VERSION 5.8 ;
BUSBITCHARS "[]" ;
DIVIDERCHAR "/" ;
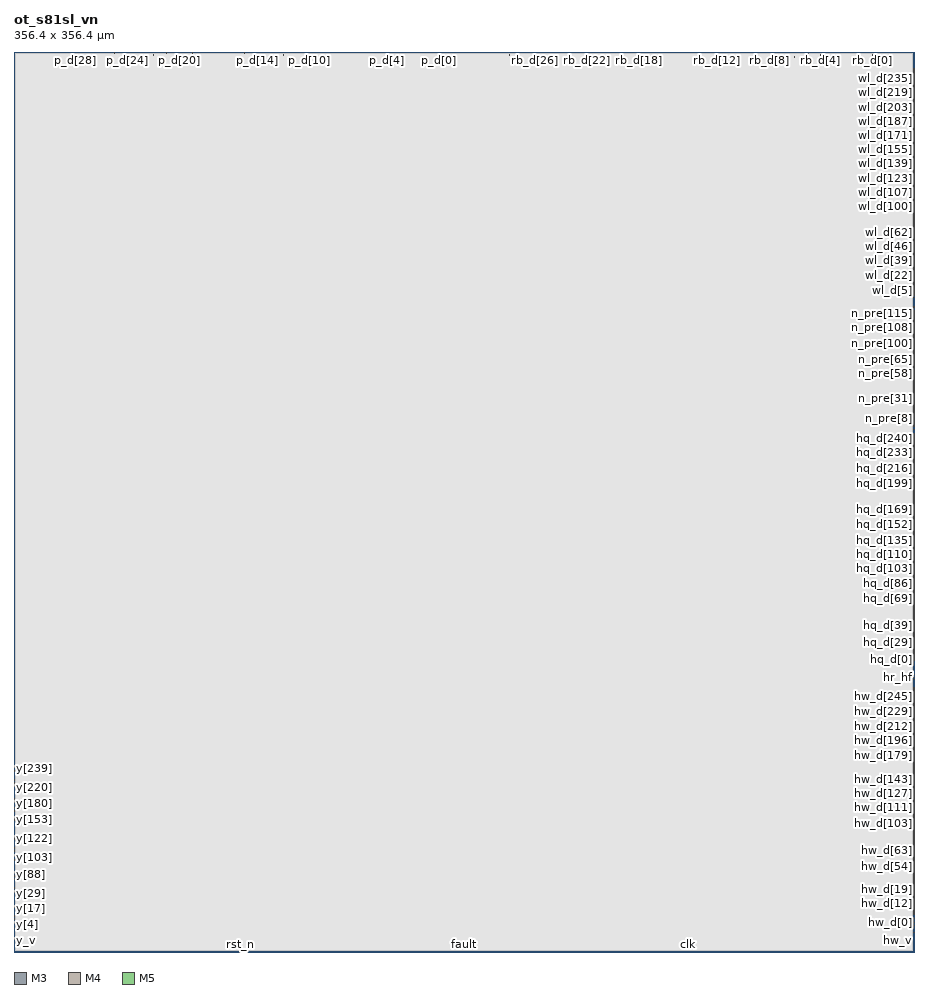
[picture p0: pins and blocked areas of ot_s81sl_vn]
MACRO ot_s81sl_vn
  CLASS BLOCK ;
  ORIGIN 0 0 ;
  FOREIGN ot_s81sl_vn 0 0 ;
  SIZE 356.400 BY 356.400 ;
  SYMMETRY X Y ;
  PIN clk
    DIRECTION INPUT ;
    USE SIGNAL ;
    PORT
      LAYER M3 ;
        RECT 266.7600 0.0495 266.7780 0.0875 ;
    END
  END clk
  PIN fault
    DIRECTION OUTPUT ;
    USE SIGNAL ;
    PORT
      LAYER M3 ;
        RECT 178.1640 1.6585 178.1820 1.6965 ;
    END
  END fault
  PIN hq_d[0]
    DIRECTION OUTPUT ;
    USE SIGNAL ;
    PORT
      LAYER M4 ;
        RECT 356.3160 115.6320 356.4000 115.6560 ;
    END
  END hq_d[0]
  PIN hq_d[100]
    DIRECTION OUTPUT ;
    USE SIGNAL ;
    PORT
      LAYER M4 ;
        RECT 356.3160 150.8160 356.4000 150.8400 ;
    END
  END hq_d[100]
  PIN hq_d[101]
    DIRECTION OUTPUT ;
    USE SIGNAL ;
    PORT
      LAYER M4 ;
        RECT 356.3160 151.1520 356.4000 151.1760 ;
    END
  END hq_d[101]
  PIN hq_d[102]
    DIRECTION OUTPUT ;
    USE SIGNAL ;
    PORT
      LAYER M4 ;
        RECT 356.3160 151.4880 356.4000 151.5120 ;
    END
  END hq_d[102]
  PIN hq_d[103]
    DIRECTION OUTPUT ;
    USE SIGNAL ;
    PORT
      LAYER M4 ;
        RECT 356.3160 151.8720 356.4000 151.8960 ;
    END
  END hq_d[103]
  PIN hq_d[104]
    DIRECTION OUTPUT ;
    USE SIGNAL ;
    PORT
      LAYER M4 ;
        RECT 356.3160 152.2080 356.4000 152.2320 ;
    END
  END hq_d[104]
  PIN hq_d[105]
    DIRECTION OUTPUT ;
    USE SIGNAL ;
    PORT
      LAYER M4 ;
        RECT 356.3160 152.5440 356.4000 152.5680 ;
    END
  END hq_d[105]
  PIN hq_d[106]
    DIRECTION OUTPUT ;
    USE SIGNAL ;
    PORT
      LAYER M4 ;
        RECT 356.3160 152.9280 356.4000 152.9520 ;
    END
  END hq_d[106]
  PIN hq_d[107]
    DIRECTION OUTPUT ;
    USE SIGNAL ;
    PORT
      LAYER M4 ;
        RECT 356.3160 153.2640 356.4000 153.2880 ;
    END
  END hq_d[107]
  PIN hq_d[108]
    DIRECTION OUTPUT ;
    USE SIGNAL ;
    PORT
      LAYER M4 ;
        RECT 356.3160 153.6000 356.4000 153.6240 ;
    END
  END hq_d[108]
  PIN hq_d[109]
    DIRECTION OUTPUT ;
    USE SIGNAL ;
    PORT
      LAYER M4 ;
        RECT 356.3160 153.9840 356.4000 154.0080 ;
    END
  END hq_d[109]
  PIN hq_d[10]
    DIRECTION OUTPUT ;
    USE SIGNAL ;
    PORT
      LAYER M4 ;
        RECT 356.3160 119.1360 356.4000 119.1600 ;
    END
  END hq_d[10]
  PIN hq_d[110]
    DIRECTION OUTPUT ;
    USE SIGNAL ;
    PORT
      LAYER M4 ;
        RECT 356.3160 154.3200 356.4000 154.3440 ;
    END
  END hq_d[110]
  PIN hq_d[111]
    DIRECTION OUTPUT ;
    USE SIGNAL ;
    PORT
      LAYER M4 ;
        RECT 356.3160 154.6560 356.4000 154.6800 ;
    END
  END hq_d[111]
  PIN hq_d[112]
    DIRECTION OUTPUT ;
    USE SIGNAL ;
    PORT
      LAYER M4 ;
        RECT 356.3160 155.0400 356.4000 155.0640 ;
    END
  END hq_d[112]
  PIN hq_d[113]
    DIRECTION OUTPUT ;
    USE SIGNAL ;
    PORT
      LAYER M4 ;
        RECT 356.3160 155.3760 356.4000 155.4000 ;
    END
  END hq_d[113]
  PIN hq_d[114]
    DIRECTION OUTPUT ;
    USE SIGNAL ;
    PORT
      LAYER M4 ;
        RECT 356.3160 155.7120 356.4000 155.7360 ;
    END
  END hq_d[114]
  PIN hq_d[115]
    DIRECTION OUTPUT ;
    USE SIGNAL ;
    PORT
      LAYER M4 ;
        RECT 356.3160 156.0960 356.4000 156.1200 ;
    END
  END hq_d[115]
  PIN hq_d[116]
    DIRECTION OUTPUT ;
    USE SIGNAL ;
    PORT
      LAYER M4 ;
        RECT 356.3160 156.4320 356.4000 156.4560 ;
    END
  END hq_d[116]
  PIN hq_d[117]
    DIRECTION OUTPUT ;
    USE SIGNAL ;
    PORT
      LAYER M4 ;
        RECT 356.3160 156.7680 356.4000 156.7920 ;
    END
  END hq_d[117]
  PIN hq_d[118]
    DIRECTION OUTPUT ;
    USE SIGNAL ;
    PORT
      LAYER M4 ;
        RECT 356.3160 157.1520 356.4000 157.1760 ;
    END
  END hq_d[118]
  PIN hq_d[119]
    DIRECTION OUTPUT ;
    USE SIGNAL ;
    PORT
      LAYER M4 ;
        RECT 356.3160 157.4880 356.4000 157.5120 ;
    END
  END hq_d[119]
  PIN hq_d[11]
    DIRECTION OUTPUT ;
    USE SIGNAL ;
    PORT
      LAYER M4 ;
        RECT 356.3160 119.4720 356.4000 119.4960 ;
    END
  END hq_d[11]
  PIN hq_d[120]
    DIRECTION OUTPUT ;
    USE SIGNAL ;
    PORT
      LAYER M4 ;
        RECT 356.3160 157.8240 356.4000 157.8480 ;
    END
  END hq_d[120]
  PIN hq_d[121]
    DIRECTION OUTPUT ;
    USE SIGNAL ;
    PORT
      LAYER M4 ;
        RECT 356.3160 158.2080 356.4000 158.2320 ;
    END
  END hq_d[121]
  PIN hq_d[122]
    DIRECTION OUTPUT ;
    USE SIGNAL ;
    PORT
      LAYER M4 ;
        RECT 356.3160 158.5440 356.4000 158.5680 ;
    END
  END hq_d[122]
  PIN hq_d[123]
    DIRECTION OUTPUT ;
    USE SIGNAL ;
    PORT
      LAYER M4 ;
        RECT 356.3160 158.8800 356.4000 158.9040 ;
    END
  END hq_d[123]
  PIN hq_d[124]
    DIRECTION OUTPUT ;
    USE SIGNAL ;
    PORT
      LAYER M4 ;
        RECT 356.3160 159.2640 356.4000 159.2880 ;
    END
  END hq_d[124]
  PIN hq_d[125]
    DIRECTION OUTPUT ;
    USE SIGNAL ;
    PORT
      LAYER M4 ;
        RECT 356.3160 159.6000 356.4000 159.6240 ;
    END
  END hq_d[125]
  PIN hq_d[126]
    DIRECTION OUTPUT ;
    USE SIGNAL ;
    PORT
      LAYER M4 ;
        RECT 356.3160 159.9360 356.4000 159.9600 ;
    END
  END hq_d[126]
  PIN hq_d[127]
    DIRECTION OUTPUT ;
    USE SIGNAL ;
    PORT
      LAYER M4 ;
        RECT 356.3160 160.3200 356.4000 160.3440 ;
    END
  END hq_d[127]
  PIN hq_d[128]
    DIRECTION OUTPUT ;
    USE SIGNAL ;
    PORT
      LAYER M4 ;
        RECT 356.3160 160.6560 356.4000 160.6800 ;
    END
  END hq_d[128]
  PIN hq_d[129]
    DIRECTION OUTPUT ;
    USE SIGNAL ;
    PORT
      LAYER M4 ;
        RECT 356.3160 160.9920 356.4000 161.0160 ;
    END
  END hq_d[129]
  PIN hq_d[12]
    DIRECTION OUTPUT ;
    USE SIGNAL ;
    PORT
      LAYER M4 ;
        RECT 356.3160 119.8560 356.4000 119.8800 ;
    END
  END hq_d[12]
  PIN hq_d[130]
    DIRECTION OUTPUT ;
    USE SIGNAL ;
    PORT
      LAYER M4 ;
        RECT 356.3160 161.3760 356.4000 161.4000 ;
    END
  END hq_d[130]
  PIN hq_d[131]
    DIRECTION OUTPUT ;
    USE SIGNAL ;
    PORT
      LAYER M4 ;
        RECT 356.3160 161.7120 356.4000 161.7360 ;
    END
  END hq_d[131]
  PIN hq_d[132]
    DIRECTION OUTPUT ;
    USE SIGNAL ;
    PORT
      LAYER M4 ;
        RECT 356.3160 162.0480 356.4000 162.0720 ;
    END
  END hq_d[132]
  PIN hq_d[133]
    DIRECTION OUTPUT ;
    USE SIGNAL ;
    PORT
      LAYER M4 ;
        RECT 356.3160 162.4320 356.4000 162.4560 ;
    END
  END hq_d[133]
  PIN hq_d[134]
    DIRECTION OUTPUT ;
    USE SIGNAL ;
    PORT
      LAYER M4 ;
        RECT 356.3160 162.7680 356.4000 162.7920 ;
    END
  END hq_d[134]
  PIN hq_d[135]
    DIRECTION OUTPUT ;
    USE SIGNAL ;
    PORT
      LAYER M4 ;
        RECT 356.3160 163.1040 356.4000 163.1280 ;
    END
  END hq_d[135]
  PIN hq_d[136]
    DIRECTION OUTPUT ;
    USE SIGNAL ;
    PORT
      LAYER M4 ;
        RECT 356.3160 163.4880 356.4000 163.5120 ;
    END
  END hq_d[136]
  PIN hq_d[137]
    DIRECTION OUTPUT ;
    USE SIGNAL ;
    PORT
      LAYER M4 ;
        RECT 356.3160 163.8240 356.4000 163.8480 ;
    END
  END hq_d[137]
  PIN hq_d[138]
    DIRECTION OUTPUT ;
    USE SIGNAL ;
    PORT
      LAYER M4 ;
        RECT 356.3160 164.1600 356.4000 164.1840 ;
    END
  END hq_d[138]
  PIN hq_d[139]
    DIRECTION OUTPUT ;
    USE SIGNAL ;
    PORT
      LAYER M4 ;
        RECT 356.3160 164.5440 356.4000 164.5680 ;
    END
  END hq_d[139]
  PIN hq_d[13]
    DIRECTION OUTPUT ;
    USE SIGNAL ;
    PORT
      LAYER M4 ;
        RECT 356.3160 120.1920 356.4000 120.2160 ;
    END
  END hq_d[13]
  PIN hq_d[140]
    DIRECTION OUTPUT ;
    USE SIGNAL ;
    PORT
      LAYER M4 ;
        RECT 356.3160 164.8800 356.4000 164.9040 ;
    END
  END hq_d[140]
  PIN hq_d[141]
    DIRECTION OUTPUT ;
    USE SIGNAL ;
    PORT
      LAYER M4 ;
        RECT 356.3160 165.2160 356.4000 165.2400 ;
    END
  END hq_d[141]
  PIN hq_d[142]
    DIRECTION OUTPUT ;
    USE SIGNAL ;
    PORT
      LAYER M4 ;
        RECT 356.3160 165.6000 356.4000 165.6240 ;
    END
  END hq_d[142]
  PIN hq_d[143]
    DIRECTION OUTPUT ;
    USE SIGNAL ;
    PORT
      LAYER M4 ;
        RECT 356.3160 165.9360 356.4000 165.9600 ;
    END
  END hq_d[143]
  PIN hq_d[144]
    DIRECTION OUTPUT ;
    USE SIGNAL ;
    PORT
      LAYER M4 ;
        RECT 356.3160 166.2720 356.4000 166.2960 ;
    END
  END hq_d[144]
  PIN hq_d[145]
    DIRECTION OUTPUT ;
    USE SIGNAL ;
    PORT
      LAYER M4 ;
        RECT 356.3160 166.6560 356.4000 166.6800 ;
    END
  END hq_d[145]
  PIN hq_d[146]
    DIRECTION OUTPUT ;
    USE SIGNAL ;
    PORT
      LAYER M4 ;
        RECT 356.3160 166.9920 356.4000 167.0160 ;
    END
  END hq_d[146]
  PIN hq_d[147]
    DIRECTION OUTPUT ;
    USE SIGNAL ;
    PORT
      LAYER M4 ;
        RECT 356.3160 167.3280 356.4000 167.3520 ;
    END
  END hq_d[147]
  PIN hq_d[148]
    DIRECTION OUTPUT ;
    USE SIGNAL ;
    PORT
      LAYER M4 ;
        RECT 356.3160 167.7120 356.4000 167.7360 ;
    END
  END hq_d[148]
  PIN hq_d[149]
    DIRECTION OUTPUT ;
    USE SIGNAL ;
    PORT
      LAYER M4 ;
        RECT 356.3160 168.0480 356.4000 168.0720 ;
    END
  END hq_d[149]
  PIN hq_d[14]
    DIRECTION OUTPUT ;
    USE SIGNAL ;
    PORT
      LAYER M4 ;
        RECT 356.3160 120.5280 356.4000 120.5520 ;
    END
  END hq_d[14]
  PIN hq_d[150]
    DIRECTION OUTPUT ;
    USE SIGNAL ;
    PORT
      LAYER M4 ;
        RECT 356.3160 168.3840 356.4000 168.4080 ;
    END
  END hq_d[150]
  PIN hq_d[151]
    DIRECTION OUTPUT ;
    USE SIGNAL ;
    PORT
      LAYER M4 ;
        RECT 356.3160 168.7680 356.4000 168.7920 ;
    END
  END hq_d[151]
  PIN hq_d[152]
    DIRECTION OUTPUT ;
    USE SIGNAL ;
    PORT
      LAYER M4 ;
        RECT 356.3160 169.1040 356.4000 169.1280 ;
    END
  END hq_d[152]
  PIN hq_d[153]
    DIRECTION OUTPUT ;
    USE SIGNAL ;
    PORT
      LAYER M4 ;
        RECT 356.3160 169.4400 356.4000 169.4640 ;
    END
  END hq_d[153]
  PIN hq_d[154]
    DIRECTION OUTPUT ;
    USE SIGNAL ;
    PORT
      LAYER M4 ;
        RECT 356.3160 169.8240 356.4000 169.8480 ;
    END
  END hq_d[154]
  PIN hq_d[155]
    DIRECTION OUTPUT ;
    USE SIGNAL ;
    PORT
      LAYER M4 ;
        RECT 356.3160 170.1600 356.4000 170.1840 ;
    END
  END hq_d[155]
  PIN hq_d[156]
    DIRECTION OUTPUT ;
    USE SIGNAL ;
    PORT
      LAYER M4 ;
        RECT 356.3160 170.4960 356.4000 170.5200 ;
    END
  END hq_d[156]
  PIN hq_d[157]
    DIRECTION OUTPUT ;
    USE SIGNAL ;
    PORT
      LAYER M4 ;
        RECT 356.3160 170.8800 356.4000 170.9040 ;
    END
  END hq_d[157]
  PIN hq_d[158]
    DIRECTION OUTPUT ;
    USE SIGNAL ;
    PORT
      LAYER M4 ;
        RECT 356.3160 171.2160 356.4000 171.2400 ;
    END
  END hq_d[158]
  PIN hq_d[159]
    DIRECTION OUTPUT ;
    USE SIGNAL ;
    PORT
      LAYER M4 ;
        RECT 356.3160 171.5520 356.4000 171.5760 ;
    END
  END hq_d[159]
  PIN hq_d[15]
    DIRECTION OUTPUT ;
    USE SIGNAL ;
    PORT
      LAYER M4 ;
        RECT 356.3160 120.9120 356.4000 120.9360 ;
    END
  END hq_d[15]
  PIN hq_d[160]
    DIRECTION OUTPUT ;
    USE SIGNAL ;
    PORT
      LAYER M4 ;
        RECT 356.3160 171.9360 356.4000 171.9600 ;
    END
  END hq_d[160]
  PIN hq_d[161]
    DIRECTION OUTPUT ;
    USE SIGNAL ;
    PORT
      LAYER M4 ;
        RECT 356.3160 172.2720 356.4000 172.2960 ;
    END
  END hq_d[161]
  PIN hq_d[162]
    DIRECTION OUTPUT ;
    USE SIGNAL ;
    PORT
      LAYER M4 ;
        RECT 356.3160 172.6080 356.4000 172.6320 ;
    END
  END hq_d[162]
  PIN hq_d[163]
    DIRECTION OUTPUT ;
    USE SIGNAL ;
    PORT
      LAYER M4 ;
        RECT 356.3160 172.9920 356.4000 173.0160 ;
    END
  END hq_d[163]
  PIN hq_d[164]
    DIRECTION OUTPUT ;
    USE SIGNAL ;
    PORT
      LAYER M4 ;
        RECT 356.3160 173.3280 356.4000 173.3520 ;
    END
  END hq_d[164]
  PIN hq_d[165]
    DIRECTION OUTPUT ;
    USE SIGNAL ;
    PORT
      LAYER M4 ;
        RECT 356.3160 173.6640 356.4000 173.6880 ;
    END
  END hq_d[165]
  PIN hq_d[166]
    DIRECTION OUTPUT ;
    USE SIGNAL ;
    PORT
      LAYER M4 ;
        RECT 356.3160 174.0480 356.4000 174.0720 ;
    END
  END hq_d[166]
  PIN hq_d[167]
    DIRECTION OUTPUT ;
    USE SIGNAL ;
    PORT
      LAYER M4 ;
        RECT 356.3160 174.3840 356.4000 174.4080 ;
    END
  END hq_d[167]
  PIN hq_d[168]
    DIRECTION OUTPUT ;
    USE SIGNAL ;
    PORT
      LAYER M4 ;
        RECT 356.3160 174.7200 356.4000 174.7440 ;
    END
  END hq_d[168]
  PIN hq_d[169]
    DIRECTION OUTPUT ;
    USE SIGNAL ;
    PORT
      LAYER M4 ;
        RECT 356.3160 175.1040 356.4000 175.1280 ;
    END
  END hq_d[169]
  PIN hq_d[16]
    DIRECTION OUTPUT ;
    USE SIGNAL ;
    PORT
      LAYER M4 ;
        RECT 356.3160 121.2480 356.4000 121.2720 ;
    END
  END hq_d[16]
  PIN hq_d[170]
    DIRECTION OUTPUT ;
    USE SIGNAL ;
    PORT
      LAYER M4 ;
        RECT 356.3160 175.4400 356.4000 175.4640 ;
    END
  END hq_d[170]
  PIN hq_d[171]
    DIRECTION OUTPUT ;
    USE SIGNAL ;
    PORT
      LAYER M4 ;
        RECT 356.3160 175.7760 356.4000 175.8000 ;
    END
  END hq_d[171]
  PIN hq_d[172]
    DIRECTION OUTPUT ;
    USE SIGNAL ;
    PORT
      LAYER M4 ;
        RECT 356.3160 176.1600 356.4000 176.1840 ;
    END
  END hq_d[172]
  PIN hq_d[173]
    DIRECTION OUTPUT ;
    USE SIGNAL ;
    PORT
      LAYER M4 ;
        RECT 356.3160 176.4960 356.4000 176.5200 ;
    END
  END hq_d[173]
  PIN hq_d[174]
    DIRECTION OUTPUT ;
    USE SIGNAL ;
    PORT
      LAYER M4 ;
        RECT 356.3160 176.8320 356.4000 176.8560 ;
    END
  END hq_d[174]
  PIN hq_d[175]
    DIRECTION OUTPUT ;
    USE SIGNAL ;
    PORT
      LAYER M4 ;
        RECT 356.3160 177.2160 356.4000 177.2400 ;
    END
  END hq_d[175]
  PIN hq_d[176]
    DIRECTION OUTPUT ;
    USE SIGNAL ;
    PORT
      LAYER M4 ;
        RECT 356.3160 177.5520 356.4000 177.5760 ;
    END
  END hq_d[176]
  PIN hq_d[177]
    DIRECTION OUTPUT ;
    USE SIGNAL ;
    PORT
      LAYER M4 ;
        RECT 356.3160 177.8880 356.4000 177.9120 ;
    END
  END hq_d[177]
  PIN hq_d[178]
    DIRECTION OUTPUT ;
    USE SIGNAL ;
    PORT
      LAYER M4 ;
        RECT 356.3160 178.2720 356.4000 178.2960 ;
    END
  END hq_d[178]
  PIN hq_d[179]
    DIRECTION OUTPUT ;
    USE SIGNAL ;
    PORT
      LAYER M4 ;
        RECT 356.3160 178.6080 356.4000 178.6320 ;
    END
  END hq_d[179]
  PIN hq_d[17]
    DIRECTION OUTPUT ;
    USE SIGNAL ;
    PORT
      LAYER M4 ;
        RECT 356.3160 121.5840 356.4000 121.6080 ;
    END
  END hq_d[17]
  PIN hq_d[180]
    DIRECTION OUTPUT ;
    USE SIGNAL ;
    PORT
      LAYER M4 ;
        RECT 356.3160 178.9440 356.4000 178.9680 ;
    END
  END hq_d[180]
  PIN hq_d[181]
    DIRECTION OUTPUT ;
    USE SIGNAL ;
    PORT
      LAYER M4 ;
        RECT 356.3160 179.2800 356.4000 179.3040 ;
    END
  END hq_d[181]
  PIN hq_d[182]
    DIRECTION OUTPUT ;
    USE SIGNAL ;
    PORT
      LAYER M4 ;
        RECT 356.3160 179.6640 356.4000 179.6880 ;
    END
  END hq_d[182]
  PIN hq_d[183]
    DIRECTION OUTPUT ;
    USE SIGNAL ;
    PORT
      LAYER M4 ;
        RECT 356.3160 180.0000 356.4000 180.0240 ;
    END
  END hq_d[183]
  PIN hq_d[184]
    DIRECTION OUTPUT ;
    USE SIGNAL ;
    PORT
      LAYER M4 ;
        RECT 356.3160 180.3360 356.4000 180.3600 ;
    END
  END hq_d[184]
  PIN hq_d[185]
    DIRECTION OUTPUT ;
    USE SIGNAL ;
    PORT
      LAYER M4 ;
        RECT 356.3160 180.7200 356.4000 180.7440 ;
    END
  END hq_d[185]
  PIN hq_d[186]
    DIRECTION OUTPUT ;
    USE SIGNAL ;
    PORT
      LAYER M4 ;
        RECT 356.3160 181.0560 356.4000 181.0800 ;
    END
  END hq_d[186]
  PIN hq_d[187]
    DIRECTION OUTPUT ;
    USE SIGNAL ;
    PORT
      LAYER M4 ;
        RECT 356.3160 181.3920 356.4000 181.4160 ;
    END
  END hq_d[187]
  PIN hq_d[188]
    DIRECTION OUTPUT ;
    USE SIGNAL ;
    PORT
      LAYER M4 ;
        RECT 356.3160 181.7760 356.4000 181.8000 ;
    END
  END hq_d[188]
  PIN hq_d[189]
    DIRECTION OUTPUT ;
    USE SIGNAL ;
    PORT
      LAYER M4 ;
        RECT 356.3160 182.1120 356.4000 182.1360 ;
    END
  END hq_d[189]
  PIN hq_d[18]
    DIRECTION OUTPUT ;
    USE SIGNAL ;
    PORT
      LAYER M4 ;
        RECT 356.3160 121.9680 356.4000 121.9920 ;
    END
  END hq_d[18]
  PIN hq_d[190]
    DIRECTION OUTPUT ;
    USE SIGNAL ;
    PORT
      LAYER M4 ;
        RECT 356.3160 182.4480 356.4000 182.4720 ;
    END
  END hq_d[190]
  PIN hq_d[191]
    DIRECTION OUTPUT ;
    USE SIGNAL ;
    PORT
      LAYER M4 ;
        RECT 356.3160 182.8320 356.4000 182.8560 ;
    END
  END hq_d[191]
  PIN hq_d[192]
    DIRECTION OUTPUT ;
    USE SIGNAL ;
    PORT
      LAYER M4 ;
        RECT 356.3160 183.1680 356.4000 183.1920 ;
    END
  END hq_d[192]
  PIN hq_d[193]
    DIRECTION OUTPUT ;
    USE SIGNAL ;
    PORT
      LAYER M4 ;
        RECT 356.3160 183.5040 356.4000 183.5280 ;
    END
  END hq_d[193]
  PIN hq_d[194]
    DIRECTION OUTPUT ;
    USE SIGNAL ;
    PORT
      LAYER M4 ;
        RECT 356.3160 183.8880 356.4000 183.9120 ;
    END
  END hq_d[194]
  PIN hq_d[195]
    DIRECTION OUTPUT ;
    USE SIGNAL ;
    PORT
      LAYER M4 ;
        RECT 356.3160 184.2240 356.4000 184.2480 ;
    END
  END hq_d[195]
  PIN hq_d[196]
    DIRECTION OUTPUT ;
    USE SIGNAL ;
    PORT
      LAYER M4 ;
        RECT 356.3160 184.5600 356.4000 184.5840 ;
    END
  END hq_d[196]
  PIN hq_d[197]
    DIRECTION OUTPUT ;
    USE SIGNAL ;
    PORT
      LAYER M4 ;
        RECT 356.3160 184.9440 356.4000 184.9680 ;
    END
  END hq_d[197]
  PIN hq_d[198]
    DIRECTION OUTPUT ;
    USE SIGNAL ;
    PORT
      LAYER M4 ;
        RECT 356.3160 185.2800 356.4000 185.3040 ;
    END
  END hq_d[198]
  PIN hq_d[199]
    DIRECTION OUTPUT ;
    USE SIGNAL ;
    PORT
      LAYER M4 ;
        RECT 356.3160 185.6160 356.4000 185.6400 ;
    END
  END hq_d[199]
  PIN hq_d[19]
    DIRECTION OUTPUT ;
    USE SIGNAL ;
    PORT
      LAYER M4 ;
        RECT 356.3160 122.3040 356.4000 122.3280 ;
    END
  END hq_d[19]
  PIN hq_d[1]
    DIRECTION OUTPUT ;
    USE SIGNAL ;
    PORT
      LAYER M4 ;
        RECT 356.3160 115.9680 356.4000 115.9920 ;
    END
  END hq_d[1]
  PIN hq_d[200]
    DIRECTION OUTPUT ;
    USE SIGNAL ;
    PORT
      LAYER M4 ;
        RECT 356.3160 186.0000 356.4000 186.0240 ;
    END
  END hq_d[200]
  PIN hq_d[201]
    DIRECTION OUTPUT ;
    USE SIGNAL ;
    PORT
      LAYER M4 ;
        RECT 356.3160 186.3360 356.4000 186.3600 ;
    END
  END hq_d[201]
  PIN hq_d[202]
    DIRECTION OUTPUT ;
    USE SIGNAL ;
    PORT
      LAYER M4 ;
        RECT 356.3160 186.6720 356.4000 186.6960 ;
    END
  END hq_d[202]
  PIN hq_d[203]
    DIRECTION OUTPUT ;
    USE SIGNAL ;
    PORT
      LAYER M4 ;
        RECT 356.3160 187.0560 356.4000 187.0800 ;
    END
  END hq_d[203]
  PIN hq_d[204]
    DIRECTION OUTPUT ;
    USE SIGNAL ;
    PORT
      LAYER M4 ;
        RECT 356.3160 187.3920 356.4000 187.4160 ;
    END
  END hq_d[204]
  PIN hq_d[205]
    DIRECTION OUTPUT ;
    USE SIGNAL ;
    PORT
      LAYER M4 ;
        RECT 356.3160 187.7280 356.4000 187.7520 ;
    END
  END hq_d[205]
  PIN hq_d[206]
    DIRECTION OUTPUT ;
    USE SIGNAL ;
    PORT
      LAYER M4 ;
        RECT 356.3160 188.1120 356.4000 188.1360 ;
    END
  END hq_d[206]
  PIN hq_d[207]
    DIRECTION OUTPUT ;
    USE SIGNAL ;
    PORT
      LAYER M4 ;
        RECT 356.3160 188.4480 356.4000 188.4720 ;
    END
  END hq_d[207]
  PIN hq_d[208]
    DIRECTION OUTPUT ;
    USE SIGNAL ;
    PORT
      LAYER M4 ;
        RECT 356.3160 188.7840 356.4000 188.8080 ;
    END
  END hq_d[208]
  PIN hq_d[209]
    DIRECTION OUTPUT ;
    USE SIGNAL ;
    PORT
      LAYER M4 ;
        RECT 356.3160 189.1680 356.4000 189.1920 ;
    END
  END hq_d[209]
  PIN hq_d[20]
    DIRECTION OUTPUT ;
    USE SIGNAL ;
    PORT
      LAYER M4 ;
        RECT 356.3160 122.6400 356.4000 122.6640 ;
    END
  END hq_d[20]
  PIN hq_d[210]
    DIRECTION OUTPUT ;
    USE SIGNAL ;
    PORT
      LAYER M4 ;
        RECT 356.3160 189.5040 356.4000 189.5280 ;
    END
  END hq_d[210]
  PIN hq_d[211]
    DIRECTION OUTPUT ;
    USE SIGNAL ;
    PORT
      LAYER M4 ;
        RECT 356.3160 189.8400 356.4000 189.8640 ;
    END
  END hq_d[211]
  PIN hq_d[212]
    DIRECTION OUTPUT ;
    USE SIGNAL ;
    PORT
      LAYER M4 ;
        RECT 356.3160 190.2240 356.4000 190.2480 ;
    END
  END hq_d[212]
  PIN hq_d[213]
    DIRECTION OUTPUT ;
    USE SIGNAL ;
    PORT
      LAYER M4 ;
        RECT 356.3160 190.5600 356.4000 190.5840 ;
    END
  END hq_d[213]
  PIN hq_d[214]
    DIRECTION OUTPUT ;
    USE SIGNAL ;
    PORT
      LAYER M4 ;
        RECT 356.3160 190.8960 356.4000 190.9200 ;
    END
  END hq_d[214]
  PIN hq_d[215]
    DIRECTION OUTPUT ;
    USE SIGNAL ;
    PORT
      LAYER M4 ;
        RECT 356.3160 191.2800 356.4000 191.3040 ;
    END
  END hq_d[215]
  PIN hq_d[216]
    DIRECTION OUTPUT ;
    USE SIGNAL ;
    PORT
      LAYER M4 ;
        RECT 356.3160 191.6160 356.4000 191.6400 ;
    END
  END hq_d[216]
  PIN hq_d[217]
    DIRECTION OUTPUT ;
    USE SIGNAL ;
    PORT
      LAYER M4 ;
        RECT 356.3160 191.9520 356.4000 191.9760 ;
    END
  END hq_d[217]
  PIN hq_d[218]
    DIRECTION OUTPUT ;
    USE SIGNAL ;
    PORT
      LAYER M4 ;
        RECT 356.3160 192.3360 356.4000 192.3600 ;
    END
  END hq_d[218]
  PIN hq_d[219]
    DIRECTION OUTPUT ;
    USE SIGNAL ;
    PORT
      LAYER M4 ;
        RECT 356.3160 192.6720 356.4000 192.6960 ;
    END
  END hq_d[219]
  PIN hq_d[21]
    DIRECTION OUTPUT ;
    USE SIGNAL ;
    PORT
      LAYER M4 ;
        RECT 356.3160 123.0240 356.4000 123.0480 ;
    END
  END hq_d[21]
  PIN hq_d[220]
    DIRECTION OUTPUT ;
    USE SIGNAL ;
    PORT
      LAYER M4 ;
        RECT 356.3160 193.0080 356.4000 193.0320 ;
    END
  END hq_d[220]
  PIN hq_d[221]
    DIRECTION OUTPUT ;
    USE SIGNAL ;
    PORT
      LAYER M4 ;
        RECT 356.3160 193.3920 356.4000 193.4160 ;
    END
  END hq_d[221]
  PIN hq_d[222]
    DIRECTION OUTPUT ;
    USE SIGNAL ;
    PORT
      LAYER M4 ;
        RECT 356.3160 193.7280 356.4000 193.7520 ;
    END
  END hq_d[222]
  PIN hq_d[223]
    DIRECTION OUTPUT ;
    USE SIGNAL ;
    PORT
      LAYER M4 ;
        RECT 356.3160 194.0640 356.4000 194.0880 ;
    END
  END hq_d[223]
  PIN hq_d[224]
    DIRECTION OUTPUT ;
    USE SIGNAL ;
    PORT
      LAYER M4 ;
        RECT 356.3160 194.4480 356.4000 194.4720 ;
    END
  END hq_d[224]
  PIN hq_d[225]
    DIRECTION OUTPUT ;
    USE SIGNAL ;
    PORT
      LAYER M4 ;
        RECT 356.3160 194.7840 356.4000 194.8080 ;
    END
  END hq_d[225]
  PIN hq_d[226]
    DIRECTION OUTPUT ;
    USE SIGNAL ;
    PORT
      LAYER M4 ;
        RECT 356.3160 195.1200 356.4000 195.1440 ;
    END
  END hq_d[226]
  PIN hq_d[227]
    DIRECTION OUTPUT ;
    USE SIGNAL ;
    PORT
      LAYER M4 ;
        RECT 356.3160 195.5040 356.4000 195.5280 ;
    END
  END hq_d[227]
  PIN hq_d[228]
    DIRECTION OUTPUT ;
    USE SIGNAL ;
    PORT
      LAYER M4 ;
        RECT 356.3160 195.8400 356.4000 195.8640 ;
    END
  END hq_d[228]
  PIN hq_d[229]
    DIRECTION OUTPUT ;
    USE SIGNAL ;
    PORT
      LAYER M4 ;
        RECT 356.3160 196.1760 356.4000 196.2000 ;
    END
  END hq_d[229]
  PIN hq_d[22]
    DIRECTION OUTPUT ;
    USE SIGNAL ;
    PORT
      LAYER M4 ;
        RECT 356.3160 123.3600 356.4000 123.3840 ;
    END
  END hq_d[22]
  PIN hq_d[230]
    DIRECTION OUTPUT ;
    USE SIGNAL ;
    PORT
      LAYER M4 ;
        RECT 356.3160 196.5600 356.4000 196.5840 ;
    END
  END hq_d[230]
  PIN hq_d[231]
    DIRECTION OUTPUT ;
    USE SIGNAL ;
    PORT
      LAYER M4 ;
        RECT 356.3160 196.8960 356.4000 196.9200 ;
    END
  END hq_d[231]
  PIN hq_d[232]
    DIRECTION OUTPUT ;
    USE SIGNAL ;
    PORT
      LAYER M4 ;
        RECT 356.3160 197.2320 356.4000 197.2560 ;
    END
  END hq_d[232]
  PIN hq_d[233]
    DIRECTION OUTPUT ;
    USE SIGNAL ;
    PORT
      LAYER M4 ;
        RECT 356.3160 197.6160 356.4000 197.6400 ;
    END
  END hq_d[233]
  PIN hq_d[234]
    DIRECTION OUTPUT ;
    USE SIGNAL ;
    PORT
      LAYER M4 ;
        RECT 356.3160 197.9520 356.4000 197.9760 ;
    END
  END hq_d[234]
  PIN hq_d[235]
    DIRECTION OUTPUT ;
    USE SIGNAL ;
    PORT
      LAYER M4 ;
        RECT 356.3160 198.2880 356.4000 198.3120 ;
    END
  END hq_d[235]
  PIN hq_d[236]
    DIRECTION OUTPUT ;
    USE SIGNAL ;
    PORT
      LAYER M4 ;
        RECT 356.3160 198.6720 356.4000 198.6960 ;
    END
  END hq_d[236]
  PIN hq_d[237]
    DIRECTION OUTPUT ;
    USE SIGNAL ;
    PORT
      LAYER M4 ;
        RECT 356.3160 199.0080 356.4000 199.0320 ;
    END
  END hq_d[237]
  PIN hq_d[238]
    DIRECTION OUTPUT ;
    USE SIGNAL ;
    PORT
      LAYER M4 ;
        RECT 356.3160 199.3440 356.4000 199.3680 ;
    END
  END hq_d[238]
  PIN hq_d[239]
    DIRECTION OUTPUT ;
    USE SIGNAL ;
    PORT
      LAYER M4 ;
        RECT 356.3160 199.7280 356.4000 199.7520 ;
    END
  END hq_d[239]
  PIN hq_d[23]
    DIRECTION OUTPUT ;
    USE SIGNAL ;
    PORT
      LAYER M4 ;
        RECT 356.3160 123.6960 356.4000 123.7200 ;
    END
  END hq_d[23]
  PIN hq_d[240]
    DIRECTION OUTPUT ;
    USE SIGNAL ;
    PORT
      LAYER M4 ;
        RECT 356.3160 200.0640 356.4000 200.0880 ;
    END
  END hq_d[240]
  PIN hq_d[241]
    DIRECTION OUTPUT ;
    USE SIGNAL ;
    PORT
      LAYER M4 ;
        RECT 356.3160 200.4000 356.4000 200.4240 ;
    END
  END hq_d[241]
  PIN hq_d[242]
    DIRECTION OUTPUT ;
    USE SIGNAL ;
    PORT
      LAYER M4 ;
        RECT 356.3160 200.7840 356.4000 200.8080 ;
    END
  END hq_d[242]
  PIN hq_d[243]
    DIRECTION OUTPUT ;
    USE SIGNAL ;
    PORT
      LAYER M4 ;
        RECT 356.3160 201.1200 356.4000 201.1440 ;
    END
  END hq_d[243]
  PIN hq_d[244]
    DIRECTION OUTPUT ;
    USE SIGNAL ;
    PORT
      LAYER M4 ;
        RECT 356.3160 201.4560 356.4000 201.4800 ;
    END
  END hq_d[244]
  PIN hq_d[245]
    DIRECTION OUTPUT ;
    USE SIGNAL ;
    PORT
      LAYER M4 ;
        RECT 356.3160 201.8400 356.4000 201.8640 ;
    END
  END hq_d[245]
  PIN hq_d[246]
    DIRECTION OUTPUT ;
    USE SIGNAL ;
    PORT
      LAYER M4 ;
        RECT 356.3160 202.1760 356.4000 202.2000 ;
    END
  END hq_d[246]
  PIN hq_d[247]
    DIRECTION OUTPUT ;
    USE SIGNAL ;
    PORT
      LAYER M4 ;
        RECT 356.3160 202.5120 356.4000 202.5360 ;
    END
  END hq_d[247]
  PIN hq_d[248]
    DIRECTION OUTPUT ;
    USE SIGNAL ;
    PORT
      LAYER M4 ;
        RECT 356.3160 202.8960 356.4000 202.9200 ;
    END
  END hq_d[248]
  PIN hq_d[249]
    DIRECTION OUTPUT ;
    USE SIGNAL ;
    PORT
      LAYER M4 ;
        RECT 356.3160 203.2320 356.4000 203.2560 ;
    END
  END hq_d[249]
  PIN hq_d[24]
    DIRECTION OUTPUT ;
    USE SIGNAL ;
    PORT
      LAYER M4 ;
        RECT 356.3160 124.0800 356.4000 124.1040 ;
    END
  END hq_d[24]
  PIN hq_d[250]
    DIRECTION OUTPUT ;
    USE SIGNAL ;
    PORT
      LAYER M4 ;
        RECT 356.3160 203.5680 356.4000 203.5920 ;
    END
  END hq_d[250]
  PIN hq_d[251]
    DIRECTION OUTPUT ;
    USE SIGNAL ;
    PORT
      LAYER M4 ;
        RECT 356.3160 203.9520 356.4000 203.9760 ;
    END
  END hq_d[251]
  PIN hq_d[252]
    DIRECTION OUTPUT ;
    USE SIGNAL ;
    PORT
      LAYER M4 ;
        RECT 356.3160 204.2880 356.4000 204.3120 ;
    END
  END hq_d[252]
  PIN hq_d[253]
    DIRECTION OUTPUT ;
    USE SIGNAL ;
    PORT
      LAYER M4 ;
        RECT 356.3160 204.6240 356.4000 204.6480 ;
    END
  END hq_d[253]
  PIN hq_d[254]
    DIRECTION OUTPUT ;
    USE SIGNAL ;
    PORT
      LAYER M4 ;
        RECT 356.3160 205.0080 356.4000 205.0320 ;
    END
  END hq_d[254]
  PIN hq_d[255]
    DIRECTION OUTPUT ;
    USE SIGNAL ;
    PORT
      LAYER M4 ;
        RECT 356.3160 205.3440 356.4000 205.3680 ;
    END
  END hq_d[255]
  PIN hq_d[25]
    DIRECTION OUTPUT ;
    USE SIGNAL ;
    PORT
      LAYER M4 ;
        RECT 356.3160 124.4160 356.4000 124.4400 ;
    END
  END hq_d[25]
  PIN hq_d[26]
    DIRECTION OUTPUT ;
    USE SIGNAL ;
    PORT
      LAYER M4 ;
        RECT 356.3160 124.7520 356.4000 124.7760 ;
    END
  END hq_d[26]
  PIN hq_d[27]
    DIRECTION OUTPUT ;
    USE SIGNAL ;
    PORT
      LAYER M4 ;
        RECT 356.3160 125.1360 356.4000 125.1600 ;
    END
  END hq_d[27]
  PIN hq_d[28]
    DIRECTION OUTPUT ;
    USE SIGNAL ;
    PORT
      LAYER M4 ;
        RECT 356.3160 125.4720 356.4000 125.4960 ;
    END
  END hq_d[28]
  PIN hq_d[29]
    DIRECTION OUTPUT ;
    USE SIGNAL ;
    PORT
      LAYER M4 ;
        RECT 356.3160 125.8080 356.4000 125.8320 ;
    END
  END hq_d[29]
  PIN hq_d[2]
    DIRECTION OUTPUT ;
    USE SIGNAL ;
    PORT
      LAYER M4 ;
        RECT 356.3160 116.3040 356.4000 116.3280 ;
    END
  END hq_d[2]
  PIN hq_d[30]
    DIRECTION OUTPUT ;
    USE SIGNAL ;
    PORT
      LAYER M4 ;
        RECT 356.3160 126.1920 356.4000 126.2160 ;
    END
  END hq_d[30]
  PIN hq_d[31]
    DIRECTION OUTPUT ;
    USE SIGNAL ;
    PORT
      LAYER M4 ;
        RECT 356.3160 126.5280 356.4000 126.5520 ;
    END
  END hq_d[31]
  PIN hq_d[32]
    DIRECTION OUTPUT ;
    USE SIGNAL ;
    PORT
      LAYER M4 ;
        RECT 356.3160 126.8640 356.4000 126.8880 ;
    END
  END hq_d[32]
  PIN hq_d[33]
    DIRECTION OUTPUT ;
    USE SIGNAL ;
    PORT
      LAYER M4 ;
        RECT 356.3160 127.2480 356.4000 127.2720 ;
    END
  END hq_d[33]
  PIN hq_d[34]
    DIRECTION OUTPUT ;
    USE SIGNAL ;
    PORT
      LAYER M4 ;
        RECT 356.3160 127.5840 356.4000 127.6080 ;
    END
  END hq_d[34]
  PIN hq_d[35]
    DIRECTION OUTPUT ;
    USE SIGNAL ;
    PORT
      LAYER M4 ;
        RECT 356.3160 127.9200 356.4000 127.9440 ;
    END
  END hq_d[35]
  PIN hq_d[36]
    DIRECTION OUTPUT ;
    USE SIGNAL ;
    PORT
      LAYER M4 ;
        RECT 356.3160 128.3040 356.4000 128.3280 ;
    END
  END hq_d[36]
  PIN hq_d[37]
    DIRECTION OUTPUT ;
    USE SIGNAL ;
    PORT
      LAYER M4 ;
        RECT 356.3160 128.6400 356.4000 128.6640 ;
    END
  END hq_d[37]
  PIN hq_d[38]
    DIRECTION OUTPUT ;
    USE SIGNAL ;
    PORT
      LAYER M4 ;
        RECT 356.3160 128.9760 356.4000 129.0000 ;
    END
  END hq_d[38]
  PIN hq_d[39]
    DIRECTION OUTPUT ;
    USE SIGNAL ;
    PORT
      LAYER M4 ;
        RECT 356.3160 129.3600 356.4000 129.3840 ;
    END
  END hq_d[39]
  PIN hq_d[3]
    DIRECTION OUTPUT ;
    USE SIGNAL ;
    PORT
      LAYER M4 ;
        RECT 356.3160 116.6880 356.4000 116.7120 ;
    END
  END hq_d[3]
  PIN hq_d[40]
    DIRECTION OUTPUT ;
    USE SIGNAL ;
    PORT
      LAYER M4 ;
        RECT 356.3160 129.6960 356.4000 129.7200 ;
    END
  END hq_d[40]
  PIN hq_d[41]
    DIRECTION OUTPUT ;
    USE SIGNAL ;
    PORT
      LAYER M4 ;
        RECT 356.3160 130.0320 356.4000 130.0560 ;
    END
  END hq_d[41]
  PIN hq_d[42]
    DIRECTION OUTPUT ;
    USE SIGNAL ;
    PORT
      LAYER M4 ;
        RECT 356.3160 130.4160 356.4000 130.4400 ;
    END
  END hq_d[42]
  PIN hq_d[43]
    DIRECTION OUTPUT ;
    USE SIGNAL ;
    PORT
      LAYER M4 ;
        RECT 356.3160 130.7520 356.4000 130.7760 ;
    END
  END hq_d[43]
  PIN hq_d[44]
    DIRECTION OUTPUT ;
    USE SIGNAL ;
    PORT
      LAYER M4 ;
        RECT 356.3160 131.0880 356.4000 131.1120 ;
    END
  END hq_d[44]
  PIN hq_d[45]
    DIRECTION OUTPUT ;
    USE SIGNAL ;
    PORT
      LAYER M4 ;
        RECT 356.3160 131.4720 356.4000 131.4960 ;
    END
  END hq_d[45]
  PIN hq_d[46]
    DIRECTION OUTPUT ;
    USE SIGNAL ;
    PORT
      LAYER M4 ;
        RECT 356.3160 131.8080 356.4000 131.8320 ;
    END
  END hq_d[46]
  PIN hq_d[47]
    DIRECTION OUTPUT ;
    USE SIGNAL ;
    PORT
      LAYER M4 ;
        RECT 356.3160 132.1440 356.4000 132.1680 ;
    END
  END hq_d[47]
  PIN hq_d[48]
    DIRECTION OUTPUT ;
    USE SIGNAL ;
    PORT
      LAYER M4 ;
        RECT 356.3160 132.5280 356.4000 132.5520 ;
    END
  END hq_d[48]
  PIN hq_d[49]
    DIRECTION OUTPUT ;
    USE SIGNAL ;
    PORT
      LAYER M4 ;
        RECT 356.3160 132.8640 356.4000 132.8880 ;
    END
  END hq_d[49]
  PIN hq_d[4]
    DIRECTION OUTPUT ;
    USE SIGNAL ;
    PORT
      LAYER M4 ;
        RECT 356.3160 117.0240 356.4000 117.0480 ;
    END
  END hq_d[4]
  PIN hq_d[50]
    DIRECTION OUTPUT ;
    USE SIGNAL ;
    PORT
      LAYER M4 ;
        RECT 356.3160 133.2000 356.4000 133.2240 ;
    END
  END hq_d[50]
  PIN hq_d[51]
    DIRECTION OUTPUT ;
    USE SIGNAL ;
    PORT
      LAYER M4 ;
        RECT 356.3160 133.5840 356.4000 133.6080 ;
    END
  END hq_d[51]
  PIN hq_d[52]
    DIRECTION OUTPUT ;
    USE SIGNAL ;
    PORT
      LAYER M4 ;
        RECT 356.3160 133.9200 356.4000 133.9440 ;
    END
  END hq_d[52]
  PIN hq_d[53]
    DIRECTION OUTPUT ;
    USE SIGNAL ;
    PORT
      LAYER M4 ;
        RECT 356.3160 134.2560 356.4000 134.2800 ;
    END
  END hq_d[53]
  PIN hq_d[54]
    DIRECTION OUTPUT ;
    USE SIGNAL ;
    PORT
      LAYER M4 ;
        RECT 356.3160 134.6400 356.4000 134.6640 ;
    END
  END hq_d[54]
  PIN hq_d[55]
    DIRECTION OUTPUT ;
    USE SIGNAL ;
    PORT
      LAYER M4 ;
        RECT 356.3160 134.9760 356.4000 135.0000 ;
    END
  END hq_d[55]
  PIN hq_d[56]
    DIRECTION OUTPUT ;
    USE SIGNAL ;
    PORT
      LAYER M4 ;
        RECT 356.3160 135.3120 356.4000 135.3360 ;
    END
  END hq_d[56]
  PIN hq_d[57]
    DIRECTION OUTPUT ;
    USE SIGNAL ;
    PORT
      LAYER M4 ;
        RECT 356.3160 135.6960 356.4000 135.7200 ;
    END
  END hq_d[57]
  PIN hq_d[58]
    DIRECTION OUTPUT ;
    USE SIGNAL ;
    PORT
      LAYER M4 ;
        RECT 356.3160 136.0320 356.4000 136.0560 ;
    END
  END hq_d[58]
  PIN hq_d[59]
    DIRECTION OUTPUT ;
    USE SIGNAL ;
    PORT
      LAYER M4 ;
        RECT 356.3160 136.3680 356.4000 136.3920 ;
    END
  END hq_d[59]
  PIN hq_d[5]
    DIRECTION OUTPUT ;
    USE SIGNAL ;
    PORT
      LAYER M4 ;
        RECT 356.3160 117.3600 356.4000 117.3840 ;
    END
  END hq_d[5]
  PIN hq_d[60]
    DIRECTION OUTPUT ;
    USE SIGNAL ;
    PORT
      LAYER M4 ;
        RECT 356.3160 136.7520 356.4000 136.7760 ;
    END
  END hq_d[60]
  PIN hq_d[61]
    DIRECTION OUTPUT ;
    USE SIGNAL ;
    PORT
      LAYER M4 ;
        RECT 356.3160 137.0880 356.4000 137.1120 ;
    END
  END hq_d[61]
  PIN hq_d[62]
    DIRECTION OUTPUT ;
    USE SIGNAL ;
    PORT
      LAYER M4 ;
        RECT 356.3160 137.4240 356.4000 137.4480 ;
    END
  END hq_d[62]
  PIN hq_d[63]
    DIRECTION OUTPUT ;
    USE SIGNAL ;
    PORT
      LAYER M4 ;
        RECT 356.3160 137.8080 356.4000 137.8320 ;
    END
  END hq_d[63]
  PIN hq_d[64]
    DIRECTION OUTPUT ;
    USE SIGNAL ;
    PORT
      LAYER M4 ;
        RECT 356.3160 138.1440 356.4000 138.1680 ;
    END
  END hq_d[64]
  PIN hq_d[65]
    DIRECTION OUTPUT ;
    USE SIGNAL ;
    PORT
      LAYER M4 ;
        RECT 356.3160 138.4800 356.4000 138.5040 ;
    END
  END hq_d[65]
  PIN hq_d[66]
    DIRECTION OUTPUT ;
    USE SIGNAL ;
    PORT
      LAYER M4 ;
        RECT 356.3160 138.8640 356.4000 138.8880 ;
    END
  END hq_d[66]
  PIN hq_d[67]
    DIRECTION OUTPUT ;
    USE SIGNAL ;
    PORT
      LAYER M4 ;
        RECT 356.3160 139.2000 356.4000 139.2240 ;
    END
  END hq_d[67]
  PIN hq_d[68]
    DIRECTION OUTPUT ;
    USE SIGNAL ;
    PORT
      LAYER M4 ;
        RECT 356.3160 139.5360 356.4000 139.5600 ;
    END
  END hq_d[68]
  PIN hq_d[69]
    DIRECTION OUTPUT ;
    USE SIGNAL ;
    PORT
      LAYER M4 ;
        RECT 356.3160 139.8720 356.4000 139.8960 ;
    END
  END hq_d[69]
  PIN hq_d[6]
    DIRECTION OUTPUT ;
    USE SIGNAL ;
    PORT
      LAYER M4 ;
        RECT 356.3160 117.7440 356.4000 117.7680 ;
    END
  END hq_d[6]
  PIN hq_d[70]
    DIRECTION OUTPUT ;
    USE SIGNAL ;
    PORT
      LAYER M4 ;
        RECT 356.3160 140.2560 356.4000 140.2800 ;
    END
  END hq_d[70]
  PIN hq_d[71]
    DIRECTION OUTPUT ;
    USE SIGNAL ;
    PORT
      LAYER M4 ;
        RECT 356.3160 140.5920 356.4000 140.6160 ;
    END
  END hq_d[71]
  PIN hq_d[72]
    DIRECTION OUTPUT ;
    USE SIGNAL ;
    PORT
      LAYER M4 ;
        RECT 356.3160 140.9280 356.4000 140.9520 ;
    END
  END hq_d[72]
  PIN hq_d[73]
    DIRECTION OUTPUT ;
    USE SIGNAL ;
    PORT
      LAYER M4 ;
        RECT 356.3160 141.3120 356.4000 141.3360 ;
    END
  END hq_d[73]
  PIN hq_d[74]
    DIRECTION OUTPUT ;
    USE SIGNAL ;
    PORT
      LAYER M4 ;
        RECT 356.3160 141.6480 356.4000 141.6720 ;
    END
  END hq_d[74]
  PIN hq_d[75]
    DIRECTION OUTPUT ;
    USE SIGNAL ;
    PORT
      LAYER M4 ;
        RECT 356.3160 141.9840 356.4000 142.0080 ;
    END
  END hq_d[75]
  PIN hq_d[76]
    DIRECTION OUTPUT ;
    USE SIGNAL ;
    PORT
      LAYER M4 ;
        RECT 356.3160 142.3680 356.4000 142.3920 ;
    END
  END hq_d[76]
  PIN hq_d[77]
    DIRECTION OUTPUT ;
    USE SIGNAL ;
    PORT
      LAYER M4 ;
        RECT 356.3160 142.7040 356.4000 142.7280 ;
    END
  END hq_d[77]
  PIN hq_d[78]
    DIRECTION OUTPUT ;
    USE SIGNAL ;
    PORT
      LAYER M4 ;
        RECT 356.3160 143.0400 356.4000 143.0640 ;
    END
  END hq_d[78]
  PIN hq_d[79]
    DIRECTION OUTPUT ;
    USE SIGNAL ;
    PORT
      LAYER M4 ;
        RECT 356.3160 143.4240 356.4000 143.4480 ;
    END
  END hq_d[79]
  PIN hq_d[7]
    DIRECTION OUTPUT ;
    USE SIGNAL ;
    PORT
      LAYER M4 ;
        RECT 356.3160 118.0800 356.4000 118.1040 ;
    END
  END hq_d[7]
  PIN hq_d[80]
    DIRECTION OUTPUT ;
    USE SIGNAL ;
    PORT
      LAYER M4 ;
        RECT 356.3160 143.7600 356.4000 143.7840 ;
    END
  END hq_d[80]
  PIN hq_d[81]
    DIRECTION OUTPUT ;
    USE SIGNAL ;
    PORT
      LAYER M4 ;
        RECT 356.3160 144.0960 356.4000 144.1200 ;
    END
  END hq_d[81]
  PIN hq_d[82]
    DIRECTION OUTPUT ;
    USE SIGNAL ;
    PORT
      LAYER M4 ;
        RECT 356.3160 144.4800 356.4000 144.5040 ;
    END
  END hq_d[82]
  PIN hq_d[83]
    DIRECTION OUTPUT ;
    USE SIGNAL ;
    PORT
      LAYER M4 ;
        RECT 356.3160 144.8160 356.4000 144.8400 ;
    END
  END hq_d[83]
  PIN hq_d[84]
    DIRECTION OUTPUT ;
    USE SIGNAL ;
    PORT
      LAYER M4 ;
        RECT 356.3160 145.1520 356.4000 145.1760 ;
    END
  END hq_d[84]
  PIN hq_d[85]
    DIRECTION OUTPUT ;
    USE SIGNAL ;
    PORT
      LAYER M4 ;
        RECT 356.3160 145.5360 356.4000 145.5600 ;
    END
  END hq_d[85]
  PIN hq_d[86]
    DIRECTION OUTPUT ;
    USE SIGNAL ;
    PORT
      LAYER M4 ;
        RECT 356.3160 145.8720 356.4000 145.8960 ;
    END
  END hq_d[86]
  PIN hq_d[87]
    DIRECTION OUTPUT ;
    USE SIGNAL ;
    PORT
      LAYER M4 ;
        RECT 356.3160 146.2080 356.4000 146.2320 ;
    END
  END hq_d[87]
  PIN hq_d[88]
    DIRECTION OUTPUT ;
    USE SIGNAL ;
    PORT
      LAYER M4 ;
        RECT 356.3160 146.5920 356.4000 146.6160 ;
    END
  END hq_d[88]
  PIN hq_d[89]
    DIRECTION OUTPUT ;
    USE SIGNAL ;
    PORT
      LAYER M4 ;
        RECT 356.3160 146.9280 356.4000 146.9520 ;
    END
  END hq_d[89]
  PIN hq_d[8]
    DIRECTION OUTPUT ;
    USE SIGNAL ;
    PORT
      LAYER M4 ;
        RECT 356.3160 118.4160 356.4000 118.4400 ;
    END
  END hq_d[8]
  PIN hq_d[90]
    DIRECTION OUTPUT ;
    USE SIGNAL ;
    PORT
      LAYER M4 ;
        RECT 356.3160 147.2640 356.4000 147.2880 ;
    END
  END hq_d[90]
  PIN hq_d[91]
    DIRECTION OUTPUT ;
    USE SIGNAL ;
    PORT
      LAYER M4 ;
        RECT 356.3160 147.6480 356.4000 147.6720 ;
    END
  END hq_d[91]
  PIN hq_d[92]
    DIRECTION OUTPUT ;
    USE SIGNAL ;
    PORT
      LAYER M4 ;
        RECT 356.3160 147.9840 356.4000 148.0080 ;
    END
  END hq_d[92]
  PIN hq_d[93]
    DIRECTION OUTPUT ;
    USE SIGNAL ;
    PORT
      LAYER M4 ;
        RECT 356.3160 148.3200 356.4000 148.3440 ;
    END
  END hq_d[93]
  PIN hq_d[94]
    DIRECTION OUTPUT ;
    USE SIGNAL ;
    PORT
      LAYER M4 ;
        RECT 356.3160 148.7040 356.4000 148.7280 ;
    END
  END hq_d[94]
  PIN hq_d[95]
    DIRECTION OUTPUT ;
    USE SIGNAL ;
    PORT
      LAYER M4 ;
        RECT 356.3160 149.0400 356.4000 149.0640 ;
    END
  END hq_d[95]
  PIN hq_d[96]
    DIRECTION OUTPUT ;
    USE SIGNAL ;
    PORT
      LAYER M4 ;
        RECT 356.3160 149.3760 356.4000 149.4000 ;
    END
  END hq_d[96]
  PIN hq_d[97]
    DIRECTION OUTPUT ;
    USE SIGNAL ;
    PORT
      LAYER M4 ;
        RECT 356.3160 149.7600 356.4000 149.7840 ;
    END
  END hq_d[97]
  PIN hq_d[98]
    DIRECTION OUTPUT ;
    USE SIGNAL ;
    PORT
      LAYER M4 ;
        RECT 356.3160 150.0960 356.4000 150.1200 ;
    END
  END hq_d[98]
  PIN hq_d[99]
    DIRECTION OUTPUT ;
    USE SIGNAL ;
    PORT
      LAYER M4 ;
        RECT 356.3160 150.4320 356.4000 150.4560 ;
    END
  END hq_d[99]
  PIN hq_d[9]
    DIRECTION OUTPUT ;
    USE SIGNAL ;
    PORT
      LAYER M4 ;
        RECT 356.3160 118.8000 356.4000 118.8240 ;
    END
  END hq_d[9]
  PIN hq_v
    DIRECTION OUTPUT ;
    USE SIGNAL ;
    PORT
      LAYER M4 ;
        RECT 355.1240 114.1920 355.2080 114.2160 ;
    END
  END hq_v
  PIN hr_hf
    DIRECTION INPUT ;
    USE SIGNAL ;
    PORT
      LAYER M4 ;
        RECT 355.1240 111.6960 355.2080 111.7200 ;
    END
  END hr_hf
  PIN hr_j[0]
    DIRECTION INPUT ;
    USE SIGNAL ;
    PORT
      LAYER M4 ;
        RECT 356.3160 107.7600 356.4000 107.7840 ;
    END
  END hr_j[0]
  PIN hr_j[1]
    DIRECTION INPUT ;
    USE SIGNAL ;
    PORT
      LAYER M4 ;
        RECT 356.3160 108.8640 356.4000 108.8880 ;
    END
  END hr_j[1]
  PIN hr_j[2]
    DIRECTION INPUT ;
    USE SIGNAL ;
    PORT
      LAYER M4 ;
        RECT 356.3160 109.9200 356.4000 109.9440 ;
    END
  END hr_j[2]
  PIN hr_v
    DIRECTION INPUT ;
    USE SIGNAL ;
    PORT
      LAYER M4 ;
        RECT 355.1240 105.9840 355.2080 106.0080 ;
    END
  END hr_v
  PIN hw_d[0]
    DIRECTION INPUT ;
    USE SIGNAL ;
    PORT
      LAYER M4 ;
        RECT 356.3160 14.8320 356.4000 14.8560 ;
    END
  END hw_d[0]
  PIN hw_d[100]
    DIRECTION INPUT ;
    USE SIGNAL ;
    PORT
      LAYER M4 ;
        RECT 356.3160 50.0160 356.4000 50.0400 ;
    END
  END hw_d[100]
  PIN hw_d[101]
    DIRECTION INPUT ;
    USE SIGNAL ;
    PORT
      LAYER M4 ;
        RECT 356.3160 50.4000 356.4000 50.4240 ;
    END
  END hw_d[101]
  PIN hw_d[102]
    DIRECTION INPUT ;
    USE SIGNAL ;
    PORT
      LAYER M4 ;
        RECT 356.3160 50.7360 356.4000 50.7600 ;
    END
  END hw_d[102]
  PIN hw_d[103]
    DIRECTION INPUT ;
    USE SIGNAL ;
    PORT
      LAYER M4 ;
        RECT 356.3160 51.0720 356.4000 51.0960 ;
    END
  END hw_d[103]
  PIN hw_d[104]
    DIRECTION INPUT ;
    USE SIGNAL ;
    PORT
      LAYER M4 ;
        RECT 356.3160 51.4560 356.4000 51.4800 ;
    END
  END hw_d[104]
  PIN hw_d[105]
    DIRECTION INPUT ;
    USE SIGNAL ;
    PORT
      LAYER M4 ;
        RECT 356.3160 51.7920 356.4000 51.8160 ;
    END
  END hw_d[105]
  PIN hw_d[106]
    DIRECTION INPUT ;
    USE SIGNAL ;
    PORT
      LAYER M4 ;
        RECT 356.3160 52.1280 356.4000 52.1520 ;
    END
  END hw_d[106]
  PIN hw_d[107]
    DIRECTION INPUT ;
    USE SIGNAL ;
    PORT
      LAYER M4 ;
        RECT 356.3160 52.5120 356.4000 52.5360 ;
    END
  END hw_d[107]
  PIN hw_d[108]
    DIRECTION INPUT ;
    USE SIGNAL ;
    PORT
      LAYER M4 ;
        RECT 356.3160 52.8480 356.4000 52.8720 ;
    END
  END hw_d[108]
  PIN hw_d[109]
    DIRECTION INPUT ;
    USE SIGNAL ;
    PORT
      LAYER M4 ;
        RECT 356.3160 53.1840 356.4000 53.2080 ;
    END
  END hw_d[109]
  PIN hw_d[10]
    DIRECTION INPUT ;
    USE SIGNAL ;
    PORT
      LAYER M4 ;
        RECT 356.3160 18.3840 356.4000 18.4080 ;
    END
  END hw_d[10]
  PIN hw_d[110]
    DIRECTION INPUT ;
    USE SIGNAL ;
    PORT
      LAYER M4 ;
        RECT 356.3160 53.5680 356.4000 53.5920 ;
    END
  END hw_d[110]
  PIN hw_d[111]
    DIRECTION INPUT ;
    USE SIGNAL ;
    PORT
      LAYER M4 ;
        RECT 356.3160 53.9040 356.4000 53.9280 ;
    END
  END hw_d[111]
  PIN hw_d[112]
    DIRECTION INPUT ;
    USE SIGNAL ;
    PORT
      LAYER M4 ;
        RECT 356.3160 54.2400 356.4000 54.2640 ;
    END
  END hw_d[112]
  PIN hw_d[113]
    DIRECTION INPUT ;
    USE SIGNAL ;
    PORT
      LAYER M4 ;
        RECT 356.3160 54.6240 356.4000 54.6480 ;
    END
  END hw_d[113]
  PIN hw_d[114]
    DIRECTION INPUT ;
    USE SIGNAL ;
    PORT
      LAYER M4 ;
        RECT 356.3160 54.9600 356.4000 54.9840 ;
    END
  END hw_d[114]
  PIN hw_d[115]
    DIRECTION INPUT ;
    USE SIGNAL ;
    PORT
      LAYER M4 ;
        RECT 356.3160 55.2960 356.4000 55.3200 ;
    END
  END hw_d[115]
  PIN hw_d[116]
    DIRECTION INPUT ;
    USE SIGNAL ;
    PORT
      LAYER M4 ;
        RECT 356.3160 55.6800 356.4000 55.7040 ;
    END
  END hw_d[116]
  PIN hw_d[117]
    DIRECTION INPUT ;
    USE SIGNAL ;
    PORT
      LAYER M4 ;
        RECT 356.3160 56.0160 356.4000 56.0400 ;
    END
  END hw_d[117]
  PIN hw_d[118]
    DIRECTION INPUT ;
    USE SIGNAL ;
    PORT
      LAYER M4 ;
        RECT 356.3160 56.3520 356.4000 56.3760 ;
    END
  END hw_d[118]
  PIN hw_d[119]
    DIRECTION INPUT ;
    USE SIGNAL ;
    PORT
      LAYER M4 ;
        RECT 356.3160 56.7360 356.4000 56.7600 ;
    END
  END hw_d[119]
  PIN hw_d[11]
    DIRECTION INPUT ;
    USE SIGNAL ;
    PORT
      LAYER M4 ;
        RECT 356.3160 18.7200 356.4000 18.7440 ;
    END
  END hw_d[11]
  PIN hw_d[120]
    DIRECTION INPUT ;
    USE SIGNAL ;
    PORT
      LAYER M4 ;
        RECT 356.3160 57.0720 356.4000 57.0960 ;
    END
  END hw_d[120]
  PIN hw_d[121]
    DIRECTION INPUT ;
    USE SIGNAL ;
    PORT
      LAYER M4 ;
        RECT 356.3160 57.4080 356.4000 57.4320 ;
    END
  END hw_d[121]
  PIN hw_d[122]
    DIRECTION INPUT ;
    USE SIGNAL ;
    PORT
      LAYER M4 ;
        RECT 356.3160 57.7920 356.4000 57.8160 ;
    END
  END hw_d[122]
  PIN hw_d[123]
    DIRECTION INPUT ;
    USE SIGNAL ;
    PORT
      LAYER M4 ;
        RECT 356.3160 58.1280 356.4000 58.1520 ;
    END
  END hw_d[123]
  PIN hw_d[124]
    DIRECTION INPUT ;
    USE SIGNAL ;
    PORT
      LAYER M4 ;
        RECT 356.3160 58.4640 356.4000 58.4880 ;
    END
  END hw_d[124]
  PIN hw_d[125]
    DIRECTION INPUT ;
    USE SIGNAL ;
    PORT
      LAYER M4 ;
        RECT 356.3160 58.8000 356.4000 58.8240 ;
    END
  END hw_d[125]
  PIN hw_d[126]
    DIRECTION INPUT ;
    USE SIGNAL ;
    PORT
      LAYER M4 ;
        RECT 356.3160 59.1840 356.4000 59.2080 ;
    END
  END hw_d[126]
  PIN hw_d[127]
    DIRECTION INPUT ;
    USE SIGNAL ;
    PORT
      LAYER M4 ;
        RECT 356.3160 59.5200 356.4000 59.5440 ;
    END
  END hw_d[127]
  PIN hw_d[128]
    DIRECTION INPUT ;
    USE SIGNAL ;
    PORT
      LAYER M4 ;
        RECT 356.3160 59.8560 356.4000 59.8800 ;
    END
  END hw_d[128]
  PIN hw_d[129]
    DIRECTION INPUT ;
    USE SIGNAL ;
    PORT
      LAYER M4 ;
        RECT 356.3160 60.2400 356.4000 60.2640 ;
    END
  END hw_d[129]
  PIN hw_d[12]
    DIRECTION INPUT ;
    USE SIGNAL ;
    PORT
      LAYER M4 ;
        RECT 356.3160 19.0560 356.4000 19.0800 ;
    END
  END hw_d[12]
  PIN hw_d[130]
    DIRECTION INPUT ;
    USE SIGNAL ;
    PORT
      LAYER M4 ;
        RECT 356.3160 60.5760 356.4000 60.6000 ;
    END
  END hw_d[130]
  PIN hw_d[131]
    DIRECTION INPUT ;
    USE SIGNAL ;
    PORT
      LAYER M4 ;
        RECT 356.3160 60.9120 356.4000 60.9360 ;
    END
  END hw_d[131]
  PIN hw_d[132]
    DIRECTION INPUT ;
    USE SIGNAL ;
    PORT
      LAYER M4 ;
        RECT 356.3160 61.2960 356.4000 61.3200 ;
    END
  END hw_d[132]
  PIN hw_d[133]
    DIRECTION INPUT ;
    USE SIGNAL ;
    PORT
      LAYER M4 ;
        RECT 356.3160 61.6320 356.4000 61.6560 ;
    END
  END hw_d[133]
  PIN hw_d[134]
    DIRECTION INPUT ;
    USE SIGNAL ;
    PORT
      LAYER M4 ;
        RECT 356.3160 61.9680 356.4000 61.9920 ;
    END
  END hw_d[134]
  PIN hw_d[135]
    DIRECTION INPUT ;
    USE SIGNAL ;
    PORT
      LAYER M4 ;
        RECT 356.3160 62.3520 356.4000 62.3760 ;
    END
  END hw_d[135]
  PIN hw_d[136]
    DIRECTION INPUT ;
    USE SIGNAL ;
    PORT
      LAYER M4 ;
        RECT 356.3160 62.6880 356.4000 62.7120 ;
    END
  END hw_d[136]
  PIN hw_d[137]
    DIRECTION INPUT ;
    USE SIGNAL ;
    PORT
      LAYER M4 ;
        RECT 356.3160 63.0240 356.4000 63.0480 ;
    END
  END hw_d[137]
  PIN hw_d[138]
    DIRECTION INPUT ;
    USE SIGNAL ;
    PORT
      LAYER M4 ;
        RECT 356.3160 63.4080 356.4000 63.4320 ;
    END
  END hw_d[138]
  PIN hw_d[139]
    DIRECTION INPUT ;
    USE SIGNAL ;
    PORT
      LAYER M4 ;
        RECT 356.3160 63.7440 356.4000 63.7680 ;
    END
  END hw_d[139]
  PIN hw_d[13]
    DIRECTION INPUT ;
    USE SIGNAL ;
    PORT
      LAYER M4 ;
        RECT 356.3160 19.3920 356.4000 19.4160 ;
    END
  END hw_d[13]
  PIN hw_d[140]
    DIRECTION INPUT ;
    USE SIGNAL ;
    PORT
      LAYER M4 ;
        RECT 356.3160 64.0800 356.4000 64.1040 ;
    END
  END hw_d[140]
  PIN hw_d[141]
    DIRECTION INPUT ;
    USE SIGNAL ;
    PORT
      LAYER M4 ;
        RECT 356.3160 64.4640 356.4000 64.4880 ;
    END
  END hw_d[141]
  PIN hw_d[142]
    DIRECTION INPUT ;
    USE SIGNAL ;
    PORT
      LAYER M4 ;
        RECT 356.3160 64.8000 356.4000 64.8240 ;
    END
  END hw_d[142]
  PIN hw_d[143]
    DIRECTION INPUT ;
    USE SIGNAL ;
    PORT
      LAYER M4 ;
        RECT 356.3160 65.1360 356.4000 65.1600 ;
    END
  END hw_d[143]
  PIN hw_d[144]
    DIRECTION INPUT ;
    USE SIGNAL ;
    PORT
      LAYER M4 ;
        RECT 356.3160 65.5200 356.4000 65.5440 ;
    END
  END hw_d[144]
  PIN hw_d[145]
    DIRECTION INPUT ;
    USE SIGNAL ;
    PORT
      LAYER M4 ;
        RECT 356.3160 65.8560 356.4000 65.8800 ;
    END
  END hw_d[145]
  PIN hw_d[146]
    DIRECTION INPUT ;
    USE SIGNAL ;
    PORT
      LAYER M4 ;
        RECT 356.3160 66.1920 356.4000 66.2160 ;
    END
  END hw_d[146]
  PIN hw_d[147]
    DIRECTION INPUT ;
    USE SIGNAL ;
    PORT
      LAYER M4 ;
        RECT 356.3160 66.5760 356.4000 66.6000 ;
    END
  END hw_d[147]
  PIN hw_d[148]
    DIRECTION INPUT ;
    USE SIGNAL ;
    PORT
      LAYER M4 ;
        RECT 356.3160 66.9120 356.4000 66.9360 ;
    END
  END hw_d[148]
  PIN hw_d[149]
    DIRECTION INPUT ;
    USE SIGNAL ;
    PORT
      LAYER M4 ;
        RECT 356.3160 67.2480 356.4000 67.2720 ;
    END
  END hw_d[149]
  PIN hw_d[14]
    DIRECTION INPUT ;
    USE SIGNAL ;
    PORT
      LAYER M4 ;
        RECT 356.3160 19.7760 356.4000 19.8000 ;
    END
  END hw_d[14]
  PIN hw_d[150]
    DIRECTION INPUT ;
    USE SIGNAL ;
    PORT
      LAYER M4 ;
        RECT 356.3160 67.6320 356.4000 67.6560 ;
    END
  END hw_d[150]
  PIN hw_d[151]
    DIRECTION INPUT ;
    USE SIGNAL ;
    PORT
      LAYER M4 ;
        RECT 356.3160 67.9680 356.4000 67.9920 ;
    END
  END hw_d[151]
  PIN hw_d[152]
    DIRECTION INPUT ;
    USE SIGNAL ;
    PORT
      LAYER M4 ;
        RECT 356.3160 68.3040 356.4000 68.3280 ;
    END
  END hw_d[152]
  PIN hw_d[153]
    DIRECTION INPUT ;
    USE SIGNAL ;
    PORT
      LAYER M4 ;
        RECT 356.3160 68.6880 356.4000 68.7120 ;
    END
  END hw_d[153]
  PIN hw_d[154]
    DIRECTION INPUT ;
    USE SIGNAL ;
    PORT
      LAYER M4 ;
        RECT 356.3160 69.0240 356.4000 69.0480 ;
    END
  END hw_d[154]
  PIN hw_d[155]
    DIRECTION INPUT ;
    USE SIGNAL ;
    PORT
      LAYER M4 ;
        RECT 356.3160 69.3600 356.4000 69.3840 ;
    END
  END hw_d[155]
  PIN hw_d[156]
    DIRECTION INPUT ;
    USE SIGNAL ;
    PORT
      LAYER M4 ;
        RECT 356.3160 69.7440 356.4000 69.7680 ;
    END
  END hw_d[156]
  PIN hw_d[157]
    DIRECTION INPUT ;
    USE SIGNAL ;
    PORT
      LAYER M4 ;
        RECT 356.3160 70.0800 356.4000 70.1040 ;
    END
  END hw_d[157]
  PIN hw_d[158]
    DIRECTION INPUT ;
    USE SIGNAL ;
    PORT
      LAYER M4 ;
        RECT 356.3160 70.4160 356.4000 70.4400 ;
    END
  END hw_d[158]
  PIN hw_d[159]
    DIRECTION INPUT ;
    USE SIGNAL ;
    PORT
      LAYER M4 ;
        RECT 356.3160 70.8000 356.4000 70.8240 ;
    END
  END hw_d[159]
  PIN hw_d[15]
    DIRECTION INPUT ;
    USE SIGNAL ;
    PORT
      LAYER M4 ;
        RECT 356.3160 20.1120 356.4000 20.1360 ;
    END
  END hw_d[15]
  PIN hw_d[160]
    DIRECTION INPUT ;
    USE SIGNAL ;
    PORT
      LAYER M4 ;
        RECT 356.3160 71.1360 356.4000 71.1600 ;
    END
  END hw_d[160]
  PIN hw_d[161]
    DIRECTION INPUT ;
    USE SIGNAL ;
    PORT
      LAYER M4 ;
        RECT 356.3160 71.4720 356.4000 71.4960 ;
    END
  END hw_d[161]
  PIN hw_d[162]
    DIRECTION INPUT ;
    USE SIGNAL ;
    PORT
      LAYER M4 ;
        RECT 356.3160 71.8560 356.4000 71.8800 ;
    END
  END hw_d[162]
  PIN hw_d[163]
    DIRECTION INPUT ;
    USE SIGNAL ;
    PORT
      LAYER M4 ;
        RECT 356.3160 72.1920 356.4000 72.2160 ;
    END
  END hw_d[163]
  PIN hw_d[164]
    DIRECTION INPUT ;
    USE SIGNAL ;
    PORT
      LAYER M4 ;
        RECT 356.3160 72.5280 356.4000 72.5520 ;
    END
  END hw_d[164]
  PIN hw_d[165]
    DIRECTION INPUT ;
    USE SIGNAL ;
    PORT
      LAYER M4 ;
        RECT 356.3160 72.9120 356.4000 72.9360 ;
    END
  END hw_d[165]
  PIN hw_d[166]
    DIRECTION INPUT ;
    USE SIGNAL ;
    PORT
      LAYER M4 ;
        RECT 356.3160 73.2480 356.4000 73.2720 ;
    END
  END hw_d[166]
  PIN hw_d[167]
    DIRECTION INPUT ;
    USE SIGNAL ;
    PORT
      LAYER M4 ;
        RECT 356.3160 73.5840 356.4000 73.6080 ;
    END
  END hw_d[167]
  PIN hw_d[168]
    DIRECTION INPUT ;
    USE SIGNAL ;
    PORT
      LAYER M4 ;
        RECT 356.3160 73.9680 356.4000 73.9920 ;
    END
  END hw_d[168]
  PIN hw_d[169]
    DIRECTION INPUT ;
    USE SIGNAL ;
    PORT
      LAYER M4 ;
        RECT 356.3160 74.3040 356.4000 74.3280 ;
    END
  END hw_d[169]
  PIN hw_d[16]
    DIRECTION INPUT ;
    USE SIGNAL ;
    PORT
      LAYER M4 ;
        RECT 356.3160 20.4480 356.4000 20.4720 ;
    END
  END hw_d[16]
  PIN hw_d[170]
    DIRECTION INPUT ;
    USE SIGNAL ;
    PORT
      LAYER M4 ;
        RECT 356.3160 74.6400 356.4000 74.6640 ;
    END
  END hw_d[170]
  PIN hw_d[171]
    DIRECTION INPUT ;
    USE SIGNAL ;
    PORT
      LAYER M4 ;
        RECT 356.3160 75.0240 356.4000 75.0480 ;
    END
  END hw_d[171]
  PIN hw_d[172]
    DIRECTION INPUT ;
    USE SIGNAL ;
    PORT
      LAYER M4 ;
        RECT 356.3160 75.3600 356.4000 75.3840 ;
    END
  END hw_d[172]
  PIN hw_d[173]
    DIRECTION INPUT ;
    USE SIGNAL ;
    PORT
      LAYER M4 ;
        RECT 356.3160 75.6960 356.4000 75.7200 ;
    END
  END hw_d[173]
  PIN hw_d[174]
    DIRECTION INPUT ;
    USE SIGNAL ;
    PORT
      LAYER M4 ;
        RECT 356.3160 76.0800 356.4000 76.1040 ;
    END
  END hw_d[174]
  PIN hw_d[175]
    DIRECTION INPUT ;
    USE SIGNAL ;
    PORT
      LAYER M4 ;
        RECT 356.3160 76.4160 356.4000 76.4400 ;
    END
  END hw_d[175]
  PIN hw_d[176]
    DIRECTION INPUT ;
    USE SIGNAL ;
    PORT
      LAYER M4 ;
        RECT 356.3160 76.7520 356.4000 76.7760 ;
    END
  END hw_d[176]
  PIN hw_d[177]
    DIRECTION INPUT ;
    USE SIGNAL ;
    PORT
      LAYER M4 ;
        RECT 356.3160 77.1360 356.4000 77.1600 ;
    END
  END hw_d[177]
  PIN hw_d[178]
    DIRECTION INPUT ;
    USE SIGNAL ;
    PORT
      LAYER M4 ;
        RECT 356.3160 77.4720 356.4000 77.4960 ;
    END
  END hw_d[178]
  PIN hw_d[179]
    DIRECTION INPUT ;
    USE SIGNAL ;
    PORT
      LAYER M4 ;
        RECT 356.3160 77.8080 356.4000 77.8320 ;
    END
  END hw_d[179]
  PIN hw_d[17]
    DIRECTION INPUT ;
    USE SIGNAL ;
    PORT
      LAYER M4 ;
        RECT 356.3160 20.8320 356.4000 20.8560 ;
    END
  END hw_d[17]
  PIN hw_d[180]
    DIRECTION INPUT ;
    USE SIGNAL ;
    PORT
      LAYER M4 ;
        RECT 356.3160 78.1920 356.4000 78.2160 ;
    END
  END hw_d[180]
  PIN hw_d[181]
    DIRECTION INPUT ;
    USE SIGNAL ;
    PORT
      LAYER M4 ;
        RECT 356.3160 78.5280 356.4000 78.5520 ;
    END
  END hw_d[181]
  PIN hw_d[182]
    DIRECTION INPUT ;
    USE SIGNAL ;
    PORT
      LAYER M4 ;
        RECT 356.3160 78.8640 356.4000 78.8880 ;
    END
  END hw_d[182]
  PIN hw_d[183]
    DIRECTION INPUT ;
    USE SIGNAL ;
    PORT
      LAYER M4 ;
        RECT 356.3160 79.2480 356.4000 79.2720 ;
    END
  END hw_d[183]
  PIN hw_d[184]
    DIRECTION INPUT ;
    USE SIGNAL ;
    PORT
      LAYER M4 ;
        RECT 356.3160 79.5840 356.4000 79.6080 ;
    END
  END hw_d[184]
  PIN hw_d[185]
    DIRECTION INPUT ;
    USE SIGNAL ;
    PORT
      LAYER M4 ;
        RECT 356.3160 79.9200 356.4000 79.9440 ;
    END
  END hw_d[185]
  PIN hw_d[186]
    DIRECTION INPUT ;
    USE SIGNAL ;
    PORT
      LAYER M4 ;
        RECT 356.3160 80.3040 356.4000 80.3280 ;
    END
  END hw_d[186]
  PIN hw_d[187]
    DIRECTION INPUT ;
    USE SIGNAL ;
    PORT
      LAYER M4 ;
        RECT 356.3160 80.6400 356.4000 80.6640 ;
    END
  END hw_d[187]
  PIN hw_d[188]
    DIRECTION INPUT ;
    USE SIGNAL ;
    PORT
      LAYER M4 ;
        RECT 356.3160 80.9760 356.4000 81.0000 ;
    END
  END hw_d[188]
  PIN hw_d[189]
    DIRECTION INPUT ;
    USE SIGNAL ;
    PORT
      LAYER M4 ;
        RECT 356.3160 81.3600 356.4000 81.3840 ;
    END
  END hw_d[189]
  PIN hw_d[18]
    DIRECTION INPUT ;
    USE SIGNAL ;
    PORT
      LAYER M4 ;
        RECT 356.3160 21.1680 356.4000 21.1920 ;
    END
  END hw_d[18]
  PIN hw_d[190]
    DIRECTION INPUT ;
    USE SIGNAL ;
    PORT
      LAYER M4 ;
        RECT 356.3160 81.6960 356.4000 81.7200 ;
    END
  END hw_d[190]
  PIN hw_d[191]
    DIRECTION INPUT ;
    USE SIGNAL ;
    PORT
      LAYER M4 ;
        RECT 356.3160 82.0320 356.4000 82.0560 ;
    END
  END hw_d[191]
  PIN hw_d[192]
    DIRECTION INPUT ;
    USE SIGNAL ;
    PORT
      LAYER M4 ;
        RECT 356.3160 82.4160 356.4000 82.4400 ;
    END
  END hw_d[192]
  PIN hw_d[193]
    DIRECTION INPUT ;
    USE SIGNAL ;
    PORT
      LAYER M4 ;
        RECT 356.3160 82.7520 356.4000 82.7760 ;
    END
  END hw_d[193]
  PIN hw_d[194]
    DIRECTION INPUT ;
    USE SIGNAL ;
    PORT
      LAYER M4 ;
        RECT 356.3160 83.0880 356.4000 83.1120 ;
    END
  END hw_d[194]
  PIN hw_d[195]
    DIRECTION INPUT ;
    USE SIGNAL ;
    PORT
      LAYER M4 ;
        RECT 356.3160 83.4720 356.4000 83.4960 ;
    END
  END hw_d[195]
  PIN hw_d[196]
    DIRECTION INPUT ;
    USE SIGNAL ;
    PORT
      LAYER M4 ;
        RECT 356.3160 83.8080 356.4000 83.8320 ;
    END
  END hw_d[196]
  PIN hw_d[197]
    DIRECTION INPUT ;
    USE SIGNAL ;
    PORT
      LAYER M4 ;
        RECT 356.3160 84.1440 356.4000 84.1680 ;
    END
  END hw_d[197]
  PIN hw_d[198]
    DIRECTION INPUT ;
    USE SIGNAL ;
    PORT
      LAYER M4 ;
        RECT 356.3160 84.5280 356.4000 84.5520 ;
    END
  END hw_d[198]
  PIN hw_d[199]
    DIRECTION INPUT ;
    USE SIGNAL ;
    PORT
      LAYER M4 ;
        RECT 356.3160 84.8640 356.4000 84.8880 ;
    END
  END hw_d[199]
  PIN hw_d[19]
    DIRECTION INPUT ;
    USE SIGNAL ;
    PORT
      LAYER M4 ;
        RECT 356.3160 21.5040 356.4000 21.5280 ;
    END
  END hw_d[19]
  PIN hw_d[1]
    DIRECTION INPUT ;
    USE SIGNAL ;
    PORT
      LAYER M4 ;
        RECT 356.3160 15.2160 356.4000 15.2400 ;
    END
  END hw_d[1]
  PIN hw_d[200]
    DIRECTION INPUT ;
    USE SIGNAL ;
    PORT
      LAYER M4 ;
        RECT 356.3160 85.2000 356.4000 85.2240 ;
    END
  END hw_d[200]
  PIN hw_d[201]
    DIRECTION INPUT ;
    USE SIGNAL ;
    PORT
      LAYER M4 ;
        RECT 356.3160 85.5840 356.4000 85.6080 ;
    END
  END hw_d[201]
  PIN hw_d[202]
    DIRECTION INPUT ;
    USE SIGNAL ;
    PORT
      LAYER M4 ;
        RECT 356.3160 85.9200 356.4000 85.9440 ;
    END
  END hw_d[202]
  PIN hw_d[203]
    DIRECTION INPUT ;
    USE SIGNAL ;
    PORT
      LAYER M4 ;
        RECT 356.3160 86.2560 356.4000 86.2800 ;
    END
  END hw_d[203]
  PIN hw_d[204]
    DIRECTION INPUT ;
    USE SIGNAL ;
    PORT
      LAYER M4 ;
        RECT 356.3160 86.6400 356.4000 86.6640 ;
    END
  END hw_d[204]
  PIN hw_d[205]
    DIRECTION INPUT ;
    USE SIGNAL ;
    PORT
      LAYER M4 ;
        RECT 356.3160 86.9760 356.4000 87.0000 ;
    END
  END hw_d[205]
  PIN hw_d[206]
    DIRECTION INPUT ;
    USE SIGNAL ;
    PORT
      LAYER M4 ;
        RECT 356.3160 87.3120 356.4000 87.3360 ;
    END
  END hw_d[206]
  PIN hw_d[207]
    DIRECTION INPUT ;
    USE SIGNAL ;
    PORT
      LAYER M4 ;
        RECT 356.3160 87.6960 356.4000 87.7200 ;
    END
  END hw_d[207]
  PIN hw_d[208]
    DIRECTION INPUT ;
    USE SIGNAL ;
    PORT
      LAYER M4 ;
        RECT 356.3160 88.0320 356.4000 88.0560 ;
    END
  END hw_d[208]
  PIN hw_d[209]
    DIRECTION INPUT ;
    USE SIGNAL ;
    PORT
      LAYER M4 ;
        RECT 356.3160 88.3680 356.4000 88.3920 ;
    END
  END hw_d[209]
  PIN hw_d[20]
    DIRECTION INPUT ;
    USE SIGNAL ;
    PORT
      LAYER M4 ;
        RECT 356.3160 21.8880 356.4000 21.9120 ;
    END
  END hw_d[20]
  PIN hw_d[210]
    DIRECTION INPUT ;
    USE SIGNAL ;
    PORT
      LAYER M4 ;
        RECT 356.3160 88.7520 356.4000 88.7760 ;
    END
  END hw_d[210]
  PIN hw_d[211]
    DIRECTION INPUT ;
    USE SIGNAL ;
    PORT
      LAYER M4 ;
        RECT 356.3160 89.0880 356.4000 89.1120 ;
    END
  END hw_d[211]
  PIN hw_d[212]
    DIRECTION INPUT ;
    USE SIGNAL ;
    PORT
      LAYER M4 ;
        RECT 356.3160 89.4240 356.4000 89.4480 ;
    END
  END hw_d[212]
  PIN hw_d[213]
    DIRECTION INPUT ;
    USE SIGNAL ;
    PORT
      LAYER M4 ;
        RECT 356.3160 89.8080 356.4000 89.8320 ;
    END
  END hw_d[213]
  PIN hw_d[214]
    DIRECTION INPUT ;
    USE SIGNAL ;
    PORT
      LAYER M4 ;
        RECT 356.3160 90.1440 356.4000 90.1680 ;
    END
  END hw_d[214]
  PIN hw_d[215]
    DIRECTION INPUT ;
    USE SIGNAL ;
    PORT
      LAYER M4 ;
        RECT 356.3160 90.4800 356.4000 90.5040 ;
    END
  END hw_d[215]
  PIN hw_d[216]
    DIRECTION INPUT ;
    USE SIGNAL ;
    PORT
      LAYER M4 ;
        RECT 356.3160 90.8640 356.4000 90.8880 ;
    END
  END hw_d[216]
  PIN hw_d[217]
    DIRECTION INPUT ;
    USE SIGNAL ;
    PORT
      LAYER M4 ;
        RECT 356.3160 91.2000 356.4000 91.2240 ;
    END
  END hw_d[217]
  PIN hw_d[218]
    DIRECTION INPUT ;
    USE SIGNAL ;
    PORT
      LAYER M4 ;
        RECT 356.3160 91.5360 356.4000 91.5600 ;
    END
  END hw_d[218]
  PIN hw_d[219]
    DIRECTION INPUT ;
    USE SIGNAL ;
    PORT
      LAYER M4 ;
        RECT 356.3160 91.9200 356.4000 91.9440 ;
    END
  END hw_d[219]
  PIN hw_d[21]
    DIRECTION INPUT ;
    USE SIGNAL ;
    PORT
      LAYER M4 ;
        RECT 356.3160 22.2240 356.4000 22.2480 ;
    END
  END hw_d[21]
  PIN hw_d[220]
    DIRECTION INPUT ;
    USE SIGNAL ;
    PORT
      LAYER M4 ;
        RECT 356.3160 92.2560 356.4000 92.2800 ;
    END
  END hw_d[220]
  PIN hw_d[221]
    DIRECTION INPUT ;
    USE SIGNAL ;
    PORT
      LAYER M4 ;
        RECT 356.3160 92.5920 356.4000 92.6160 ;
    END
  END hw_d[221]
  PIN hw_d[222]
    DIRECTION INPUT ;
    USE SIGNAL ;
    PORT
      LAYER M4 ;
        RECT 356.3160 92.9760 356.4000 93.0000 ;
    END
  END hw_d[222]
  PIN hw_d[223]
    DIRECTION INPUT ;
    USE SIGNAL ;
    PORT
      LAYER M4 ;
        RECT 356.3160 93.3120 356.4000 93.3360 ;
    END
  END hw_d[223]
  PIN hw_d[224]
    DIRECTION INPUT ;
    USE SIGNAL ;
    PORT
      LAYER M4 ;
        RECT 356.3160 93.6480 356.4000 93.6720 ;
    END
  END hw_d[224]
  PIN hw_d[225]
    DIRECTION INPUT ;
    USE SIGNAL ;
    PORT
      LAYER M4 ;
        RECT 356.3160 94.0320 356.4000 94.0560 ;
    END
  END hw_d[225]
  PIN hw_d[226]
    DIRECTION INPUT ;
    USE SIGNAL ;
    PORT
      LAYER M4 ;
        RECT 356.3160 94.3680 356.4000 94.3920 ;
    END
  END hw_d[226]
  PIN hw_d[227]
    DIRECTION INPUT ;
    USE SIGNAL ;
    PORT
      LAYER M4 ;
        RECT 356.3160 94.7040 356.4000 94.7280 ;
    END
  END hw_d[227]
  PIN hw_d[228]
    DIRECTION INPUT ;
    USE SIGNAL ;
    PORT
      LAYER M4 ;
        RECT 356.3160 95.0880 356.4000 95.1120 ;
    END
  END hw_d[228]
  PIN hw_d[229]
    DIRECTION INPUT ;
    USE SIGNAL ;
    PORT
      LAYER M4 ;
        RECT 356.3160 95.4240 356.4000 95.4480 ;
    END
  END hw_d[229]
  PIN hw_d[22]
    DIRECTION INPUT ;
    USE SIGNAL ;
    PORT
      LAYER M4 ;
        RECT 356.3160 22.5600 356.4000 22.5840 ;
    END
  END hw_d[22]
  PIN hw_d[230]
    DIRECTION INPUT ;
    USE SIGNAL ;
    PORT
      LAYER M4 ;
        RECT 356.3160 95.7600 356.4000 95.7840 ;
    END
  END hw_d[230]
  PIN hw_d[231]
    DIRECTION INPUT ;
    USE SIGNAL ;
    PORT
      LAYER M4 ;
        RECT 356.3160 96.1440 356.4000 96.1680 ;
    END
  END hw_d[231]
  PIN hw_d[232]
    DIRECTION INPUT ;
    USE SIGNAL ;
    PORT
      LAYER M4 ;
        RECT 356.3160 96.4800 356.4000 96.5040 ;
    END
  END hw_d[232]
  PIN hw_d[233]
    DIRECTION INPUT ;
    USE SIGNAL ;
    PORT
      LAYER M4 ;
        RECT 356.3160 96.8160 356.4000 96.8400 ;
    END
  END hw_d[233]
  PIN hw_d[234]
    DIRECTION INPUT ;
    USE SIGNAL ;
    PORT
      LAYER M4 ;
        RECT 356.3160 97.2000 356.4000 97.2240 ;
    END
  END hw_d[234]
  PIN hw_d[235]
    DIRECTION INPUT ;
    USE SIGNAL ;
    PORT
      LAYER M4 ;
        RECT 356.3160 97.5360 356.4000 97.5600 ;
    END
  END hw_d[235]
  PIN hw_d[236]
    DIRECTION INPUT ;
    USE SIGNAL ;
    PORT
      LAYER M4 ;
        RECT 356.3160 97.8720 356.4000 97.8960 ;
    END
  END hw_d[236]
  PIN hw_d[237]
    DIRECTION INPUT ;
    USE SIGNAL ;
    PORT
      LAYER M4 ;
        RECT 356.3160 98.2560 356.4000 98.2800 ;
    END
  END hw_d[237]
  PIN hw_d[238]
    DIRECTION INPUT ;
    USE SIGNAL ;
    PORT
      LAYER M4 ;
        RECT 356.3160 98.5920 356.4000 98.6160 ;
    END
  END hw_d[238]
  PIN hw_d[239]
    DIRECTION INPUT ;
    USE SIGNAL ;
    PORT
      LAYER M4 ;
        RECT 356.3160 98.9280 356.4000 98.9520 ;
    END
  END hw_d[239]
  PIN hw_d[23]
    DIRECTION INPUT ;
    USE SIGNAL ;
    PORT
      LAYER M4 ;
        RECT 356.3160 22.9440 356.4000 22.9680 ;
    END
  END hw_d[23]
  PIN hw_d[240]
    DIRECTION INPUT ;
    USE SIGNAL ;
    PORT
      LAYER M4 ;
        RECT 356.3160 99.2640 356.4000 99.2880 ;
    END
  END hw_d[240]
  PIN hw_d[241]
    DIRECTION INPUT ;
    USE SIGNAL ;
    PORT
      LAYER M4 ;
        RECT 356.3160 99.6480 356.4000 99.6720 ;
    END
  END hw_d[241]
  PIN hw_d[242]
    DIRECTION INPUT ;
    USE SIGNAL ;
    PORT
      LAYER M4 ;
        RECT 356.3160 99.9840 356.4000 100.0080 ;
    END
  END hw_d[242]
  PIN hw_d[243]
    DIRECTION INPUT ;
    USE SIGNAL ;
    PORT
      LAYER M4 ;
        RECT 356.3160 100.3200 356.4000 100.3440 ;
    END
  END hw_d[243]
  PIN hw_d[244]
    DIRECTION INPUT ;
    USE SIGNAL ;
    PORT
      LAYER M4 ;
        RECT 356.3160 100.7040 356.4000 100.7280 ;
    END
  END hw_d[244]
  PIN hw_d[245]
    DIRECTION INPUT ;
    USE SIGNAL ;
    PORT
      LAYER M4 ;
        RECT 356.3160 101.0400 356.4000 101.0640 ;
    END
  END hw_d[245]
  PIN hw_d[246]
    DIRECTION INPUT ;
    USE SIGNAL ;
    PORT
      LAYER M4 ;
        RECT 356.3160 101.3760 356.4000 101.4000 ;
    END
  END hw_d[246]
  PIN hw_d[247]
    DIRECTION INPUT ;
    USE SIGNAL ;
    PORT
      LAYER M4 ;
        RECT 356.3160 101.7600 356.4000 101.7840 ;
    END
  END hw_d[247]
  PIN hw_d[248]
    DIRECTION INPUT ;
    USE SIGNAL ;
    PORT
      LAYER M4 ;
        RECT 356.3160 102.0960 356.4000 102.1200 ;
    END
  END hw_d[248]
  PIN hw_d[249]
    DIRECTION INPUT ;
    USE SIGNAL ;
    PORT
      LAYER M4 ;
        RECT 356.3160 102.4320 356.4000 102.4560 ;
    END
  END hw_d[249]
  PIN hw_d[24]
    DIRECTION INPUT ;
    USE SIGNAL ;
    PORT
      LAYER M4 ;
        RECT 356.3160 23.2800 356.4000 23.3040 ;
    END
  END hw_d[24]
  PIN hw_d[250]
    DIRECTION INPUT ;
    USE SIGNAL ;
    PORT
      LAYER M4 ;
        RECT 356.3160 102.8160 356.4000 102.8400 ;
    END
  END hw_d[250]
  PIN hw_d[251]
    DIRECTION INPUT ;
    USE SIGNAL ;
    PORT
      LAYER M4 ;
        RECT 356.3160 103.1520 356.4000 103.1760 ;
    END
  END hw_d[251]
  PIN hw_d[252]
    DIRECTION INPUT ;
    USE SIGNAL ;
    PORT
      LAYER M4 ;
        RECT 356.3160 103.4880 356.4000 103.5120 ;
    END
  END hw_d[252]
  PIN hw_d[253]
    DIRECTION INPUT ;
    USE SIGNAL ;
    PORT
      LAYER M4 ;
        RECT 356.3160 103.8720 356.4000 103.8960 ;
    END
  END hw_d[253]
  PIN hw_d[254]
    DIRECTION INPUT ;
    USE SIGNAL ;
    PORT
      LAYER M4 ;
        RECT 356.3160 104.2080 356.4000 104.2320 ;
    END
  END hw_d[254]
  PIN hw_d[255]
    DIRECTION INPUT ;
    USE SIGNAL ;
    PORT
      LAYER M4 ;
        RECT 356.3160 104.5440 356.4000 104.5680 ;
    END
  END hw_d[255]
  PIN hw_d[25]
    DIRECTION INPUT ;
    USE SIGNAL ;
    PORT
      LAYER M4 ;
        RECT 356.3160 23.6160 356.4000 23.6400 ;
    END
  END hw_d[25]
  PIN hw_d[26]
    DIRECTION INPUT ;
    USE SIGNAL ;
    PORT
      LAYER M4 ;
        RECT 356.3160 24.0000 356.4000 24.0240 ;
    END
  END hw_d[26]
  PIN hw_d[27]
    DIRECTION INPUT ;
    USE SIGNAL ;
    PORT
      LAYER M4 ;
        RECT 356.3160 24.3360 356.4000 24.3600 ;
    END
  END hw_d[27]
  PIN hw_d[28]
    DIRECTION INPUT ;
    USE SIGNAL ;
    PORT
      LAYER M4 ;
        RECT 356.3160 24.6720 356.4000 24.6960 ;
    END
  END hw_d[28]
  PIN hw_d[29]
    DIRECTION INPUT ;
    USE SIGNAL ;
    PORT
      LAYER M4 ;
        RECT 356.3160 25.0560 356.4000 25.0800 ;
    END
  END hw_d[29]
  PIN hw_d[2]
    DIRECTION INPUT ;
    USE SIGNAL ;
    PORT
      LAYER M4 ;
        RECT 356.3160 15.5520 356.4000 15.5760 ;
    END
  END hw_d[2]
  PIN hw_d[30]
    DIRECTION INPUT ;
    USE SIGNAL ;
    PORT
      LAYER M4 ;
        RECT 356.3160 25.3920 356.4000 25.4160 ;
    END
  END hw_d[30]
  PIN hw_d[31]
    DIRECTION INPUT ;
    USE SIGNAL ;
    PORT
      LAYER M4 ;
        RECT 356.3160 25.7280 356.4000 25.7520 ;
    END
  END hw_d[31]
  PIN hw_d[32]
    DIRECTION INPUT ;
    USE SIGNAL ;
    PORT
      LAYER M4 ;
        RECT 356.3160 26.1120 356.4000 26.1360 ;
    END
  END hw_d[32]
  PIN hw_d[33]
    DIRECTION INPUT ;
    USE SIGNAL ;
    PORT
      LAYER M4 ;
        RECT 356.3160 26.4480 356.4000 26.4720 ;
    END
  END hw_d[33]
  PIN hw_d[34]
    DIRECTION INPUT ;
    USE SIGNAL ;
    PORT
      LAYER M4 ;
        RECT 356.3160 26.7840 356.4000 26.8080 ;
    END
  END hw_d[34]
  PIN hw_d[35]
    DIRECTION INPUT ;
    USE SIGNAL ;
    PORT
      LAYER M4 ;
        RECT 356.3160 27.1680 356.4000 27.1920 ;
    END
  END hw_d[35]
  PIN hw_d[36]
    DIRECTION INPUT ;
    USE SIGNAL ;
    PORT
      LAYER M4 ;
        RECT 356.3160 27.5040 356.4000 27.5280 ;
    END
  END hw_d[36]
  PIN hw_d[37]
    DIRECTION INPUT ;
    USE SIGNAL ;
    PORT
      LAYER M4 ;
        RECT 356.3160 27.8400 356.4000 27.8640 ;
    END
  END hw_d[37]
  PIN hw_d[38]
    DIRECTION INPUT ;
    USE SIGNAL ;
    PORT
      LAYER M4 ;
        RECT 356.3160 28.2240 356.4000 28.2480 ;
    END
  END hw_d[38]
  PIN hw_d[39]
    DIRECTION INPUT ;
    USE SIGNAL ;
    PORT
      LAYER M4 ;
        RECT 356.3160 28.5600 356.4000 28.5840 ;
    END
  END hw_d[39]
  PIN hw_d[3]
    DIRECTION INPUT ;
    USE SIGNAL ;
    PORT
      LAYER M4 ;
        RECT 356.3160 15.8880 356.4000 15.9120 ;
    END
  END hw_d[3]
  PIN hw_d[40]
    DIRECTION INPUT ;
    USE SIGNAL ;
    PORT
      LAYER M4 ;
        RECT 356.3160 28.8960 356.4000 28.9200 ;
    END
  END hw_d[40]
  PIN hw_d[41]
    DIRECTION INPUT ;
    USE SIGNAL ;
    PORT
      LAYER M4 ;
        RECT 356.3160 29.2800 356.4000 29.3040 ;
    END
  END hw_d[41]
  PIN hw_d[42]
    DIRECTION INPUT ;
    USE SIGNAL ;
    PORT
      LAYER M4 ;
        RECT 356.3160 29.6160 356.4000 29.6400 ;
    END
  END hw_d[42]
  PIN hw_d[43]
    DIRECTION INPUT ;
    USE SIGNAL ;
    PORT
      LAYER M4 ;
        RECT 356.3160 29.9520 356.4000 29.9760 ;
    END
  END hw_d[43]
  PIN hw_d[44]
    DIRECTION INPUT ;
    USE SIGNAL ;
    PORT
      LAYER M4 ;
        RECT 356.3160 30.3360 356.4000 30.3600 ;
    END
  END hw_d[44]
  PIN hw_d[45]
    DIRECTION INPUT ;
    USE SIGNAL ;
    PORT
      LAYER M4 ;
        RECT 356.3160 30.6720 356.4000 30.6960 ;
    END
  END hw_d[45]
  PIN hw_d[46]
    DIRECTION INPUT ;
    USE SIGNAL ;
    PORT
      LAYER M4 ;
        RECT 356.3160 31.0080 356.4000 31.0320 ;
    END
  END hw_d[46]
  PIN hw_d[47]
    DIRECTION INPUT ;
    USE SIGNAL ;
    PORT
      LAYER M4 ;
        RECT 356.3160 31.3920 356.4000 31.4160 ;
    END
  END hw_d[47]
  PIN hw_d[48]
    DIRECTION INPUT ;
    USE SIGNAL ;
    PORT
      LAYER M4 ;
        RECT 356.3160 31.7280 356.4000 31.7520 ;
    END
  END hw_d[48]
  PIN hw_d[49]
    DIRECTION INPUT ;
    USE SIGNAL ;
    PORT
      LAYER M4 ;
        RECT 356.3160 32.0640 356.4000 32.0880 ;
    END
  END hw_d[49]
  PIN hw_d[4]
    DIRECTION INPUT ;
    USE SIGNAL ;
    PORT
      LAYER M4 ;
        RECT 356.3160 16.2720 356.4000 16.2960 ;
    END
  END hw_d[4]
  PIN hw_d[50]
    DIRECTION INPUT ;
    USE SIGNAL ;
    PORT
      LAYER M4 ;
        RECT 356.3160 32.4480 356.4000 32.4720 ;
    END
  END hw_d[50]
  PIN hw_d[51]
    DIRECTION INPUT ;
    USE SIGNAL ;
    PORT
      LAYER M4 ;
        RECT 356.3160 32.7840 356.4000 32.8080 ;
    END
  END hw_d[51]
  PIN hw_d[52]
    DIRECTION INPUT ;
    USE SIGNAL ;
    PORT
      LAYER M4 ;
        RECT 356.3160 33.1200 356.4000 33.1440 ;
    END
  END hw_d[52]
  PIN hw_d[53]
    DIRECTION INPUT ;
    USE SIGNAL ;
    PORT
      LAYER M4 ;
        RECT 356.3160 33.5040 356.4000 33.5280 ;
    END
  END hw_d[53]
  PIN hw_d[54]
    DIRECTION INPUT ;
    USE SIGNAL ;
    PORT
      LAYER M4 ;
        RECT 356.3160 33.8400 356.4000 33.8640 ;
    END
  END hw_d[54]
  PIN hw_d[55]
    DIRECTION INPUT ;
    USE SIGNAL ;
    PORT
      LAYER M4 ;
        RECT 356.3160 34.1760 356.4000 34.2000 ;
    END
  END hw_d[55]
  PIN hw_d[56]
    DIRECTION INPUT ;
    USE SIGNAL ;
    PORT
      LAYER M4 ;
        RECT 356.3160 34.5600 356.4000 34.5840 ;
    END
  END hw_d[56]
  PIN hw_d[57]
    DIRECTION INPUT ;
    USE SIGNAL ;
    PORT
      LAYER M4 ;
        RECT 356.3160 34.8960 356.4000 34.9200 ;
    END
  END hw_d[57]
  PIN hw_d[58]
    DIRECTION INPUT ;
    USE SIGNAL ;
    PORT
      LAYER M4 ;
        RECT 356.3160 35.2320 356.4000 35.2560 ;
    END
  END hw_d[58]
  PIN hw_d[59]
    DIRECTION INPUT ;
    USE SIGNAL ;
    PORT
      LAYER M4 ;
        RECT 356.3160 35.6160 356.4000 35.6400 ;
    END
  END hw_d[59]
  PIN hw_d[5]
    DIRECTION INPUT ;
    USE SIGNAL ;
    PORT
      LAYER M4 ;
        RECT 356.3160 16.6080 356.4000 16.6320 ;
    END
  END hw_d[5]
  PIN hw_d[60]
    DIRECTION INPUT ;
    USE SIGNAL ;
    PORT
      LAYER M4 ;
        RECT 356.3160 35.9520 356.4000 35.9760 ;
    END
  END hw_d[60]
  PIN hw_d[61]
    DIRECTION INPUT ;
    USE SIGNAL ;
    PORT
      LAYER M4 ;
        RECT 356.3160 36.2880 356.4000 36.3120 ;
    END
  END hw_d[61]
  PIN hw_d[62]
    DIRECTION INPUT ;
    USE SIGNAL ;
    PORT
      LAYER M4 ;
        RECT 356.3160 36.6720 356.4000 36.6960 ;
    END
  END hw_d[62]
  PIN hw_d[63]
    DIRECTION INPUT ;
    USE SIGNAL ;
    PORT
      LAYER M4 ;
        RECT 356.3160 37.0080 356.4000 37.0320 ;
    END
  END hw_d[63]
  PIN hw_d[64]
    DIRECTION INPUT ;
    USE SIGNAL ;
    PORT
      LAYER M4 ;
        RECT 356.3160 37.3440 356.4000 37.3680 ;
    END
  END hw_d[64]
  PIN hw_d[65]
    DIRECTION INPUT ;
    USE SIGNAL ;
    PORT
      LAYER M4 ;
        RECT 356.3160 37.7280 356.4000 37.7520 ;
    END
  END hw_d[65]
  PIN hw_d[66]
    DIRECTION INPUT ;
    USE SIGNAL ;
    PORT
      LAYER M4 ;
        RECT 356.3160 38.0640 356.4000 38.0880 ;
    END
  END hw_d[66]
  PIN hw_d[67]
    DIRECTION INPUT ;
    USE SIGNAL ;
    PORT
      LAYER M4 ;
        RECT 356.3160 38.4000 356.4000 38.4240 ;
    END
  END hw_d[67]
  PIN hw_d[68]
    DIRECTION INPUT ;
    USE SIGNAL ;
    PORT
      LAYER M4 ;
        RECT 356.3160 38.7840 356.4000 38.8080 ;
    END
  END hw_d[68]
  PIN hw_d[69]
    DIRECTION INPUT ;
    USE SIGNAL ;
    PORT
      LAYER M4 ;
        RECT 356.3160 39.1200 356.4000 39.1440 ;
    END
  END hw_d[69]
  PIN hw_d[6]
    DIRECTION INPUT ;
    USE SIGNAL ;
    PORT
      LAYER M4 ;
        RECT 356.3160 16.9440 356.4000 16.9680 ;
    END
  END hw_d[6]
  PIN hw_d[70]
    DIRECTION INPUT ;
    USE SIGNAL ;
    PORT
      LAYER M4 ;
        RECT 356.3160 39.4560 356.4000 39.4800 ;
    END
  END hw_d[70]
  PIN hw_d[71]
    DIRECTION INPUT ;
    USE SIGNAL ;
    PORT
      LAYER M4 ;
        RECT 356.3160 39.8400 356.4000 39.8640 ;
    END
  END hw_d[71]
  PIN hw_d[72]
    DIRECTION INPUT ;
    USE SIGNAL ;
    PORT
      LAYER M4 ;
        RECT 356.3160 40.1760 356.4000 40.2000 ;
    END
  END hw_d[72]
  PIN hw_d[73]
    DIRECTION INPUT ;
    USE SIGNAL ;
    PORT
      LAYER M4 ;
        RECT 356.3160 40.5120 356.4000 40.5360 ;
    END
  END hw_d[73]
  PIN hw_d[74]
    DIRECTION INPUT ;
    USE SIGNAL ;
    PORT
      LAYER M4 ;
        RECT 356.3160 40.8960 356.4000 40.9200 ;
    END
  END hw_d[74]
  PIN hw_d[75]
    DIRECTION INPUT ;
    USE SIGNAL ;
    PORT
      LAYER M4 ;
        RECT 356.3160 41.2320 356.4000 41.2560 ;
    END
  END hw_d[75]
  PIN hw_d[76]
    DIRECTION INPUT ;
    USE SIGNAL ;
    PORT
      LAYER M4 ;
        RECT 356.3160 41.5680 356.4000 41.5920 ;
    END
  END hw_d[76]
  PIN hw_d[77]
    DIRECTION INPUT ;
    USE SIGNAL ;
    PORT
      LAYER M4 ;
        RECT 356.3160 41.9520 356.4000 41.9760 ;
    END
  END hw_d[77]
  PIN hw_d[78]
    DIRECTION INPUT ;
    USE SIGNAL ;
    PORT
      LAYER M4 ;
        RECT 356.3160 42.2880 356.4000 42.3120 ;
    END
  END hw_d[78]
  PIN hw_d[79]
    DIRECTION INPUT ;
    USE SIGNAL ;
    PORT
      LAYER M4 ;
        RECT 356.3160 42.6240 356.4000 42.6480 ;
    END
  END hw_d[79]
  PIN hw_d[7]
    DIRECTION INPUT ;
    USE SIGNAL ;
    PORT
      LAYER M4 ;
        RECT 356.3160 17.3280 356.4000 17.3520 ;
    END
  END hw_d[7]
  PIN hw_d[80]
    DIRECTION INPUT ;
    USE SIGNAL ;
    PORT
      LAYER M4 ;
        RECT 356.3160 43.0080 356.4000 43.0320 ;
    END
  END hw_d[80]
  PIN hw_d[81]
    DIRECTION INPUT ;
    USE SIGNAL ;
    PORT
      LAYER M4 ;
        RECT 356.3160 43.3440 356.4000 43.3680 ;
    END
  END hw_d[81]
  PIN hw_d[82]
    DIRECTION INPUT ;
    USE SIGNAL ;
    PORT
      LAYER M4 ;
        RECT 356.3160 43.6800 356.4000 43.7040 ;
    END
  END hw_d[82]
  PIN hw_d[83]
    DIRECTION INPUT ;
    USE SIGNAL ;
    PORT
      LAYER M4 ;
        RECT 356.3160 44.0640 356.4000 44.0880 ;
    END
  END hw_d[83]
  PIN hw_d[84]
    DIRECTION INPUT ;
    USE SIGNAL ;
    PORT
      LAYER M4 ;
        RECT 356.3160 44.4000 356.4000 44.4240 ;
    END
  END hw_d[84]
  PIN hw_d[85]
    DIRECTION INPUT ;
    USE SIGNAL ;
    PORT
      LAYER M4 ;
        RECT 356.3160 44.7360 356.4000 44.7600 ;
    END
  END hw_d[85]
  PIN hw_d[86]
    DIRECTION INPUT ;
    USE SIGNAL ;
    PORT
      LAYER M4 ;
        RECT 356.3160 45.1200 356.4000 45.1440 ;
    END
  END hw_d[86]
  PIN hw_d[87]
    DIRECTION INPUT ;
    USE SIGNAL ;
    PORT
      LAYER M4 ;
        RECT 356.3160 45.4560 356.4000 45.4800 ;
    END
  END hw_d[87]
  PIN hw_d[88]
    DIRECTION INPUT ;
    USE SIGNAL ;
    PORT
      LAYER M4 ;
        RECT 356.3160 45.7920 356.4000 45.8160 ;
    END
  END hw_d[88]
  PIN hw_d[89]
    DIRECTION INPUT ;
    USE SIGNAL ;
    PORT
      LAYER M4 ;
        RECT 356.3160 46.1760 356.4000 46.2000 ;
    END
  END hw_d[89]
  PIN hw_d[8]
    DIRECTION INPUT ;
    USE SIGNAL ;
    PORT
      LAYER M4 ;
        RECT 356.3160 17.6640 356.4000 17.6880 ;
    END
  END hw_d[8]
  PIN hw_d[90]
    DIRECTION INPUT ;
    USE SIGNAL ;
    PORT
      LAYER M4 ;
        RECT 356.3160 46.5120 356.4000 46.5360 ;
    END
  END hw_d[90]
  PIN hw_d[91]
    DIRECTION INPUT ;
    USE SIGNAL ;
    PORT
      LAYER M4 ;
        RECT 356.3160 46.8480 356.4000 46.8720 ;
    END
  END hw_d[91]
  PIN hw_d[92]
    DIRECTION INPUT ;
    USE SIGNAL ;
    PORT
      LAYER M4 ;
        RECT 356.3160 47.2320 356.4000 47.2560 ;
    END
  END hw_d[92]
  PIN hw_d[93]
    DIRECTION INPUT ;
    USE SIGNAL ;
    PORT
      LAYER M4 ;
        RECT 356.3160 47.5680 356.4000 47.5920 ;
    END
  END hw_d[93]
  PIN hw_d[94]
    DIRECTION INPUT ;
    USE SIGNAL ;
    PORT
      LAYER M4 ;
        RECT 356.3160 47.9040 356.4000 47.9280 ;
    END
  END hw_d[94]
  PIN hw_d[95]
    DIRECTION INPUT ;
    USE SIGNAL ;
    PORT
      LAYER M4 ;
        RECT 356.3160 48.2880 356.4000 48.3120 ;
    END
  END hw_d[95]
  PIN hw_d[96]
    DIRECTION INPUT ;
    USE SIGNAL ;
    PORT
      LAYER M4 ;
        RECT 356.3160 48.6240 356.4000 48.6480 ;
    END
  END hw_d[96]
  PIN hw_d[97]
    DIRECTION INPUT ;
    USE SIGNAL ;
    PORT
      LAYER M4 ;
        RECT 356.3160 48.9600 356.4000 48.9840 ;
    END
  END hw_d[97]
  PIN hw_d[98]
    DIRECTION INPUT ;
    USE SIGNAL ;
    PORT
      LAYER M4 ;
        RECT 356.3160 49.3440 356.4000 49.3680 ;
    END
  END hw_d[98]
  PIN hw_d[99]
    DIRECTION INPUT ;
    USE SIGNAL ;
    PORT
      LAYER M4 ;
        RECT 356.3160 49.6800 356.4000 49.7040 ;
    END
  END hw_d[99]
  PIN hw_d[9]
    DIRECTION INPUT ;
    USE SIGNAL ;
    PORT
      LAYER M4 ;
        RECT 356.3160 18.0000 356.4000 18.0240 ;
    END
  END hw_d[9]
  PIN hw_hf
    DIRECTION INPUT ;
    USE SIGNAL ;
    PORT
      LAYER M4 ;
        RECT 356.3160 13.3920 356.4000 13.4160 ;
    END
  END hw_hf
  PIN hw_j[0]
    DIRECTION INPUT ;
    USE SIGNAL ;
    PORT
      LAYER M4 ;
        RECT 355.1240 9.5040 355.2080 9.5280 ;
    END
  END hw_j[0]
  PIN hw_j[1]
    DIRECTION INPUT ;
    USE SIGNAL ;
    PORT
      LAYER M4 ;
        RECT 356.3160 10.5600 356.4000 10.5840 ;
    END
  END hw_j[1]
  PIN hw_j[2]
    DIRECTION INPUT ;
    USE SIGNAL ;
    PORT
      LAYER M4 ;
        RECT 356.3160 11.6160 356.4000 11.6400 ;
    END
  END hw_j[2]
  PIN hw_v
    DIRECTION INPUT ;
    USE SIGNAL ;
    PORT
      LAYER M4 ;
        RECT 356.3160 7.7280 356.4000 7.7520 ;
    END
  END hw_v
  PIN n_go
    DIRECTION INPUT ;
    USE SIGNAL ;
    PORT
      LAYER M4 ;
        RECT 356.3160 206.7840 356.4000 206.8080 ;
    END
  END n_go
  PIN n_pre[0]
    DIRECTION INPUT ;
    USE SIGNAL ;
    PORT
      LAYER M4 ;
        RECT 356.3160 208.2240 356.4000 208.2480 ;
    END
  END n_pre[0]
  PIN n_pre[100]
    DIRECTION INPUT ;
    USE SIGNAL ;
    PORT
      LAYER M4 ;
        RECT 356.3160 244.2240 356.4000 244.2480 ;
    END
  END n_pre[100]
  PIN n_pre[101]
    DIRECTION INPUT ;
    USE SIGNAL ;
    PORT
      LAYER M4 ;
        RECT 356.3160 244.6080 356.4000 244.6320 ;
    END
  END n_pre[101]
  PIN n_pre[102]
    DIRECTION INPUT ;
    USE SIGNAL ;
    PORT
      LAYER M4 ;
        RECT 356.3160 244.9440 356.4000 244.9680 ;
    END
  END n_pre[102]
  PIN n_pre[103]
    DIRECTION INPUT ;
    USE SIGNAL ;
    PORT
      LAYER M4 ;
        RECT 356.3160 245.3280 356.4000 245.3520 ;
    END
  END n_pre[103]
  PIN n_pre[104]
    DIRECTION INPUT ;
    USE SIGNAL ;
    PORT
      LAYER M4 ;
        RECT 356.3160 245.6640 356.4000 245.6880 ;
    END
  END n_pre[104]
  PIN n_pre[105]
    DIRECTION INPUT ;
    USE SIGNAL ;
    PORT
      LAYER M4 ;
        RECT 356.3160 246.0480 356.4000 246.0720 ;
    END
  END n_pre[105]
  PIN n_pre[106]
    DIRECTION INPUT ;
    USE SIGNAL ;
    PORT
      LAYER M4 ;
        RECT 356.3160 246.3840 356.4000 246.4080 ;
    END
  END n_pre[106]
  PIN n_pre[107]
    DIRECTION INPUT ;
    USE SIGNAL ;
    PORT
      LAYER M4 ;
        RECT 356.3160 246.7680 356.4000 246.7920 ;
    END
  END n_pre[107]
  PIN n_pre[108]
    DIRECTION INPUT ;
    USE SIGNAL ;
    PORT
      LAYER M4 ;
        RECT 356.3160 247.1040 356.4000 247.1280 ;
    END
  END n_pre[108]
  PIN n_pre[109]
    DIRECTION INPUT ;
    USE SIGNAL ;
    PORT
      LAYER M4 ;
        RECT 356.3160 247.4880 356.4000 247.5120 ;
    END
  END n_pre[109]
  PIN n_pre[10]
    DIRECTION INPUT ;
    USE SIGNAL ;
    PORT
      LAYER M4 ;
        RECT 356.3160 211.8240 356.4000 211.8480 ;
    END
  END n_pre[10]
  PIN n_pre[110]
    DIRECTION INPUT ;
    USE SIGNAL ;
    PORT
      LAYER M4 ;
        RECT 356.3160 247.8240 356.4000 247.8480 ;
    END
  END n_pre[110]
  PIN n_pre[111]
    DIRECTION INPUT ;
    USE SIGNAL ;
    PORT
      LAYER M4 ;
        RECT 356.3160 248.2080 356.4000 248.2320 ;
    END
  END n_pre[111]
  PIN n_pre[112]
    DIRECTION INPUT ;
    USE SIGNAL ;
    PORT
      LAYER M4 ;
        RECT 356.3160 248.5440 356.4000 248.5680 ;
    END
  END n_pre[112]
  PIN n_pre[113]
    DIRECTION INPUT ;
    USE SIGNAL ;
    PORT
      LAYER M4 ;
        RECT 356.3160 248.9280 356.4000 248.9520 ;
    END
  END n_pre[113]
  PIN n_pre[114]
    DIRECTION INPUT ;
    USE SIGNAL ;
    PORT
      LAYER M4 ;
        RECT 356.3160 249.2640 356.4000 249.2880 ;
    END
  END n_pre[114]
  PIN n_pre[115]
    DIRECTION INPUT ;
    USE SIGNAL ;
    PORT
      LAYER M4 ;
        RECT 356.3160 249.6480 356.4000 249.6720 ;
    END
  END n_pre[115]
  PIN n_pre[116]
    DIRECTION INPUT ;
    USE SIGNAL ;
    PORT
      LAYER M4 ;
        RECT 356.3160 249.9840 356.4000 250.0080 ;
    END
  END n_pre[116]
  PIN n_pre[117]
    DIRECTION INPUT ;
    USE SIGNAL ;
    PORT
      LAYER M4 ;
        RECT 356.3160 250.3680 356.4000 250.3920 ;
    END
  END n_pre[117]
  PIN n_pre[118]
    DIRECTION INPUT ;
    USE SIGNAL ;
    PORT
      LAYER M4 ;
        RECT 356.3160 250.7040 356.4000 250.7280 ;
    END
  END n_pre[118]
  PIN n_pre[119]
    DIRECTION INPUT ;
    USE SIGNAL ;
    PORT
      LAYER M4 ;
        RECT 356.3160 251.0880 356.4000 251.1120 ;
    END
  END n_pre[119]
  PIN n_pre[11]
    DIRECTION INPUT ;
    USE SIGNAL ;
    PORT
      LAYER M4 ;
        RECT 356.3160 212.1600 356.4000 212.1840 ;
    END
  END n_pre[11]
  PIN n_pre[120]
    DIRECTION INPUT ;
    USE SIGNAL ;
    PORT
      LAYER M4 ;
        RECT 356.3160 251.4240 356.4000 251.4480 ;
    END
  END n_pre[120]
  PIN n_pre[121]
    DIRECTION INPUT ;
    USE SIGNAL ;
    PORT
      LAYER M4 ;
        RECT 356.3160 251.8080 356.4000 251.8320 ;
    END
  END n_pre[121]
  PIN n_pre[122]
    DIRECTION INPUT ;
    USE SIGNAL ;
    PORT
      LAYER M4 ;
        RECT 356.3160 252.1440 356.4000 252.1680 ;
    END
  END n_pre[122]
  PIN n_pre[123]
    DIRECTION INPUT ;
    USE SIGNAL ;
    PORT
      LAYER M4 ;
        RECT 356.3160 252.5280 356.4000 252.5520 ;
    END
  END n_pre[123]
  PIN n_pre[124]
    DIRECTION INPUT ;
    USE SIGNAL ;
    PORT
      LAYER M4 ;
        RECT 356.3160 252.8640 356.4000 252.8880 ;
    END
  END n_pre[124]
  PIN n_pre[125]
    DIRECTION INPUT ;
    USE SIGNAL ;
    PORT
      LAYER M4 ;
        RECT 356.3160 253.2480 356.4000 253.2720 ;
    END
  END n_pre[125]
  PIN n_pre[126]
    DIRECTION INPUT ;
    USE SIGNAL ;
    PORT
      LAYER M4 ;
        RECT 356.3160 253.5840 356.4000 253.6080 ;
    END
  END n_pre[126]
  PIN n_pre[127]
    DIRECTION INPUT ;
    USE SIGNAL ;
    PORT
      LAYER M4 ;
        RECT 356.3160 253.9680 356.4000 253.9920 ;
    END
  END n_pre[127]
  PIN n_pre[12]
    DIRECTION INPUT ;
    USE SIGNAL ;
    PORT
      LAYER M4 ;
        RECT 356.3160 212.5440 356.4000 212.5680 ;
    END
  END n_pre[12]
  PIN n_pre[13]
    DIRECTION INPUT ;
    USE SIGNAL ;
    PORT
      LAYER M4 ;
        RECT 356.3160 212.8800 356.4000 212.9040 ;
    END
  END n_pre[13]
  PIN n_pre[14]
    DIRECTION INPUT ;
    USE SIGNAL ;
    PORT
      LAYER M4 ;
        RECT 356.3160 213.2640 356.4000 213.2880 ;
    END
  END n_pre[14]
  PIN n_pre[15]
    DIRECTION INPUT ;
    USE SIGNAL ;
    PORT
      LAYER M4 ;
        RECT 356.3160 213.6000 356.4000 213.6240 ;
    END
  END n_pre[15]
  PIN n_pre[16]
    DIRECTION INPUT ;
    USE SIGNAL ;
    PORT
      LAYER M4 ;
        RECT 356.3160 213.9840 356.4000 214.0080 ;
    END
  END n_pre[16]
  PIN n_pre[17]
    DIRECTION INPUT ;
    USE SIGNAL ;
    PORT
      LAYER M4 ;
        RECT 356.3160 214.3200 356.4000 214.3440 ;
    END
  END n_pre[17]
  PIN n_pre[18]
    DIRECTION INPUT ;
    USE SIGNAL ;
    PORT
      LAYER M4 ;
        RECT 356.3160 214.7040 356.4000 214.7280 ;
    END
  END n_pre[18]
  PIN n_pre[19]
    DIRECTION INPUT ;
    USE SIGNAL ;
    PORT
      LAYER M4 ;
        RECT 356.3160 215.0400 356.4000 215.0640 ;
    END
  END n_pre[19]
  PIN n_pre[1]
    DIRECTION INPUT ;
    USE SIGNAL ;
    PORT
      LAYER M4 ;
        RECT 356.3160 208.5600 356.4000 208.5840 ;
    END
  END n_pre[1]
  PIN n_pre[20]
    DIRECTION INPUT ;
    USE SIGNAL ;
    PORT
      LAYER M4 ;
        RECT 356.3160 215.4240 356.4000 215.4480 ;
    END
  END n_pre[20]
  PIN n_pre[21]
    DIRECTION INPUT ;
    USE SIGNAL ;
    PORT
      LAYER M4 ;
        RECT 356.3160 215.7600 356.4000 215.7840 ;
    END
  END n_pre[21]
  PIN n_pre[22]
    DIRECTION INPUT ;
    USE SIGNAL ;
    PORT
      LAYER M4 ;
        RECT 356.3160 216.1440 356.4000 216.1680 ;
    END
  END n_pre[22]
  PIN n_pre[23]
    DIRECTION INPUT ;
    USE SIGNAL ;
    PORT
      LAYER M4 ;
        RECT 356.3160 216.4800 356.4000 216.5040 ;
    END
  END n_pre[23]
  PIN n_pre[24]
    DIRECTION INPUT ;
    USE SIGNAL ;
    PORT
      LAYER M4 ;
        RECT 356.3160 216.8640 356.4000 216.8880 ;
    END
  END n_pre[24]
  PIN n_pre[25]
    DIRECTION INPUT ;
    USE SIGNAL ;
    PORT
      LAYER M4 ;
        RECT 356.3160 217.2000 356.4000 217.2240 ;
    END
  END n_pre[25]
  PIN n_pre[26]
    DIRECTION INPUT ;
    USE SIGNAL ;
    PORT
      LAYER M4 ;
        RECT 356.3160 217.5840 356.4000 217.6080 ;
    END
  END n_pre[26]
  PIN n_pre[27]
    DIRECTION INPUT ;
    USE SIGNAL ;
    PORT
      LAYER M4 ;
        RECT 356.3160 217.9200 356.4000 217.9440 ;
    END
  END n_pre[27]
  PIN n_pre[28]
    DIRECTION INPUT ;
    USE SIGNAL ;
    PORT
      LAYER M4 ;
        RECT 356.3160 218.3040 356.4000 218.3280 ;
    END
  END n_pre[28]
  PIN n_pre[29]
    DIRECTION INPUT ;
    USE SIGNAL ;
    PORT
      LAYER M4 ;
        RECT 356.3160 218.6400 356.4000 218.6640 ;
    END
  END n_pre[29]
  PIN n_pre[2]
    DIRECTION INPUT ;
    USE SIGNAL ;
    PORT
      LAYER M4 ;
        RECT 356.3160 208.9440 356.4000 208.9680 ;
    END
  END n_pre[2]
  PIN n_pre[30]
    DIRECTION INPUT ;
    USE SIGNAL ;
    PORT
      LAYER M4 ;
        RECT 356.3160 219.0240 356.4000 219.0480 ;
    END
  END n_pre[30]
  PIN n_pre[31]
    DIRECTION INPUT ;
    USE SIGNAL ;
    PORT
      LAYER M4 ;
        RECT 356.3160 219.3600 356.4000 219.3840 ;
    END
  END n_pre[31]
  PIN n_pre[32]
    DIRECTION INPUT ;
    USE SIGNAL ;
    PORT
      LAYER M4 ;
        RECT 356.3160 219.7440 356.4000 219.7680 ;
    END
  END n_pre[32]
  PIN n_pre[33]
    DIRECTION INPUT ;
    USE SIGNAL ;
    PORT
      LAYER M4 ;
        RECT 356.3160 220.0800 356.4000 220.1040 ;
    END
  END n_pre[33]
  PIN n_pre[34]
    DIRECTION INPUT ;
    USE SIGNAL ;
    PORT
      LAYER M4 ;
        RECT 356.3160 220.4640 356.4000 220.4880 ;
    END
  END n_pre[34]
  PIN n_pre[35]
    DIRECTION INPUT ;
    USE SIGNAL ;
    PORT
      LAYER M4 ;
        RECT 356.3160 220.8000 356.4000 220.8240 ;
    END
  END n_pre[35]
  PIN n_pre[36]
    DIRECTION INPUT ;
    USE SIGNAL ;
    PORT
      LAYER M4 ;
        RECT 356.3160 221.1840 356.4000 221.2080 ;
    END
  END n_pre[36]
  PIN n_pre[37]
    DIRECTION INPUT ;
    USE SIGNAL ;
    PORT
      LAYER M4 ;
        RECT 356.3160 221.5200 356.4000 221.5440 ;
    END
  END n_pre[37]
  PIN n_pre[38]
    DIRECTION INPUT ;
    USE SIGNAL ;
    PORT
      LAYER M4 ;
        RECT 356.3160 221.9040 356.4000 221.9280 ;
    END
  END n_pre[38]
  PIN n_pre[39]
    DIRECTION INPUT ;
    USE SIGNAL ;
    PORT
      LAYER M4 ;
        RECT 356.3160 222.2400 356.4000 222.2640 ;
    END
  END n_pre[39]
  PIN n_pre[3]
    DIRECTION INPUT ;
    USE SIGNAL ;
    PORT
      LAYER M4 ;
        RECT 356.3160 209.2800 356.4000 209.3040 ;
    END
  END n_pre[3]
  PIN n_pre[40]
    DIRECTION INPUT ;
    USE SIGNAL ;
    PORT
      LAYER M4 ;
        RECT 356.3160 222.6240 356.4000 222.6480 ;
    END
  END n_pre[40]
  PIN n_pre[41]
    DIRECTION INPUT ;
    USE SIGNAL ;
    PORT
      LAYER M4 ;
        RECT 356.3160 222.9600 356.4000 222.9840 ;
    END
  END n_pre[41]
  PIN n_pre[42]
    DIRECTION INPUT ;
    USE SIGNAL ;
    PORT
      LAYER M4 ;
        RECT 356.3160 223.3440 356.4000 223.3680 ;
    END
  END n_pre[42]
  PIN n_pre[43]
    DIRECTION INPUT ;
    USE SIGNAL ;
    PORT
      LAYER M4 ;
        RECT 356.3160 223.6800 356.4000 223.7040 ;
    END
  END n_pre[43]
  PIN n_pre[44]
    DIRECTION INPUT ;
    USE SIGNAL ;
    PORT
      LAYER M4 ;
        RECT 356.3160 224.0640 356.4000 224.0880 ;
    END
  END n_pre[44]
  PIN n_pre[45]
    DIRECTION INPUT ;
    USE SIGNAL ;
    PORT
      LAYER M4 ;
        RECT 356.3160 224.4000 356.4000 224.4240 ;
    END
  END n_pre[45]
  PIN n_pre[46]
    DIRECTION INPUT ;
    USE SIGNAL ;
    PORT
      LAYER M4 ;
        RECT 356.3160 224.7840 356.4000 224.8080 ;
    END
  END n_pre[46]
  PIN n_pre[47]
    DIRECTION INPUT ;
    USE SIGNAL ;
    PORT
      LAYER M4 ;
        RECT 356.3160 225.1200 356.4000 225.1440 ;
    END
  END n_pre[47]
  PIN n_pre[48]
    DIRECTION INPUT ;
    USE SIGNAL ;
    PORT
      LAYER M4 ;
        RECT 356.3160 225.5040 356.4000 225.5280 ;
    END
  END n_pre[48]
  PIN n_pre[49]
    DIRECTION INPUT ;
    USE SIGNAL ;
    PORT
      LAYER M4 ;
        RECT 356.3160 225.8400 356.4000 225.8640 ;
    END
  END n_pre[49]
  PIN n_pre[4]
    DIRECTION INPUT ;
    USE SIGNAL ;
    PORT
      LAYER M4 ;
        RECT 356.3160 209.6640 356.4000 209.6880 ;
    END
  END n_pre[4]
  PIN n_pre[50]
    DIRECTION INPUT ;
    USE SIGNAL ;
    PORT
      LAYER M4 ;
        RECT 356.3160 226.2240 356.4000 226.2480 ;
    END
  END n_pre[50]
  PIN n_pre[51]
    DIRECTION INPUT ;
    USE SIGNAL ;
    PORT
      LAYER M4 ;
        RECT 356.3160 226.5600 356.4000 226.5840 ;
    END
  END n_pre[51]
  PIN n_pre[52]
    DIRECTION INPUT ;
    USE SIGNAL ;
    PORT
      LAYER M4 ;
        RECT 356.3160 226.9440 356.4000 226.9680 ;
    END
  END n_pre[52]
  PIN n_pre[53]
    DIRECTION INPUT ;
    USE SIGNAL ;
    PORT
      LAYER M4 ;
        RECT 356.3160 227.2800 356.4000 227.3040 ;
    END
  END n_pre[53]
  PIN n_pre[54]
    DIRECTION INPUT ;
    USE SIGNAL ;
    PORT
      LAYER M4 ;
        RECT 356.3160 227.6640 356.4000 227.6880 ;
    END
  END n_pre[54]
  PIN n_pre[55]
    DIRECTION INPUT ;
    USE SIGNAL ;
    PORT
      LAYER M4 ;
        RECT 356.3160 228.0000 356.4000 228.0240 ;
    END
  END n_pre[55]
  PIN n_pre[56]
    DIRECTION INPUT ;
    USE SIGNAL ;
    PORT
      LAYER M4 ;
        RECT 356.3160 228.3840 356.4000 228.4080 ;
    END
  END n_pre[56]
  PIN n_pre[57]
    DIRECTION INPUT ;
    USE SIGNAL ;
    PORT
      LAYER M4 ;
        RECT 356.3160 228.7200 356.4000 228.7440 ;
    END
  END n_pre[57]
  PIN n_pre[58]
    DIRECTION INPUT ;
    USE SIGNAL ;
    PORT
      LAYER M4 ;
        RECT 356.3160 229.1040 356.4000 229.1280 ;
    END
  END n_pre[58]
  PIN n_pre[59]
    DIRECTION INPUT ;
    USE SIGNAL ;
    PORT
      LAYER M4 ;
        RECT 356.3160 229.4400 356.4000 229.4640 ;
    END
  END n_pre[59]
  PIN n_pre[5]
    DIRECTION INPUT ;
    USE SIGNAL ;
    PORT
      LAYER M4 ;
        RECT 356.3160 210.0000 356.4000 210.0240 ;
    END
  END n_pre[5]
  PIN n_pre[60]
    DIRECTION INPUT ;
    USE SIGNAL ;
    PORT
      LAYER M4 ;
        RECT 356.3160 229.8240 356.4000 229.8480 ;
    END
  END n_pre[60]
  PIN n_pre[61]
    DIRECTION INPUT ;
    USE SIGNAL ;
    PORT
      LAYER M4 ;
        RECT 356.3160 230.1600 356.4000 230.1840 ;
    END
  END n_pre[61]
  PIN n_pre[62]
    DIRECTION INPUT ;
    USE SIGNAL ;
    PORT
      LAYER M4 ;
        RECT 356.3160 230.5440 356.4000 230.5680 ;
    END
  END n_pre[62]
  PIN n_pre[63]
    DIRECTION INPUT ;
    USE SIGNAL ;
    PORT
      LAYER M4 ;
        RECT 356.3160 230.8800 356.4000 230.9040 ;
    END
  END n_pre[63]
  PIN n_pre[64]
    DIRECTION INPUT ;
    USE SIGNAL ;
    PORT
      LAYER M4 ;
        RECT 356.3160 231.2640 356.4000 231.2880 ;
    END
  END n_pre[64]
  PIN n_pre[65]
    DIRECTION INPUT ;
    USE SIGNAL ;
    PORT
      LAYER M4 ;
        RECT 356.3160 231.6000 356.4000 231.6240 ;
    END
  END n_pre[65]
  PIN n_pre[66]
    DIRECTION INPUT ;
    USE SIGNAL ;
    PORT
      LAYER M4 ;
        RECT 356.3160 231.9840 356.4000 232.0080 ;
    END
  END n_pre[66]
  PIN n_pre[67]
    DIRECTION INPUT ;
    USE SIGNAL ;
    PORT
      LAYER M4 ;
        RECT 356.3160 232.3200 356.4000 232.3440 ;
    END
  END n_pre[67]
  PIN n_pre[68]
    DIRECTION INPUT ;
    USE SIGNAL ;
    PORT
      LAYER M4 ;
        RECT 356.3160 232.7040 356.4000 232.7280 ;
    END
  END n_pre[68]
  PIN n_pre[69]
    DIRECTION INPUT ;
    USE SIGNAL ;
    PORT
      LAYER M4 ;
        RECT 356.3160 233.0400 356.4000 233.0640 ;
    END
  END n_pre[69]
  PIN n_pre[6]
    DIRECTION INPUT ;
    USE SIGNAL ;
    PORT
      LAYER M4 ;
        RECT 356.3160 210.3840 356.4000 210.4080 ;
    END
  END n_pre[6]
  PIN n_pre[70]
    DIRECTION INPUT ;
    USE SIGNAL ;
    PORT
      LAYER M4 ;
        RECT 356.3160 233.4240 356.4000 233.4480 ;
    END
  END n_pre[70]
  PIN n_pre[71]
    DIRECTION INPUT ;
    USE SIGNAL ;
    PORT
      LAYER M4 ;
        RECT 356.3160 233.7600 356.4000 233.7840 ;
    END
  END n_pre[71]
  PIN n_pre[72]
    DIRECTION INPUT ;
    USE SIGNAL ;
    PORT
      LAYER M4 ;
        RECT 356.3160 234.1440 356.4000 234.1680 ;
    END
  END n_pre[72]
  PIN n_pre[73]
    DIRECTION INPUT ;
    USE SIGNAL ;
    PORT
      LAYER M4 ;
        RECT 356.3160 234.4800 356.4000 234.5040 ;
    END
  END n_pre[73]
  PIN n_pre[74]
    DIRECTION INPUT ;
    USE SIGNAL ;
    PORT
      LAYER M4 ;
        RECT 356.3160 234.8640 356.4000 234.8880 ;
    END
  END n_pre[74]
  PIN n_pre[75]
    DIRECTION INPUT ;
    USE SIGNAL ;
    PORT
      LAYER M4 ;
        RECT 356.3160 235.2000 356.4000 235.2240 ;
    END
  END n_pre[75]
  PIN n_pre[76]
    DIRECTION INPUT ;
    USE SIGNAL ;
    PORT
      LAYER M4 ;
        RECT 356.3160 235.5840 356.4000 235.6080 ;
    END
  END n_pre[76]
  PIN n_pre[77]
    DIRECTION INPUT ;
    USE SIGNAL ;
    PORT
      LAYER M4 ;
        RECT 356.3160 235.9680 356.4000 235.9920 ;
    END
  END n_pre[77]
  PIN n_pre[78]
    DIRECTION INPUT ;
    USE SIGNAL ;
    PORT
      LAYER M4 ;
        RECT 356.3160 236.3040 356.4000 236.3280 ;
    END
  END n_pre[78]
  PIN n_pre[79]
    DIRECTION INPUT ;
    USE SIGNAL ;
    PORT
      LAYER M4 ;
        RECT 356.3160 236.6880 356.4000 236.7120 ;
    END
  END n_pre[79]
  PIN n_pre[7]
    DIRECTION INPUT ;
    USE SIGNAL ;
    PORT
      LAYER M4 ;
        RECT 356.3160 210.7200 356.4000 210.7440 ;
    END
  END n_pre[7]
  PIN n_pre[80]
    DIRECTION INPUT ;
    USE SIGNAL ;
    PORT
      LAYER M4 ;
        RECT 356.3160 237.0240 356.4000 237.0480 ;
    END
  END n_pre[80]
  PIN n_pre[81]
    DIRECTION INPUT ;
    USE SIGNAL ;
    PORT
      LAYER M4 ;
        RECT 356.3160 237.4080 356.4000 237.4320 ;
    END
  END n_pre[81]
  PIN n_pre[82]
    DIRECTION INPUT ;
    USE SIGNAL ;
    PORT
      LAYER M4 ;
        RECT 356.3160 237.7440 356.4000 237.7680 ;
    END
  END n_pre[82]
  PIN n_pre[83]
    DIRECTION INPUT ;
    USE SIGNAL ;
    PORT
      LAYER M4 ;
        RECT 356.3160 238.1280 356.4000 238.1520 ;
    END
  END n_pre[83]
  PIN n_pre[84]
    DIRECTION INPUT ;
    USE SIGNAL ;
    PORT
      LAYER M4 ;
        RECT 356.3160 238.4640 356.4000 238.4880 ;
    END
  END n_pre[84]
  PIN n_pre[85]
    DIRECTION INPUT ;
    USE SIGNAL ;
    PORT
      LAYER M4 ;
        RECT 356.3160 238.8480 356.4000 238.8720 ;
    END
  END n_pre[85]
  PIN n_pre[86]
    DIRECTION INPUT ;
    USE SIGNAL ;
    PORT
      LAYER M4 ;
        RECT 356.3160 239.1840 356.4000 239.2080 ;
    END
  END n_pre[86]
  PIN n_pre[87]
    DIRECTION INPUT ;
    USE SIGNAL ;
    PORT
      LAYER M4 ;
        RECT 356.3160 239.5680 356.4000 239.5920 ;
    END
  END n_pre[87]
  PIN n_pre[88]
    DIRECTION INPUT ;
    USE SIGNAL ;
    PORT
      LAYER M4 ;
        RECT 356.3160 239.9040 356.4000 239.9280 ;
    END
  END n_pre[88]
  PIN n_pre[89]
    DIRECTION INPUT ;
    USE SIGNAL ;
    PORT
      LAYER M4 ;
        RECT 356.3160 240.2880 356.4000 240.3120 ;
    END
  END n_pre[89]
  PIN n_pre[8]
    DIRECTION INPUT ;
    USE SIGNAL ;
    PORT
      LAYER M4 ;
        RECT 356.3160 211.1040 356.4000 211.1280 ;
    END
  END n_pre[8]
  PIN n_pre[90]
    DIRECTION INPUT ;
    USE SIGNAL ;
    PORT
      LAYER M4 ;
        RECT 356.3160 240.6240 356.4000 240.6480 ;
    END
  END n_pre[90]
  PIN n_pre[91]
    DIRECTION INPUT ;
    USE SIGNAL ;
    PORT
      LAYER M4 ;
        RECT 356.3160 241.0080 356.4000 241.0320 ;
    END
  END n_pre[91]
  PIN n_pre[92]
    DIRECTION INPUT ;
    USE SIGNAL ;
    PORT
      LAYER M4 ;
        RECT 356.3160 241.3440 356.4000 241.3680 ;
    END
  END n_pre[92]
  PIN n_pre[93]
    DIRECTION INPUT ;
    USE SIGNAL ;
    PORT
      LAYER M4 ;
        RECT 356.3160 241.7280 356.4000 241.7520 ;
    END
  END n_pre[93]
  PIN n_pre[94]
    DIRECTION INPUT ;
    USE SIGNAL ;
    PORT
      LAYER M4 ;
        RECT 356.3160 242.0640 356.4000 242.0880 ;
    END
  END n_pre[94]
  PIN n_pre[95]
    DIRECTION INPUT ;
    USE SIGNAL ;
    PORT
      LAYER M4 ;
        RECT 356.3160 242.4480 356.4000 242.4720 ;
    END
  END n_pre[95]
  PIN n_pre[96]
    DIRECTION INPUT ;
    USE SIGNAL ;
    PORT
      LAYER M4 ;
        RECT 356.3160 242.7840 356.4000 242.8080 ;
    END
  END n_pre[96]
  PIN n_pre[97]
    DIRECTION INPUT ;
    USE SIGNAL ;
    PORT
      LAYER M4 ;
        RECT 356.3160 243.1680 356.4000 243.1920 ;
    END
  END n_pre[97]
  PIN n_pre[98]
    DIRECTION INPUT ;
    USE SIGNAL ;
    PORT
      LAYER M4 ;
        RECT 356.3160 243.5040 356.4000 243.5280 ;
    END
  END n_pre[98]
  PIN n_pre[99]
    DIRECTION INPUT ;
    USE SIGNAL ;
    PORT
      LAYER M4 ;
        RECT 356.3160 243.8880 356.4000 243.9120 ;
    END
  END n_pre[99]
  PIN n_pre[9]
    DIRECTION INPUT ;
    USE SIGNAL ;
    PORT
      LAYER M4 ;
        RECT 356.3160 211.4400 356.4000 211.4640 ;
    END
  END n_pre[9]
  PIN p_d[0]
    DIRECTION OUTPUT ;
    USE SIGNAL ;
    PORT
      LAYER M3 ;
        RECT 168.3720 354.7220 168.3900 354.7600 ;
    END
  END p_d[0]
  PIN p_d[10]
    DIRECTION OUTPUT ;
    USE SIGNAL ;
    PORT
      LAYER M3 ;
        RECT 116.9640 355.3000 116.9820 355.3380 ;
    END
  END p_d[10]
  PIN p_d[11]
    DIRECTION OUTPUT ;
    USE SIGNAL ;
    PORT
      LAYER M5 ;
        RECT 111.8400 355.6645 111.8640 355.7485 ;
    END
  END p_d[11]
  PIN p_d[12]
    DIRECTION OUTPUT ;
    USE SIGNAL ;
    PORT
      LAYER M3 ;
        RECT 106.7040 355.1860 106.7220 355.2240 ;
    END
  END p_d[12]
  PIN p_d[13]
    DIRECTION OUTPUT ;
    USE SIGNAL ;
    PORT
      LAYER M5 ;
        RECT 101.5200 356.2645 101.5440 356.3485 ;
    END
  END p_d[13]
  PIN p_d[14]
    DIRECTION OUTPUT ;
    USE SIGNAL ;
    PORT
      LAYER M3 ;
        RECT 96.4080 355.0060 96.4260 355.0440 ;
    END
  END p_d[14]
  PIN p_d[15]
    DIRECTION OUTPUT ;
    USE SIGNAL ;
    PORT
      LAYER M5 ;
        RECT 91.2480 355.9525 91.2720 356.0365 ;
    END
  END p_d[15]
  PIN p_d[16]
    DIRECTION OUTPUT ;
    USE SIGNAL ;
    PORT
      LAYER M3 ;
        RECT 86.1120 355.2620 86.1300 355.3000 ;
    END
  END p_d[16]
  PIN p_d[17]
    DIRECTION OUTPUT ;
    USE SIGNAL ;
    PORT
      LAYER M5 ;
        RECT 80.9760 355.6645 81.0000 355.7485 ;
    END
  END p_d[17]
  PIN p_d[18]
    DIRECTION OUTPUT ;
    USE SIGNAL ;
    PORT
      LAYER M3 ;
        RECT 75.8520 355.2220 75.8700 355.2600 ;
    END
  END p_d[18]
  PIN p_d[19]
    DIRECTION OUTPUT ;
    USE SIGNAL ;
    PORT
      LAYER M5 ;
        RECT 70.7040 355.9525 70.7280 356.0365 ;
    END
  END p_d[19]
  PIN p_d[1]
    DIRECTION OUTPUT ;
    USE SIGNAL ;
    PORT
      LAYER M5 ;
        RECT 163.2000 355.4005 163.2240 355.4845 ;
    END
  END p_d[1]
  PIN p_d[20]
    DIRECTION OUTPUT ;
    USE SIGNAL ;
    PORT
      LAYER M3 ;
        RECT 65.5560 355.1720 65.5740 355.2100 ;
    END
  END p_d[20]
  PIN p_d[21]
    DIRECTION OUTPUT ;
    USE SIGNAL ;
    PORT
      LAYER M5 ;
        RECT 60.4320 355.9525 60.4560 356.0365 ;
    END
  END p_d[21]
  PIN p_d[22]
    DIRECTION OUTPUT ;
    USE SIGNAL ;
    PORT
      LAYER M3 ;
        RECT 55.2960 355.1860 55.3140 355.2240 ;
    END
  END p_d[22]
  PIN p_d[23]
    DIRECTION OUTPUT ;
    USE SIGNAL ;
    PORT
      LAYER M5 ;
        RECT 50.1120 355.6645 50.1360 355.7485 ;
    END
  END p_d[23]
  PIN p_d[24]
    DIRECTION OUTPUT ;
    USE SIGNAL ;
    PORT
      LAYER M3 ;
        RECT 45.0000 355.1860 45.0180 355.2240 ;
    END
  END p_d[24]
  PIN p_d[25]
    DIRECTION OUTPUT ;
    USE SIGNAL ;
    PORT
      LAYER M5 ;
        RECT 39.8400 355.9765 39.8640 356.0605 ;
    END
  END p_d[25]
  PIN p_d[26]
    DIRECTION OUTPUT ;
    USE SIGNAL ;
    PORT
      LAYER M3 ;
        RECT 34.7400 355.3000 34.7580 355.3380 ;
    END
  END p_d[26]
  PIN p_d[27]
    DIRECTION OUTPUT ;
    USE SIGNAL ;
    PORT
      LAYER M5 ;
        RECT 29.5680 355.6645 29.5920 355.7485 ;
    END
  END p_d[27]
  PIN p_d[28]
    DIRECTION OUTPUT ;
    USE SIGNAL ;
    PORT
      LAYER M3 ;
        RECT 24.4440 355.3390 24.4620 355.3770 ;
    END
  END p_d[28]
  PIN p_d[29]
    DIRECTION OUTPUT ;
    USE SIGNAL ;
    PORT
      LAYER M5 ;
        RECT 19.2960 356.2645 19.3200 356.3485 ;
    END
  END p_d[29]
  PIN p_d[2]
    DIRECTION OUTPUT ;
    USE SIGNAL ;
    PORT
      LAYER M3 ;
        RECT 158.0760 355.2620 158.0940 355.3000 ;
    END
  END p_d[2]
  PIN p_d[30]
    DIRECTION OUTPUT ;
    USE SIGNAL ;
    PORT
      LAYER M3 ;
        RECT 14.1480 355.3000 14.1660 355.3380 ;
    END
  END p_d[30]
  PIN p_d[31]
    DIRECTION OUTPUT ;
    USE SIGNAL ;
    PORT
      LAYER M5 ;
        RECT 9.0240 355.6645 9.0480 355.7485 ;
    END
  END p_d[31]
  PIN p_d[3]
    DIRECTION OUTPUT ;
    USE SIGNAL ;
    PORT
      LAYER M5 ;
        RECT 152.9280 355.4005 152.9520 355.4845 ;
    END
  END p_d[3]
  PIN p_d[4]
    DIRECTION OUTPUT ;
    USE SIGNAL ;
    PORT
      LAYER M3 ;
        RECT 147.8160 355.1650 147.8340 355.2030 ;
    END
  END p_d[4]
  PIN p_d[5]
    DIRECTION OUTPUT ;
    USE SIGNAL ;
    PORT
      LAYER M5 ;
        RECT 142.6560 355.2735 142.6800 355.3575 ;
    END
  END p_d[5]
  PIN p_d[6]
    DIRECTION OUTPUT ;
    USE SIGNAL ;
    PORT
      LAYER M3 ;
        RECT 137.5200 355.3000 137.5380 355.3380 ;
    END
  END p_d[6]
  PIN p_d[7]
    DIRECTION OUTPUT ;
    USE SIGNAL ;
    PORT
      LAYER M5 ;
        RECT 132.3840 355.2735 132.4080 355.3575 ;
    END
  END p_d[7]
  PIN p_d[8]
    DIRECTION OUTPUT ;
    USE SIGNAL ;
    PORT
      LAYER M3 ;
        RECT 127.2600 355.3000 127.2780 355.3380 ;
    END
  END p_d[8]
  PIN p_d[9]
    DIRECTION OUTPUT ;
    USE SIGNAL ;
    PORT
      LAYER M5 ;
        RECT 122.1600 356.2260 122.1840 356.3100 ;
    END
  END p_d[9]
  PIN p_v
    DIRECTION OUTPUT ;
    USE SIGNAL ;
    PORT
      LAYER M3 ;
        RECT 174.5640 355.1270 174.5820 355.1650 ;
    END
  END p_v
  PIN rb_d[0]
    DIRECTION INPUT ;
    USE SIGNAL ;
    PORT
      LAYER M3 ;
        RECT 340.0920 355.1860 340.1100 355.2240 ;
    END
  END rb_d[0]
  PIN rb_d[10]
    DIRECTION INPUT ;
    USE SIGNAL ;
    PORT
      LAYER M3 ;
        RECT 288.6840 355.3000 288.7020 355.3380 ;
    END
  END rb_d[10]
  PIN rb_d[11]
    DIRECTION INPUT ;
    USE SIGNAL ;
    PORT
      LAYER M5 ;
        RECT 283.5360 355.2735 283.5600 355.3575 ;
    END
  END rb_d[11]
  PIN rb_d[12]
    DIRECTION INPUT ;
    USE SIGNAL ;
    PORT
      LAYER M3 ;
        RECT 278.4240 355.3000 278.4420 355.3380 ;
    END
  END rb_d[12]
  PIN rb_d[13]
    DIRECTION INPUT ;
    USE SIGNAL ;
    PORT
      LAYER M5 ;
        RECT 273.2640 355.2735 273.2880 355.3575 ;
    END
  END rb_d[13]
  PIN rb_d[14]
    DIRECTION INPUT ;
    USE SIGNAL ;
    PORT
      LAYER M3 ;
        RECT 268.1280 355.3000 268.1460 355.3380 ;
    END
  END rb_d[14]
  PIN rb_d[15]
    DIRECTION INPUT ;
    USE SIGNAL ;
    PORT
      LAYER M5 ;
        RECT 262.9920 355.2735 263.0160 355.3575 ;
    END
  END rb_d[15]
  PIN rb_d[16]
    DIRECTION INPUT ;
    USE SIGNAL ;
    PORT
      LAYER M3 ;
        RECT 257.8320 354.6460 257.8500 354.6840 ;
    END
  END rb_d[16]
  PIN rb_d[17]
    DIRECTION INPUT ;
    USE SIGNAL ;
    PORT
      LAYER M5 ;
        RECT 252.7200 354.8245 252.7440 354.9085 ;
    END
  END rb_d[17]
  PIN rb_d[18]
    DIRECTION INPUT ;
    USE SIGNAL ;
    PORT
      LAYER M3 ;
        RECT 247.5720 355.1860 247.5900 355.2240 ;
    END
  END rb_d[18]
  PIN rb_d[19]
    DIRECTION INPUT ;
    USE SIGNAL ;
    PORT
      LAYER M5 ;
        RECT 242.4000 354.8245 242.4240 354.9085 ;
    END
  END rb_d[19]
  PIN rb_d[1]
    DIRECTION INPUT ;
    USE SIGNAL ;
    PORT
      LAYER M5 ;
        RECT 334.9440 354.5605 334.9680 354.6445 ;
    END
  END rb_d[1]
  PIN rb_d[20]
    DIRECTION INPUT ;
    USE SIGNAL ;
    PORT
      LAYER M3 ;
        RECT 237.2760 354.7040 237.2940 354.7420 ;
    END
  END rb_d[20]
  PIN rb_d[21]
    DIRECTION INPUT ;
    USE SIGNAL ;
    PORT
      LAYER M5 ;
        RECT 232.1280 354.8245 232.1520 354.9085 ;
    END
  END rb_d[21]
  PIN rb_d[22]
    DIRECTION INPUT ;
    USE SIGNAL ;
    PORT
      LAYER M3 ;
        RECT 227.0160 355.0660 227.0340 355.1040 ;
    END
  END rb_d[22]
  PIN rb_d[23]
    DIRECTION INPUT ;
    USE SIGNAL ;
    PORT
      LAYER M5 ;
        RECT 221.8560 355.4005 221.8800 355.4845 ;
    END
  END rb_d[23]
  PIN rb_d[24]
    DIRECTION INPUT ;
    USE SIGNAL ;
    PORT
      LAYER M3 ;
        RECT 216.7200 354.9200 216.7380 354.9580 ;
    END
  END rb_d[24]
  PIN rb_d[25]
    DIRECTION INPUT ;
    USE SIGNAL ;
    PORT
      LAYER M5 ;
        RECT 211.5840 355.6885 211.6080 355.7725 ;
    END
  END rb_d[25]
  PIN rb_d[26]
    DIRECTION INPUT ;
    USE SIGNAL ;
    PORT
      LAYER M3 ;
        RECT 206.4600 355.2760 206.4780 355.3140 ;
    END
  END rb_d[26]
  PIN rb_d[27]
    DIRECTION INPUT ;
    USE SIGNAL ;
    PORT
      LAYER M5 ;
        RECT 201.3120 355.4005 201.3360 355.4845 ;
    END
  END rb_d[27]
  PIN rb_d[28]
    DIRECTION INPUT ;
    USE SIGNAL ;
    PORT
      LAYER M3 ;
        RECT 196.1640 355.1860 196.1820 355.2240 ;
    END
  END rb_d[28]
  PIN rb_d[29]
    DIRECTION INPUT ;
    USE SIGNAL ;
    PORT
      LAYER M5 ;
        RECT 190.9920 355.4005 191.0160 355.4845 ;
    END
  END rb_d[29]
  PIN rb_d[2]
    DIRECTION INPUT ;
    USE SIGNAL ;
    PORT
      LAYER M3 ;
        RECT 329.7960 354.4340 329.8140 354.4720 ;
    END
  END rb_d[2]
  PIN rb_d[30]
    DIRECTION INPUT ;
    USE SIGNAL ;
    PORT
      LAYER M3 ;
        RECT 185.8680 355.3000 185.8860 355.3380 ;
    END
  END rb_d[30]
  PIN rb_d[31]
    DIRECTION INPUT ;
    USE SIGNAL ;
    PORT
      LAYER M5 ;
        RECT 180.7200 356.3160 180.7440 356.4000 ;
    END
  END rb_d[31]
  PIN rb_d[3]
    DIRECTION INPUT ;
    USE SIGNAL ;
    PORT
      LAYER M5 ;
        RECT 324.6720 354.8245 324.6960 354.9085 ;
    END
  END rb_d[3]
  PIN rb_d[4]
    DIRECTION INPUT ;
    USE SIGNAL ;
    PORT
      LAYER M3 ;
        RECT 319.5360 355.1860 319.5540 355.2240 ;
    END
  END rb_d[4]
  PIN rb_d[5]
    DIRECTION INPUT ;
    USE SIGNAL ;
    PORT
      LAYER M5 ;
        RECT 314.4000 355.6645 314.4240 355.7485 ;
    END
  END rb_d[5]
  PIN rb_d[6]
    DIRECTION INPUT ;
    USE SIGNAL ;
    PORT
      LAYER M3 ;
        RECT 309.2400 354.4160 309.2580 354.4540 ;
    END
  END rb_d[6]
  PIN rb_d[7]
    DIRECTION INPUT ;
    USE SIGNAL ;
    PORT
      LAYER M5 ;
        RECT 304.0800 356.3160 304.1040 356.4000 ;
    END
  END rb_d[7]
  PIN rb_d[8]
    DIRECTION INPUT ;
    USE SIGNAL ;
    PORT
      LAYER M3 ;
        RECT 298.9800 355.1650 298.9980 355.2030 ;
    END
  END rb_d[8]
  PIN rb_d[9]
    DIRECTION INPUT ;
    USE SIGNAL ;
    PORT
      LAYER M5 ;
        RECT 293.8080 355.4005 293.8320 355.4845 ;
    END
  END rb_d[9]
  PIN rb_v
    DIRECTION INPUT ;
    USE SIGNAL ;
    PORT
      LAYER M3 ;
        RECT 346.2840 355.1860 346.3020 355.2240 ;
    END
  END rb_v
  PIN rst_n
    DIRECTION INPUT ;
    USE SIGNAL ;
    PORT
      LAYER M5 ;
        RECT 89.5680 0.2475 89.5920 0.3315 ;
    END
  END rst_n
  PIN wl_d[0]
    DIRECTION INPUT ;
    USE SIGNAL ;
    PORT
      LAYER M4 ;
        RECT 356.3160 260.0160 356.4000 260.0400 ;
    END
  END wl_d[0]
  PIN wl_d[100]
    DIRECTION INPUT ;
    USE SIGNAL ;
    PORT
      LAYER M4 ;
        RECT 356.3160 295.2000 356.4000 295.2240 ;
    END
  END wl_d[100]
  PIN wl_d[101]
    DIRECTION INPUT ;
    USE SIGNAL ;
    PORT
      LAYER M4 ;
        RECT 356.3160 295.5360 356.4000 295.5600 ;
    END
  END wl_d[101]
  PIN wl_d[102]
    DIRECTION INPUT ;
    USE SIGNAL ;
    PORT
      LAYER M4 ;
        RECT 356.3160 295.9200 356.4000 295.9440 ;
    END
  END wl_d[102]
  PIN wl_d[103]
    DIRECTION INPUT ;
    USE SIGNAL ;
    PORT
      LAYER M4 ;
        RECT 356.3160 296.2560 356.4000 296.2800 ;
    END
  END wl_d[103]
  PIN wl_d[104]
    DIRECTION INPUT ;
    USE SIGNAL ;
    PORT
      LAYER M4 ;
        RECT 356.3160 296.5920 356.4000 296.6160 ;
    END
  END wl_d[104]
  PIN wl_d[105]
    DIRECTION INPUT ;
    USE SIGNAL ;
    PORT
      LAYER M4 ;
        RECT 356.3160 296.9760 356.4000 297.0000 ;
    END
  END wl_d[105]
  PIN wl_d[106]
    DIRECTION INPUT ;
    USE SIGNAL ;
    PORT
      LAYER M4 ;
        RECT 356.3160 297.3120 356.4000 297.3360 ;
    END
  END wl_d[106]
  PIN wl_d[107]
    DIRECTION INPUT ;
    USE SIGNAL ;
    PORT
      LAYER M4 ;
        RECT 356.3160 297.6480 356.4000 297.6720 ;
    END
  END wl_d[107]
  PIN wl_d[108]
    DIRECTION INPUT ;
    USE SIGNAL ;
    PORT
      LAYER M4 ;
        RECT 356.3160 298.0320 356.4000 298.0560 ;
    END
  END wl_d[108]
  PIN wl_d[109]
    DIRECTION INPUT ;
    USE SIGNAL ;
    PORT
      LAYER M4 ;
        RECT 356.3160 298.3680 356.4000 298.3920 ;
    END
  END wl_d[109]
  PIN wl_d[10]
    DIRECTION INPUT ;
    USE SIGNAL ;
    PORT
      LAYER M4 ;
        RECT 356.3160 263.5200 356.4000 263.5440 ;
    END
  END wl_d[10]
  PIN wl_d[110]
    DIRECTION INPUT ;
    USE SIGNAL ;
    PORT
      LAYER M4 ;
        RECT 356.3160 298.7040 356.4000 298.7280 ;
    END
  END wl_d[110]
  PIN wl_d[111]
    DIRECTION INPUT ;
    USE SIGNAL ;
    PORT
      LAYER M4 ;
        RECT 356.3160 299.0880 356.4000 299.1120 ;
    END
  END wl_d[111]
  PIN wl_d[112]
    DIRECTION INPUT ;
    USE SIGNAL ;
    PORT
      LAYER M4 ;
        RECT 356.3160 299.4240 356.4000 299.4480 ;
    END
  END wl_d[112]
  PIN wl_d[113]
    DIRECTION INPUT ;
    USE SIGNAL ;
    PORT
      LAYER M4 ;
        RECT 356.3160 299.7600 356.4000 299.7840 ;
    END
  END wl_d[113]
  PIN wl_d[114]
    DIRECTION INPUT ;
    USE SIGNAL ;
    PORT
      LAYER M4 ;
        RECT 356.3160 300.1440 356.4000 300.1680 ;
    END
  END wl_d[114]
  PIN wl_d[115]
    DIRECTION INPUT ;
    USE SIGNAL ;
    PORT
      LAYER M4 ;
        RECT 356.3160 300.4800 356.4000 300.5040 ;
    END
  END wl_d[115]
  PIN wl_d[116]
    DIRECTION INPUT ;
    USE SIGNAL ;
    PORT
      LAYER M4 ;
        RECT 356.3160 300.8160 356.4000 300.8400 ;
    END
  END wl_d[116]
  PIN wl_d[117]
    DIRECTION INPUT ;
    USE SIGNAL ;
    PORT
      LAYER M4 ;
        RECT 356.3160 301.1520 356.4000 301.1760 ;
    END
  END wl_d[117]
  PIN wl_d[118]
    DIRECTION INPUT ;
    USE SIGNAL ;
    PORT
      LAYER M4 ;
        RECT 356.3160 301.5360 356.4000 301.5600 ;
    END
  END wl_d[118]
  PIN wl_d[119]
    DIRECTION INPUT ;
    USE SIGNAL ;
    PORT
      LAYER M4 ;
        RECT 356.3160 301.8720 356.4000 301.8960 ;
    END
  END wl_d[119]
  PIN wl_d[11]
    DIRECTION INPUT ;
    USE SIGNAL ;
    PORT
      LAYER M4 ;
        RECT 356.3160 263.8560 356.4000 263.8800 ;
    END
  END wl_d[11]
  PIN wl_d[120]
    DIRECTION INPUT ;
    USE SIGNAL ;
    PORT
      LAYER M4 ;
        RECT 356.3160 302.2080 356.4000 302.2320 ;
    END
  END wl_d[120]
  PIN wl_d[121]
    DIRECTION INPUT ;
    USE SIGNAL ;
    PORT
      LAYER M4 ;
        RECT 356.3160 302.5920 356.4000 302.6160 ;
    END
  END wl_d[121]
  PIN wl_d[122]
    DIRECTION INPUT ;
    USE SIGNAL ;
    PORT
      LAYER M4 ;
        RECT 356.3160 302.9280 356.4000 302.9520 ;
    END
  END wl_d[122]
  PIN wl_d[123]
    DIRECTION INPUT ;
    USE SIGNAL ;
    PORT
      LAYER M4 ;
        RECT 356.3160 303.2640 356.4000 303.2880 ;
    END
  END wl_d[123]
  PIN wl_d[124]
    DIRECTION INPUT ;
    USE SIGNAL ;
    PORT
      LAYER M4 ;
        RECT 356.3160 303.6480 356.4000 303.6720 ;
    END
  END wl_d[124]
  PIN wl_d[125]
    DIRECTION INPUT ;
    USE SIGNAL ;
    PORT
      LAYER M4 ;
        RECT 356.3160 303.9840 356.4000 304.0080 ;
    END
  END wl_d[125]
  PIN wl_d[126]
    DIRECTION INPUT ;
    USE SIGNAL ;
    PORT
      LAYER M4 ;
        RECT 356.3160 304.3200 356.4000 304.3440 ;
    END
  END wl_d[126]
  PIN wl_d[127]
    DIRECTION INPUT ;
    USE SIGNAL ;
    PORT
      LAYER M4 ;
        RECT 356.3160 304.7040 356.4000 304.7280 ;
    END
  END wl_d[127]
  PIN wl_d[128]
    DIRECTION INPUT ;
    USE SIGNAL ;
    PORT
      LAYER M4 ;
        RECT 356.3160 305.0400 356.4000 305.0640 ;
    END
  END wl_d[128]
  PIN wl_d[129]
    DIRECTION INPUT ;
    USE SIGNAL ;
    PORT
      LAYER M4 ;
        RECT 356.3160 305.3760 356.4000 305.4000 ;
    END
  END wl_d[129]
  PIN wl_d[12]
    DIRECTION INPUT ;
    USE SIGNAL ;
    PORT
      LAYER M4 ;
        RECT 356.3160 264.2400 356.4000 264.2640 ;
    END
  END wl_d[12]
  PIN wl_d[130]
    DIRECTION INPUT ;
    USE SIGNAL ;
    PORT
      LAYER M4 ;
        RECT 356.3160 305.7600 356.4000 305.7840 ;
    END
  END wl_d[130]
  PIN wl_d[131]
    DIRECTION INPUT ;
    USE SIGNAL ;
    PORT
      LAYER M4 ;
        RECT 356.3160 306.0960 356.4000 306.1200 ;
    END
  END wl_d[131]
  PIN wl_d[132]
    DIRECTION INPUT ;
    USE SIGNAL ;
    PORT
      LAYER M4 ;
        RECT 356.3160 306.4320 356.4000 306.4560 ;
    END
  END wl_d[132]
  PIN wl_d[133]
    DIRECTION INPUT ;
    USE SIGNAL ;
    PORT
      LAYER M4 ;
        RECT 356.3160 306.8160 356.4000 306.8400 ;
    END
  END wl_d[133]
  PIN wl_d[134]
    DIRECTION INPUT ;
    USE SIGNAL ;
    PORT
      LAYER M4 ;
        RECT 356.3160 307.1520 356.4000 307.1760 ;
    END
  END wl_d[134]
  PIN wl_d[135]
    DIRECTION INPUT ;
    USE SIGNAL ;
    PORT
      LAYER M4 ;
        RECT 356.3160 307.4880 356.4000 307.5120 ;
    END
  END wl_d[135]
  PIN wl_d[136]
    DIRECTION INPUT ;
    USE SIGNAL ;
    PORT
      LAYER M4 ;
        RECT 356.3160 307.8720 356.4000 307.8960 ;
    END
  END wl_d[136]
  PIN wl_d[137]
    DIRECTION INPUT ;
    USE SIGNAL ;
    PORT
      LAYER M4 ;
        RECT 356.3160 308.2080 356.4000 308.2320 ;
    END
  END wl_d[137]
  PIN wl_d[138]
    DIRECTION INPUT ;
    USE SIGNAL ;
    PORT
      LAYER M4 ;
        RECT 356.3160 308.5440 356.4000 308.5680 ;
    END
  END wl_d[138]
  PIN wl_d[139]
    DIRECTION INPUT ;
    USE SIGNAL ;
    PORT
      LAYER M4 ;
        RECT 356.3160 308.9280 356.4000 308.9520 ;
    END
  END wl_d[139]
  PIN wl_d[13]
    DIRECTION INPUT ;
    USE SIGNAL ;
    PORT
      LAYER M4 ;
        RECT 356.3160 264.5760 356.4000 264.6000 ;
    END
  END wl_d[13]
  PIN wl_d[140]
    DIRECTION INPUT ;
    USE SIGNAL ;
    PORT
      LAYER M4 ;
        RECT 356.3160 309.2640 356.4000 309.2880 ;
    END
  END wl_d[140]
  PIN wl_d[141]
    DIRECTION INPUT ;
    USE SIGNAL ;
    PORT
      LAYER M4 ;
        RECT 356.3160 309.6000 356.4000 309.6240 ;
    END
  END wl_d[141]
  PIN wl_d[142]
    DIRECTION INPUT ;
    USE SIGNAL ;
    PORT
      LAYER M4 ;
        RECT 356.3160 309.9840 356.4000 310.0080 ;
    END
  END wl_d[142]
  PIN wl_d[143]
    DIRECTION INPUT ;
    USE SIGNAL ;
    PORT
      LAYER M4 ;
        RECT 356.3160 310.3200 356.4000 310.3440 ;
    END
  END wl_d[143]
  PIN wl_d[144]
    DIRECTION INPUT ;
    USE SIGNAL ;
    PORT
      LAYER M4 ;
        RECT 356.3160 310.6560 356.4000 310.6800 ;
    END
  END wl_d[144]
  PIN wl_d[145]
    DIRECTION INPUT ;
    USE SIGNAL ;
    PORT
      LAYER M4 ;
        RECT 356.3160 311.0400 356.4000 311.0640 ;
    END
  END wl_d[145]
  PIN wl_d[146]
    DIRECTION INPUT ;
    USE SIGNAL ;
    PORT
      LAYER M4 ;
        RECT 356.3160 311.3760 356.4000 311.4000 ;
    END
  END wl_d[146]
  PIN wl_d[147]
    DIRECTION INPUT ;
    USE SIGNAL ;
    PORT
      LAYER M4 ;
        RECT 356.3160 311.7120 356.4000 311.7360 ;
    END
  END wl_d[147]
  PIN wl_d[148]
    DIRECTION INPUT ;
    USE SIGNAL ;
    PORT
      LAYER M4 ;
        RECT 356.3160 312.0960 356.4000 312.1200 ;
    END
  END wl_d[148]
  PIN wl_d[149]
    DIRECTION INPUT ;
    USE SIGNAL ;
    PORT
      LAYER M4 ;
        RECT 356.3160 312.4320 356.4000 312.4560 ;
    END
  END wl_d[149]
  PIN wl_d[14]
    DIRECTION INPUT ;
    USE SIGNAL ;
    PORT
      LAYER M4 ;
        RECT 356.3160 264.9120 356.4000 264.9360 ;
    END
  END wl_d[14]
  PIN wl_d[150]
    DIRECTION INPUT ;
    USE SIGNAL ;
    PORT
      LAYER M4 ;
        RECT 356.3160 312.7680 356.4000 312.7920 ;
    END
  END wl_d[150]
  PIN wl_d[151]
    DIRECTION INPUT ;
    USE SIGNAL ;
    PORT
      LAYER M4 ;
        RECT 356.3160 313.1520 356.4000 313.1760 ;
    END
  END wl_d[151]
  PIN wl_d[152]
    DIRECTION INPUT ;
    USE SIGNAL ;
    PORT
      LAYER M4 ;
        RECT 356.3160 313.4880 356.4000 313.5120 ;
    END
  END wl_d[152]
  PIN wl_d[153]
    DIRECTION INPUT ;
    USE SIGNAL ;
    PORT
      LAYER M4 ;
        RECT 356.3160 313.8240 356.4000 313.8480 ;
    END
  END wl_d[153]
  PIN wl_d[154]
    DIRECTION INPUT ;
    USE SIGNAL ;
    PORT
      LAYER M4 ;
        RECT 356.3160 314.2080 356.4000 314.2320 ;
    END
  END wl_d[154]
  PIN wl_d[155]
    DIRECTION INPUT ;
    USE SIGNAL ;
    PORT
      LAYER M4 ;
        RECT 356.3160 314.5440 356.4000 314.5680 ;
    END
  END wl_d[155]
  PIN wl_d[156]
    DIRECTION INPUT ;
    USE SIGNAL ;
    PORT
      LAYER M4 ;
        RECT 356.3160 314.8800 356.4000 314.9040 ;
    END
  END wl_d[156]
  PIN wl_d[157]
    DIRECTION INPUT ;
    USE SIGNAL ;
    PORT
      LAYER M4 ;
        RECT 356.3160 315.2640 356.4000 315.2880 ;
    END
  END wl_d[157]
  PIN wl_d[158]
    DIRECTION INPUT ;
    USE SIGNAL ;
    PORT
      LAYER M4 ;
        RECT 356.3160 315.6000 356.4000 315.6240 ;
    END
  END wl_d[158]
  PIN wl_d[159]
    DIRECTION INPUT ;
    USE SIGNAL ;
    PORT
      LAYER M4 ;
        RECT 356.3160 315.9360 356.4000 315.9600 ;
    END
  END wl_d[159]
  PIN wl_d[15]
    DIRECTION INPUT ;
    USE SIGNAL ;
    PORT
      LAYER M4 ;
        RECT 356.3160 265.2960 356.4000 265.3200 ;
    END
  END wl_d[15]
  PIN wl_d[160]
    DIRECTION INPUT ;
    USE SIGNAL ;
    PORT
      LAYER M4 ;
        RECT 356.3160 316.3200 356.4000 316.3440 ;
    END
  END wl_d[160]
  PIN wl_d[161]
    DIRECTION INPUT ;
    USE SIGNAL ;
    PORT
      LAYER M4 ;
        RECT 356.3160 316.6560 356.4000 316.6800 ;
    END
  END wl_d[161]
  PIN wl_d[162]
    DIRECTION INPUT ;
    USE SIGNAL ;
    PORT
      LAYER M4 ;
        RECT 356.3160 316.9920 356.4000 317.0160 ;
    END
  END wl_d[162]
  PIN wl_d[163]
    DIRECTION INPUT ;
    USE SIGNAL ;
    PORT
      LAYER M4 ;
        RECT 356.3160 317.3760 356.4000 317.4000 ;
    END
  END wl_d[163]
  PIN wl_d[164]
    DIRECTION INPUT ;
    USE SIGNAL ;
    PORT
      LAYER M4 ;
        RECT 356.3160 317.7120 356.4000 317.7360 ;
    END
  END wl_d[164]
  PIN wl_d[165]
    DIRECTION INPUT ;
    USE SIGNAL ;
    PORT
      LAYER M4 ;
        RECT 356.3160 318.0480 356.4000 318.0720 ;
    END
  END wl_d[165]
  PIN wl_d[166]
    DIRECTION INPUT ;
    USE SIGNAL ;
    PORT
      LAYER M4 ;
        RECT 356.3160 318.4320 356.4000 318.4560 ;
    END
  END wl_d[166]
  PIN wl_d[167]
    DIRECTION INPUT ;
    USE SIGNAL ;
    PORT
      LAYER M4 ;
        RECT 356.3160 318.7680 356.4000 318.7920 ;
    END
  END wl_d[167]
  PIN wl_d[168]
    DIRECTION INPUT ;
    USE SIGNAL ;
    PORT
      LAYER M4 ;
        RECT 356.3160 319.1040 356.4000 319.1280 ;
    END
  END wl_d[168]
  PIN wl_d[169]
    DIRECTION INPUT ;
    USE SIGNAL ;
    PORT
      LAYER M4 ;
        RECT 356.3160 319.4880 356.4000 319.5120 ;
    END
  END wl_d[169]
  PIN wl_d[16]
    DIRECTION INPUT ;
    USE SIGNAL ;
    PORT
      LAYER M4 ;
        RECT 356.3160 265.6320 356.4000 265.6560 ;
    END
  END wl_d[16]
  PIN wl_d[170]
    DIRECTION INPUT ;
    USE SIGNAL ;
    PORT
      LAYER M4 ;
        RECT 356.3160 319.8240 356.4000 319.8480 ;
    END
  END wl_d[170]
  PIN wl_d[171]
    DIRECTION INPUT ;
    USE SIGNAL ;
    PORT
      LAYER M4 ;
        RECT 356.3160 320.1600 356.4000 320.1840 ;
    END
  END wl_d[171]
  PIN wl_d[172]
    DIRECTION INPUT ;
    USE SIGNAL ;
    PORT
      LAYER M4 ;
        RECT 356.3160 320.5440 356.4000 320.5680 ;
    END
  END wl_d[172]
  PIN wl_d[173]
    DIRECTION INPUT ;
    USE SIGNAL ;
    PORT
      LAYER M4 ;
        RECT 356.3160 320.8800 356.4000 320.9040 ;
    END
  END wl_d[173]
  PIN wl_d[174]
    DIRECTION INPUT ;
    USE SIGNAL ;
    PORT
      LAYER M4 ;
        RECT 356.3160 321.2160 356.4000 321.2400 ;
    END
  END wl_d[174]
  PIN wl_d[175]
    DIRECTION INPUT ;
    USE SIGNAL ;
    PORT
      LAYER M4 ;
        RECT 356.3160 321.6000 356.4000 321.6240 ;
    END
  END wl_d[175]
  PIN wl_d[176]
    DIRECTION INPUT ;
    USE SIGNAL ;
    PORT
      LAYER M4 ;
        RECT 356.3160 321.9360 356.4000 321.9600 ;
    END
  END wl_d[176]
  PIN wl_d[177]
    DIRECTION INPUT ;
    USE SIGNAL ;
    PORT
      LAYER M4 ;
        RECT 356.3160 322.2720 356.4000 322.2960 ;
    END
  END wl_d[177]
  PIN wl_d[178]
    DIRECTION INPUT ;
    USE SIGNAL ;
    PORT
      LAYER M4 ;
        RECT 356.3160 322.6560 356.4000 322.6800 ;
    END
  END wl_d[178]
  PIN wl_d[179]
    DIRECTION INPUT ;
    USE SIGNAL ;
    PORT
      LAYER M4 ;
        RECT 356.3160 322.9920 356.4000 323.0160 ;
    END
  END wl_d[179]
  PIN wl_d[17]
    DIRECTION INPUT ;
    USE SIGNAL ;
    PORT
      LAYER M4 ;
        RECT 356.3160 265.9680 356.4000 265.9920 ;
    END
  END wl_d[17]
  PIN wl_d[180]
    DIRECTION INPUT ;
    USE SIGNAL ;
    PORT
      LAYER M4 ;
        RECT 356.3160 323.3280 356.4000 323.3520 ;
    END
  END wl_d[180]
  PIN wl_d[181]
    DIRECTION INPUT ;
    USE SIGNAL ;
    PORT
      LAYER M4 ;
        RECT 356.3160 323.7120 356.4000 323.7360 ;
    END
  END wl_d[181]
  PIN wl_d[182]
    DIRECTION INPUT ;
    USE SIGNAL ;
    PORT
      LAYER M4 ;
        RECT 356.3160 324.0480 356.4000 324.0720 ;
    END
  END wl_d[182]
  PIN wl_d[183]
    DIRECTION INPUT ;
    USE SIGNAL ;
    PORT
      LAYER M4 ;
        RECT 356.3160 324.3840 356.4000 324.4080 ;
    END
  END wl_d[183]
  PIN wl_d[184]
    DIRECTION INPUT ;
    USE SIGNAL ;
    PORT
      LAYER M4 ;
        RECT 356.3160 324.7680 356.4000 324.7920 ;
    END
  END wl_d[184]
  PIN wl_d[185]
    DIRECTION INPUT ;
    USE SIGNAL ;
    PORT
      LAYER M4 ;
        RECT 356.3160 325.1040 356.4000 325.1280 ;
    END
  END wl_d[185]
  PIN wl_d[186]
    DIRECTION INPUT ;
    USE SIGNAL ;
    PORT
      LAYER M4 ;
        RECT 356.3160 325.4400 356.4000 325.4640 ;
    END
  END wl_d[186]
  PIN wl_d[187]
    DIRECTION INPUT ;
    USE SIGNAL ;
    PORT
      LAYER M4 ;
        RECT 356.3160 325.8240 356.4000 325.8480 ;
    END
  END wl_d[187]
  PIN wl_d[188]
    DIRECTION INPUT ;
    USE SIGNAL ;
    PORT
      LAYER M4 ;
        RECT 356.3160 326.1600 356.4000 326.1840 ;
    END
  END wl_d[188]
  PIN wl_d[189]
    DIRECTION INPUT ;
    USE SIGNAL ;
    PORT
      LAYER M4 ;
        RECT 356.3160 326.4960 356.4000 326.5200 ;
    END
  END wl_d[189]
  PIN wl_d[18]
    DIRECTION INPUT ;
    USE SIGNAL ;
    PORT
      LAYER M4 ;
        RECT 356.3160 266.3520 356.4000 266.3760 ;
    END
  END wl_d[18]
  PIN wl_d[190]
    DIRECTION INPUT ;
    USE SIGNAL ;
    PORT
      LAYER M4 ;
        RECT 356.3160 326.8800 356.4000 326.9040 ;
    END
  END wl_d[190]
  PIN wl_d[191]
    DIRECTION INPUT ;
    USE SIGNAL ;
    PORT
      LAYER M4 ;
        RECT 356.3160 327.2160 356.4000 327.2400 ;
    END
  END wl_d[191]
  PIN wl_d[192]
    DIRECTION INPUT ;
    USE SIGNAL ;
    PORT
      LAYER M4 ;
        RECT 356.3160 327.5520 356.4000 327.5760 ;
    END
  END wl_d[192]
  PIN wl_d[193]
    DIRECTION INPUT ;
    USE SIGNAL ;
    PORT
      LAYER M4 ;
        RECT 356.3160 327.9360 356.4000 327.9600 ;
    END
  END wl_d[193]
  PIN wl_d[194]
    DIRECTION INPUT ;
    USE SIGNAL ;
    PORT
      LAYER M4 ;
        RECT 356.3160 328.2720 356.4000 328.2960 ;
    END
  END wl_d[194]
  PIN wl_d[195]
    DIRECTION INPUT ;
    USE SIGNAL ;
    PORT
      LAYER M4 ;
        RECT 356.3160 328.6080 356.4000 328.6320 ;
    END
  END wl_d[195]
  PIN wl_d[196]
    DIRECTION INPUT ;
    USE SIGNAL ;
    PORT
      LAYER M4 ;
        RECT 356.3160 328.9920 356.4000 329.0160 ;
    END
  END wl_d[196]
  PIN wl_d[197]
    DIRECTION INPUT ;
    USE SIGNAL ;
    PORT
      LAYER M4 ;
        RECT 356.3160 329.3280 356.4000 329.3520 ;
    END
  END wl_d[197]
  PIN wl_d[198]
    DIRECTION INPUT ;
    USE SIGNAL ;
    PORT
      LAYER M4 ;
        RECT 356.3160 329.6640 356.4000 329.6880 ;
    END
  END wl_d[198]
  PIN wl_d[199]
    DIRECTION INPUT ;
    USE SIGNAL ;
    PORT
      LAYER M4 ;
        RECT 356.3160 330.0480 356.4000 330.0720 ;
    END
  END wl_d[199]
  PIN wl_d[19]
    DIRECTION INPUT ;
    USE SIGNAL ;
    PORT
      LAYER M4 ;
        RECT 356.3160 266.6880 356.4000 266.7120 ;
    END
  END wl_d[19]
  PIN wl_d[1]
    DIRECTION INPUT ;
    USE SIGNAL ;
    PORT
      LAYER M4 ;
        RECT 356.3160 260.3520 356.4000 260.3760 ;
    END
  END wl_d[1]
  PIN wl_d[200]
    DIRECTION INPUT ;
    USE SIGNAL ;
    PORT
      LAYER M4 ;
        RECT 356.3160 330.3840 356.4000 330.4080 ;
    END
  END wl_d[200]
  PIN wl_d[201]
    DIRECTION INPUT ;
    USE SIGNAL ;
    PORT
      LAYER M4 ;
        RECT 356.3160 330.7200 356.4000 330.7440 ;
    END
  END wl_d[201]
  PIN wl_d[202]
    DIRECTION INPUT ;
    USE SIGNAL ;
    PORT
      LAYER M4 ;
        RECT 356.3160 331.1040 356.4000 331.1280 ;
    END
  END wl_d[202]
  PIN wl_d[203]
    DIRECTION INPUT ;
    USE SIGNAL ;
    PORT
      LAYER M4 ;
        RECT 356.3160 331.4400 356.4000 331.4640 ;
    END
  END wl_d[203]
  PIN wl_d[204]
    DIRECTION INPUT ;
    USE SIGNAL ;
    PORT
      LAYER M4 ;
        RECT 356.3160 331.7760 356.4000 331.8000 ;
    END
  END wl_d[204]
  PIN wl_d[205]
    DIRECTION INPUT ;
    USE SIGNAL ;
    PORT
      LAYER M4 ;
        RECT 356.3160 332.1600 356.4000 332.1840 ;
    END
  END wl_d[205]
  PIN wl_d[206]
    DIRECTION INPUT ;
    USE SIGNAL ;
    PORT
      LAYER M4 ;
        RECT 356.3160 332.4960 356.4000 332.5200 ;
    END
  END wl_d[206]
  PIN wl_d[207]
    DIRECTION INPUT ;
    USE SIGNAL ;
    PORT
      LAYER M4 ;
        RECT 356.3160 332.8320 356.4000 332.8560 ;
    END
  END wl_d[207]
  PIN wl_d[208]
    DIRECTION INPUT ;
    USE SIGNAL ;
    PORT
      LAYER M4 ;
        RECT 356.3160 333.2160 356.4000 333.2400 ;
    END
  END wl_d[208]
  PIN wl_d[209]
    DIRECTION INPUT ;
    USE SIGNAL ;
    PORT
      LAYER M4 ;
        RECT 356.3160 333.5520 356.4000 333.5760 ;
    END
  END wl_d[209]
  PIN wl_d[20]
    DIRECTION INPUT ;
    USE SIGNAL ;
    PORT
      LAYER M4 ;
        RECT 356.3160 267.0240 356.4000 267.0480 ;
    END
  END wl_d[20]
  PIN wl_d[210]
    DIRECTION INPUT ;
    USE SIGNAL ;
    PORT
      LAYER M4 ;
        RECT 356.3160 333.8880 356.4000 333.9120 ;
    END
  END wl_d[210]
  PIN wl_d[211]
    DIRECTION INPUT ;
    USE SIGNAL ;
    PORT
      LAYER M4 ;
        RECT 356.3160 334.2720 356.4000 334.2960 ;
    END
  END wl_d[211]
  PIN wl_d[212]
    DIRECTION INPUT ;
    USE SIGNAL ;
    PORT
      LAYER M4 ;
        RECT 356.3160 334.6080 356.4000 334.6320 ;
    END
  END wl_d[212]
  PIN wl_d[213]
    DIRECTION INPUT ;
    USE SIGNAL ;
    PORT
      LAYER M4 ;
        RECT 356.3160 334.9440 356.4000 334.9680 ;
    END
  END wl_d[213]
  PIN wl_d[214]
    DIRECTION INPUT ;
    USE SIGNAL ;
    PORT
      LAYER M4 ;
        RECT 356.3160 335.3280 356.4000 335.3520 ;
    END
  END wl_d[214]
  PIN wl_d[215]
    DIRECTION INPUT ;
    USE SIGNAL ;
    PORT
      LAYER M4 ;
        RECT 356.3160 335.6640 356.4000 335.6880 ;
    END
  END wl_d[215]
  PIN wl_d[216]
    DIRECTION INPUT ;
    USE SIGNAL ;
    PORT
      LAYER M4 ;
        RECT 356.3160 336.0000 356.4000 336.0240 ;
    END
  END wl_d[216]
  PIN wl_d[217]
    DIRECTION INPUT ;
    USE SIGNAL ;
    PORT
      LAYER M4 ;
        RECT 356.3160 336.3840 356.4000 336.4080 ;
    END
  END wl_d[217]
  PIN wl_d[218]
    DIRECTION INPUT ;
    USE SIGNAL ;
    PORT
      LAYER M4 ;
        RECT 356.3160 336.7200 356.4000 336.7440 ;
    END
  END wl_d[218]
  PIN wl_d[219]
    DIRECTION INPUT ;
    USE SIGNAL ;
    PORT
      LAYER M4 ;
        RECT 356.3160 337.0560 356.4000 337.0800 ;
    END
  END wl_d[219]
  PIN wl_d[21]
    DIRECTION INPUT ;
    USE SIGNAL ;
    PORT
      LAYER M4 ;
        RECT 356.3160 267.4080 356.4000 267.4320 ;
    END
  END wl_d[21]
  PIN wl_d[220]
    DIRECTION INPUT ;
    USE SIGNAL ;
    PORT
      LAYER M4 ;
        RECT 356.3160 337.4400 356.4000 337.4640 ;
    END
  END wl_d[220]
  PIN wl_d[221]
    DIRECTION INPUT ;
    USE SIGNAL ;
    PORT
      LAYER M4 ;
        RECT 356.3160 337.7760 356.4000 337.8000 ;
    END
  END wl_d[221]
  PIN wl_d[222]
    DIRECTION INPUT ;
    USE SIGNAL ;
    PORT
      LAYER M4 ;
        RECT 356.3160 338.1120 356.4000 338.1360 ;
    END
  END wl_d[222]
  PIN wl_d[223]
    DIRECTION INPUT ;
    USE SIGNAL ;
    PORT
      LAYER M4 ;
        RECT 356.3160 338.4960 356.4000 338.5200 ;
    END
  END wl_d[223]
  PIN wl_d[224]
    DIRECTION INPUT ;
    USE SIGNAL ;
    PORT
      LAYER M4 ;
        RECT 356.3160 338.8320 356.4000 338.8560 ;
    END
  END wl_d[224]
  PIN wl_d[225]
    DIRECTION INPUT ;
    USE SIGNAL ;
    PORT
      LAYER M4 ;
        RECT 356.3160 339.1680 356.4000 339.1920 ;
    END
  END wl_d[225]
  PIN wl_d[226]
    DIRECTION INPUT ;
    USE SIGNAL ;
    PORT
      LAYER M4 ;
        RECT 356.3160 339.5520 356.4000 339.5760 ;
    END
  END wl_d[226]
  PIN wl_d[227]
    DIRECTION INPUT ;
    USE SIGNAL ;
    PORT
      LAYER M4 ;
        RECT 356.3160 339.8880 356.4000 339.9120 ;
    END
  END wl_d[227]
  PIN wl_d[228]
    DIRECTION INPUT ;
    USE SIGNAL ;
    PORT
      LAYER M4 ;
        RECT 356.3160 340.2240 356.4000 340.2480 ;
    END
  END wl_d[228]
  PIN wl_d[229]
    DIRECTION INPUT ;
    USE SIGNAL ;
    PORT
      LAYER M4 ;
        RECT 356.3160 340.6080 356.4000 340.6320 ;
    END
  END wl_d[229]
  PIN wl_d[22]
    DIRECTION INPUT ;
    USE SIGNAL ;
    PORT
      LAYER M4 ;
        RECT 356.3160 267.7440 356.4000 267.7680 ;
    END
  END wl_d[22]
  PIN wl_d[230]
    DIRECTION INPUT ;
    USE SIGNAL ;
    PORT
      LAYER M4 ;
        RECT 356.3160 340.9440 356.4000 340.9680 ;
    END
  END wl_d[230]
  PIN wl_d[231]
    DIRECTION INPUT ;
    USE SIGNAL ;
    PORT
      LAYER M4 ;
        RECT 356.3160 341.2800 356.4000 341.3040 ;
    END
  END wl_d[231]
  PIN wl_d[232]
    DIRECTION INPUT ;
    USE SIGNAL ;
    PORT
      LAYER M4 ;
        RECT 356.3160 341.6160 356.4000 341.6400 ;
    END
  END wl_d[232]
  PIN wl_d[233]
    DIRECTION INPUT ;
    USE SIGNAL ;
    PORT
      LAYER M4 ;
        RECT 356.3160 342.0000 356.4000 342.0240 ;
    END
  END wl_d[233]
  PIN wl_d[234]
    DIRECTION INPUT ;
    USE SIGNAL ;
    PORT
      LAYER M4 ;
        RECT 356.3160 342.3360 356.4000 342.3600 ;
    END
  END wl_d[234]
  PIN wl_d[235]
    DIRECTION INPUT ;
    USE SIGNAL ;
    PORT
      LAYER M4 ;
        RECT 356.3160 342.6720 356.4000 342.6960 ;
    END
  END wl_d[235]
  PIN wl_d[236]
    DIRECTION INPUT ;
    USE SIGNAL ;
    PORT
      LAYER M4 ;
        RECT 356.3160 343.0560 356.4000 343.0800 ;
    END
  END wl_d[236]
  PIN wl_d[237]
    DIRECTION INPUT ;
    USE SIGNAL ;
    PORT
      LAYER M4 ;
        RECT 356.3160 343.3920 356.4000 343.4160 ;
    END
  END wl_d[237]
  PIN wl_d[238]
    DIRECTION INPUT ;
    USE SIGNAL ;
    PORT
      LAYER M4 ;
        RECT 356.3160 343.7280 356.4000 343.7520 ;
    END
  END wl_d[238]
  PIN wl_d[239]
    DIRECTION INPUT ;
    USE SIGNAL ;
    PORT
      LAYER M4 ;
        RECT 356.3160 344.1120 356.4000 344.1360 ;
    END
  END wl_d[239]
  PIN wl_d[23]
    DIRECTION INPUT ;
    USE SIGNAL ;
    PORT
      LAYER M4 ;
        RECT 356.3160 268.0800 356.4000 268.1040 ;
    END
  END wl_d[23]
  PIN wl_d[240]
    DIRECTION INPUT ;
    USE SIGNAL ;
    PORT
      LAYER M4 ;
        RECT 356.3160 344.4480 356.4000 344.4720 ;
    END
  END wl_d[240]
  PIN wl_d[241]
    DIRECTION INPUT ;
    USE SIGNAL ;
    PORT
      LAYER M4 ;
        RECT 356.3160 344.7840 356.4000 344.8080 ;
    END
  END wl_d[241]
  PIN wl_d[242]
    DIRECTION INPUT ;
    USE SIGNAL ;
    PORT
      LAYER M4 ;
        RECT 356.3160 345.1680 356.4000 345.1920 ;
    END
  END wl_d[242]
  PIN wl_d[243]
    DIRECTION INPUT ;
    USE SIGNAL ;
    PORT
      LAYER M4 ;
        RECT 356.3160 345.5040 356.4000 345.5280 ;
    END
  END wl_d[243]
  PIN wl_d[244]
    DIRECTION INPUT ;
    USE SIGNAL ;
    PORT
      LAYER M4 ;
        RECT 356.3160 345.8400 356.4000 345.8640 ;
    END
  END wl_d[244]
  PIN wl_d[245]
    DIRECTION INPUT ;
    USE SIGNAL ;
    PORT
      LAYER M4 ;
        RECT 356.3160 346.2240 356.4000 346.2480 ;
    END
  END wl_d[245]
  PIN wl_d[246]
    DIRECTION INPUT ;
    USE SIGNAL ;
    PORT
      LAYER M4 ;
        RECT 356.3160 346.5600 356.4000 346.5840 ;
    END
  END wl_d[246]
  PIN wl_d[247]
    DIRECTION INPUT ;
    USE SIGNAL ;
    PORT
      LAYER M4 ;
        RECT 356.3160 346.8960 356.4000 346.9200 ;
    END
  END wl_d[247]
  PIN wl_d[248]
    DIRECTION INPUT ;
    USE SIGNAL ;
    PORT
      LAYER M4 ;
        RECT 356.3160 347.2800 356.4000 347.3040 ;
    END
  END wl_d[248]
  PIN wl_d[249]
    DIRECTION INPUT ;
    USE SIGNAL ;
    PORT
      LAYER M4 ;
        RECT 356.3160 347.6160 356.4000 347.6400 ;
    END
  END wl_d[249]
  PIN wl_d[24]
    DIRECTION INPUT ;
    USE SIGNAL ;
    PORT
      LAYER M4 ;
        RECT 356.3160 268.4640 356.4000 268.4880 ;
    END
  END wl_d[24]
  PIN wl_d[250]
    DIRECTION INPUT ;
    USE SIGNAL ;
    PORT
      LAYER M4 ;
        RECT 356.3160 347.9520 356.4000 347.9760 ;
    END
  END wl_d[250]
  PIN wl_d[251]
    DIRECTION INPUT ;
    USE SIGNAL ;
    PORT
      LAYER M4 ;
        RECT 356.3160 348.3360 356.4000 348.3600 ;
    END
  END wl_d[251]
  PIN wl_d[252]
    DIRECTION INPUT ;
    USE SIGNAL ;
    PORT
      LAYER M4 ;
        RECT 356.3160 348.6720 356.4000 348.6960 ;
    END
  END wl_d[252]
  PIN wl_d[253]
    DIRECTION INPUT ;
    USE SIGNAL ;
    PORT
      LAYER M4 ;
        RECT 356.3160 349.0080 356.4000 349.0320 ;
    END
  END wl_d[253]
  PIN wl_d[254]
    DIRECTION INPUT ;
    USE SIGNAL ;
    PORT
      LAYER M4 ;
        RECT 356.3160 349.3920 356.4000 349.4160 ;
    END
  END wl_d[254]
  PIN wl_d[255]
    DIRECTION INPUT ;
    USE SIGNAL ;
    PORT
      LAYER M4 ;
        RECT 356.3160 349.7280 356.4000 349.7520 ;
    END
  END wl_d[255]
  PIN wl_d[25]
    DIRECTION INPUT ;
    USE SIGNAL ;
    PORT
      LAYER M4 ;
        RECT 356.3160 268.8000 356.4000 268.8240 ;
    END
  END wl_d[25]
  PIN wl_d[26]
    DIRECTION INPUT ;
    USE SIGNAL ;
    PORT
      LAYER M4 ;
        RECT 356.3160 269.1360 356.4000 269.1600 ;
    END
  END wl_d[26]
  PIN wl_d[27]
    DIRECTION INPUT ;
    USE SIGNAL ;
    PORT
      LAYER M4 ;
        RECT 356.3160 269.5200 356.4000 269.5440 ;
    END
  END wl_d[27]
  PIN wl_d[28]
    DIRECTION INPUT ;
    USE SIGNAL ;
    PORT
      LAYER M4 ;
        RECT 356.3160 269.8560 356.4000 269.8800 ;
    END
  END wl_d[28]
  PIN wl_d[29]
    DIRECTION INPUT ;
    USE SIGNAL ;
    PORT
      LAYER M4 ;
        RECT 356.3160 270.1920 356.4000 270.2160 ;
    END
  END wl_d[29]
  PIN wl_d[2]
    DIRECTION INPUT ;
    USE SIGNAL ;
    PORT
      LAYER M4 ;
        RECT 356.3160 260.7360 356.4000 260.7600 ;
    END
  END wl_d[2]
  PIN wl_d[30]
    DIRECTION INPUT ;
    USE SIGNAL ;
    PORT
      LAYER M4 ;
        RECT 356.3160 270.5760 356.4000 270.6000 ;
    END
  END wl_d[30]
  PIN wl_d[31]
    DIRECTION INPUT ;
    USE SIGNAL ;
    PORT
      LAYER M4 ;
        RECT 356.3160 270.9120 356.4000 270.9360 ;
    END
  END wl_d[31]
  PIN wl_d[32]
    DIRECTION INPUT ;
    USE SIGNAL ;
    PORT
      LAYER M4 ;
        RECT 356.3160 271.2480 356.4000 271.2720 ;
    END
  END wl_d[32]
  PIN wl_d[33]
    DIRECTION INPUT ;
    USE SIGNAL ;
    PORT
      LAYER M4 ;
        RECT 356.3160 271.6320 356.4000 271.6560 ;
    END
  END wl_d[33]
  PIN wl_d[34]
    DIRECTION INPUT ;
    USE SIGNAL ;
    PORT
      LAYER M4 ;
        RECT 356.3160 271.9680 356.4000 271.9920 ;
    END
  END wl_d[34]
  PIN wl_d[35]
    DIRECTION INPUT ;
    USE SIGNAL ;
    PORT
      LAYER M4 ;
        RECT 356.3160 272.3040 356.4000 272.3280 ;
    END
  END wl_d[35]
  PIN wl_d[36]
    DIRECTION INPUT ;
    USE SIGNAL ;
    PORT
      LAYER M4 ;
        RECT 356.3160 272.6880 356.4000 272.7120 ;
    END
  END wl_d[36]
  PIN wl_d[37]
    DIRECTION INPUT ;
    USE SIGNAL ;
    PORT
      LAYER M4 ;
        RECT 356.3160 273.0240 356.4000 273.0480 ;
    END
  END wl_d[37]
  PIN wl_d[38]
    DIRECTION INPUT ;
    USE SIGNAL ;
    PORT
      LAYER M4 ;
        RECT 356.3160 273.3600 356.4000 273.3840 ;
    END
  END wl_d[38]
  PIN wl_d[39]
    DIRECTION INPUT ;
    USE SIGNAL ;
    PORT
      LAYER M4 ;
        RECT 356.3160 273.7440 356.4000 273.7680 ;
    END
  END wl_d[39]
  PIN wl_d[3]
    DIRECTION INPUT ;
    USE SIGNAL ;
    PORT
      LAYER M4 ;
        RECT 356.3160 261.0720 356.4000 261.0960 ;
    END
  END wl_d[3]
  PIN wl_d[40]
    DIRECTION INPUT ;
    USE SIGNAL ;
    PORT
      LAYER M4 ;
        RECT 356.3160 274.0800 356.4000 274.1040 ;
    END
  END wl_d[40]
  PIN wl_d[41]
    DIRECTION INPUT ;
    USE SIGNAL ;
    PORT
      LAYER M4 ;
        RECT 356.3160 274.4160 356.4000 274.4400 ;
    END
  END wl_d[41]
  PIN wl_d[42]
    DIRECTION INPUT ;
    USE SIGNAL ;
    PORT
      LAYER M4 ;
        RECT 356.3160 274.8000 356.4000 274.8240 ;
    END
  END wl_d[42]
  PIN wl_d[43]
    DIRECTION INPUT ;
    USE SIGNAL ;
    PORT
      LAYER M4 ;
        RECT 356.3160 275.1360 356.4000 275.1600 ;
    END
  END wl_d[43]
  PIN wl_d[44]
    DIRECTION INPUT ;
    USE SIGNAL ;
    PORT
      LAYER M4 ;
        RECT 356.3160 275.4720 356.4000 275.4960 ;
    END
  END wl_d[44]
  PIN wl_d[45]
    DIRECTION INPUT ;
    USE SIGNAL ;
    PORT
      LAYER M4 ;
        RECT 356.3160 275.8560 356.4000 275.8800 ;
    END
  END wl_d[45]
  PIN wl_d[46]
    DIRECTION INPUT ;
    USE SIGNAL ;
    PORT
      LAYER M4 ;
        RECT 356.3160 276.1920 356.4000 276.2160 ;
    END
  END wl_d[46]
  PIN wl_d[47]
    DIRECTION INPUT ;
    USE SIGNAL ;
    PORT
      LAYER M4 ;
        RECT 356.3160 276.5280 356.4000 276.5520 ;
    END
  END wl_d[47]
  PIN wl_d[48]
    DIRECTION INPUT ;
    USE SIGNAL ;
    PORT
      LAYER M4 ;
        RECT 356.3160 276.9120 356.4000 276.9360 ;
    END
  END wl_d[48]
  PIN wl_d[49]
    DIRECTION INPUT ;
    USE SIGNAL ;
    PORT
      LAYER M4 ;
        RECT 356.3160 277.2480 356.4000 277.2720 ;
    END
  END wl_d[49]
  PIN wl_d[4]
    DIRECTION INPUT ;
    USE SIGNAL ;
    PORT
      LAYER M4 ;
        RECT 356.3160 261.4080 356.4000 261.4320 ;
    END
  END wl_d[4]
  PIN wl_d[50]
    DIRECTION INPUT ;
    USE SIGNAL ;
    PORT
      LAYER M4 ;
        RECT 356.3160 277.5840 356.4000 277.6080 ;
    END
  END wl_d[50]
  PIN wl_d[51]
    DIRECTION INPUT ;
    USE SIGNAL ;
    PORT
      LAYER M4 ;
        RECT 356.3160 277.9680 356.4000 277.9920 ;
    END
  END wl_d[51]
  PIN wl_d[52]
    DIRECTION INPUT ;
    USE SIGNAL ;
    PORT
      LAYER M4 ;
        RECT 356.3160 278.3040 356.4000 278.3280 ;
    END
  END wl_d[52]
  PIN wl_d[53]
    DIRECTION INPUT ;
    USE SIGNAL ;
    PORT
      LAYER M4 ;
        RECT 356.3160 278.6400 356.4000 278.6640 ;
    END
  END wl_d[53]
  PIN wl_d[54]
    DIRECTION INPUT ;
    USE SIGNAL ;
    PORT
      LAYER M4 ;
        RECT 356.3160 279.0240 356.4000 279.0480 ;
    END
  END wl_d[54]
  PIN wl_d[55]
    DIRECTION INPUT ;
    USE SIGNAL ;
    PORT
      LAYER M4 ;
        RECT 356.3160 279.3600 356.4000 279.3840 ;
    END
  END wl_d[55]
  PIN wl_d[56]
    DIRECTION INPUT ;
    USE SIGNAL ;
    PORT
      LAYER M4 ;
        RECT 356.3160 279.6960 356.4000 279.7200 ;
    END
  END wl_d[56]
  PIN wl_d[57]
    DIRECTION INPUT ;
    USE SIGNAL ;
    PORT
      LAYER M4 ;
        RECT 356.3160 280.0800 356.4000 280.1040 ;
    END
  END wl_d[57]
  PIN wl_d[58]
    DIRECTION INPUT ;
    USE SIGNAL ;
    PORT
      LAYER M4 ;
        RECT 356.3160 280.4160 356.4000 280.4400 ;
    END
  END wl_d[58]
  PIN wl_d[59]
    DIRECTION INPUT ;
    USE SIGNAL ;
    PORT
      LAYER M4 ;
        RECT 356.3160 280.7520 356.4000 280.7760 ;
    END
  END wl_d[59]
  PIN wl_d[5]
    DIRECTION INPUT ;
    USE SIGNAL ;
    PORT
      LAYER M4 ;
        RECT 356.3160 261.7440 356.4000 261.7680 ;
    END
  END wl_d[5]
  PIN wl_d[60]
    DIRECTION INPUT ;
    USE SIGNAL ;
    PORT
      LAYER M4 ;
        RECT 356.3160 281.1360 356.4000 281.1600 ;
    END
  END wl_d[60]
  PIN wl_d[61]
    DIRECTION INPUT ;
    USE SIGNAL ;
    PORT
      LAYER M4 ;
        RECT 356.3160 281.4720 356.4000 281.4960 ;
    END
  END wl_d[61]
  PIN wl_d[62]
    DIRECTION INPUT ;
    USE SIGNAL ;
    PORT
      LAYER M4 ;
        RECT 356.3160 281.8080 356.4000 281.8320 ;
    END
  END wl_d[62]
  PIN wl_d[63]
    DIRECTION INPUT ;
    USE SIGNAL ;
    PORT
      LAYER M4 ;
        RECT 356.3160 282.1920 356.4000 282.2160 ;
    END
  END wl_d[63]
  PIN wl_d[64]
    DIRECTION INPUT ;
    USE SIGNAL ;
    PORT
      LAYER M4 ;
        RECT 356.3160 282.5280 356.4000 282.5520 ;
    END
  END wl_d[64]
  PIN wl_d[65]
    DIRECTION INPUT ;
    USE SIGNAL ;
    PORT
      LAYER M4 ;
        RECT 356.3160 282.8640 356.4000 282.8880 ;
    END
  END wl_d[65]
  PIN wl_d[66]
    DIRECTION INPUT ;
    USE SIGNAL ;
    PORT
      LAYER M4 ;
        RECT 356.3160 283.2480 356.4000 283.2720 ;
    END
  END wl_d[66]
  PIN wl_d[67]
    DIRECTION INPUT ;
    USE SIGNAL ;
    PORT
      LAYER M4 ;
        RECT 356.3160 283.5840 356.4000 283.6080 ;
    END
  END wl_d[67]
  PIN wl_d[68]
    DIRECTION INPUT ;
    USE SIGNAL ;
    PORT
      LAYER M4 ;
        RECT 356.3160 283.9200 356.4000 283.9440 ;
    END
  END wl_d[68]
  PIN wl_d[69]
    DIRECTION INPUT ;
    USE SIGNAL ;
    PORT
      LAYER M4 ;
        RECT 356.3160 284.3040 356.4000 284.3280 ;
    END
  END wl_d[69]
  PIN wl_d[6]
    DIRECTION INPUT ;
    USE SIGNAL ;
    PORT
      LAYER M4 ;
        RECT 356.3160 262.1280 356.4000 262.1520 ;
    END
  END wl_d[6]
  PIN wl_d[70]
    DIRECTION INPUT ;
    USE SIGNAL ;
    PORT
      LAYER M4 ;
        RECT 356.3160 284.6400 356.4000 284.6640 ;
    END
  END wl_d[70]
  PIN wl_d[71]
    DIRECTION INPUT ;
    USE SIGNAL ;
    PORT
      LAYER M4 ;
        RECT 356.3160 284.9760 356.4000 285.0000 ;
    END
  END wl_d[71]
  PIN wl_d[72]
    DIRECTION INPUT ;
    USE SIGNAL ;
    PORT
      LAYER M4 ;
        RECT 356.3160 285.3600 356.4000 285.3840 ;
    END
  END wl_d[72]
  PIN wl_d[73]
    DIRECTION INPUT ;
    USE SIGNAL ;
    PORT
      LAYER M4 ;
        RECT 356.3160 285.6960 356.4000 285.7200 ;
    END
  END wl_d[73]
  PIN wl_d[74]
    DIRECTION INPUT ;
    USE SIGNAL ;
    PORT
      LAYER M4 ;
        RECT 356.3160 286.0320 356.4000 286.0560 ;
    END
  END wl_d[74]
  PIN wl_d[75]
    DIRECTION INPUT ;
    USE SIGNAL ;
    PORT
      LAYER M4 ;
        RECT 356.3160 286.4160 356.4000 286.4400 ;
    END
  END wl_d[75]
  PIN wl_d[76]
    DIRECTION INPUT ;
    USE SIGNAL ;
    PORT
      LAYER M4 ;
        RECT 356.3160 286.7520 356.4000 286.7760 ;
    END
  END wl_d[76]
  PIN wl_d[77]
    DIRECTION INPUT ;
    USE SIGNAL ;
    PORT
      LAYER M4 ;
        RECT 356.3160 287.0880 356.4000 287.1120 ;
    END
  END wl_d[77]
  PIN wl_d[78]
    DIRECTION INPUT ;
    USE SIGNAL ;
    PORT
      LAYER M4 ;
        RECT 356.3160 287.4720 356.4000 287.4960 ;
    END
  END wl_d[78]
  PIN wl_d[79]
    DIRECTION INPUT ;
    USE SIGNAL ;
    PORT
      LAYER M4 ;
        RECT 356.3160 287.8080 356.4000 287.8320 ;
    END
  END wl_d[79]
  PIN wl_d[7]
    DIRECTION INPUT ;
    USE SIGNAL ;
    PORT
      LAYER M4 ;
        RECT 356.3160 262.4640 356.4000 262.4880 ;
    END
  END wl_d[7]
  PIN wl_d[80]
    DIRECTION INPUT ;
    USE SIGNAL ;
    PORT
      LAYER M4 ;
        RECT 356.3160 288.1440 356.4000 288.1680 ;
    END
  END wl_d[80]
  PIN wl_d[81]
    DIRECTION INPUT ;
    USE SIGNAL ;
    PORT
      LAYER M4 ;
        RECT 356.3160 288.5280 356.4000 288.5520 ;
    END
  END wl_d[81]
  PIN wl_d[82]
    DIRECTION INPUT ;
    USE SIGNAL ;
    PORT
      LAYER M4 ;
        RECT 356.3160 288.8640 356.4000 288.8880 ;
    END
  END wl_d[82]
  PIN wl_d[83]
    DIRECTION INPUT ;
    USE SIGNAL ;
    PORT
      LAYER M4 ;
        RECT 356.3160 289.2000 356.4000 289.2240 ;
    END
  END wl_d[83]
  PIN wl_d[84]
    DIRECTION INPUT ;
    USE SIGNAL ;
    PORT
      LAYER M4 ;
        RECT 356.3160 289.5840 356.4000 289.6080 ;
    END
  END wl_d[84]
  PIN wl_d[85]
    DIRECTION INPUT ;
    USE SIGNAL ;
    PORT
      LAYER M4 ;
        RECT 356.3160 289.9200 356.4000 289.9440 ;
    END
  END wl_d[85]
  PIN wl_d[86]
    DIRECTION INPUT ;
    USE SIGNAL ;
    PORT
      LAYER M4 ;
        RECT 356.3160 290.2560 356.4000 290.2800 ;
    END
  END wl_d[86]
  PIN wl_d[87]
    DIRECTION INPUT ;
    USE SIGNAL ;
    PORT
      LAYER M4 ;
        RECT 356.3160 290.6400 356.4000 290.6640 ;
    END
  END wl_d[87]
  PIN wl_d[88]
    DIRECTION INPUT ;
    USE SIGNAL ;
    PORT
      LAYER M4 ;
        RECT 356.3160 290.9760 356.4000 291.0000 ;
    END
  END wl_d[88]
  PIN wl_d[89]
    DIRECTION INPUT ;
    USE SIGNAL ;
    PORT
      LAYER M4 ;
        RECT 356.3160 291.3120 356.4000 291.3360 ;
    END
  END wl_d[89]
  PIN wl_d[8]
    DIRECTION INPUT ;
    USE SIGNAL ;
    PORT
      LAYER M4 ;
        RECT 356.3160 262.8000 356.4000 262.8240 ;
    END
  END wl_d[8]
  PIN wl_d[90]
    DIRECTION INPUT ;
    USE SIGNAL ;
    PORT
      LAYER M4 ;
        RECT 356.3160 291.6960 356.4000 291.7200 ;
    END
  END wl_d[90]
  PIN wl_d[91]
    DIRECTION INPUT ;
    USE SIGNAL ;
    PORT
      LAYER M4 ;
        RECT 356.3160 292.0320 356.4000 292.0560 ;
    END
  END wl_d[91]
  PIN wl_d[92]
    DIRECTION INPUT ;
    USE SIGNAL ;
    PORT
      LAYER M4 ;
        RECT 356.3160 292.3680 356.4000 292.3920 ;
    END
  END wl_d[92]
  PIN wl_d[93]
    DIRECTION INPUT ;
    USE SIGNAL ;
    PORT
      LAYER M4 ;
        RECT 356.3160 292.7520 356.4000 292.7760 ;
    END
  END wl_d[93]
  PIN wl_d[94]
    DIRECTION INPUT ;
    USE SIGNAL ;
    PORT
      LAYER M4 ;
        RECT 356.3160 293.0880 356.4000 293.1120 ;
    END
  END wl_d[94]
  PIN wl_d[95]
    DIRECTION INPUT ;
    USE SIGNAL ;
    PORT
      LAYER M4 ;
        RECT 356.3160 293.4240 356.4000 293.4480 ;
    END
  END wl_d[95]
  PIN wl_d[96]
    DIRECTION INPUT ;
    USE SIGNAL ;
    PORT
      LAYER M4 ;
        RECT 356.3160 293.8080 356.4000 293.8320 ;
    END
  END wl_d[96]
  PIN wl_d[97]
    DIRECTION INPUT ;
    USE SIGNAL ;
    PORT
      LAYER M4 ;
        RECT 356.3160 294.1440 356.4000 294.1680 ;
    END
  END wl_d[97]
  PIN wl_d[98]
    DIRECTION INPUT ;
    USE SIGNAL ;
    PORT
      LAYER M4 ;
        RECT 356.3160 294.4800 356.4000 294.5040 ;
    END
  END wl_d[98]
  PIN wl_d[99]
    DIRECTION INPUT ;
    USE SIGNAL ;
    PORT
      LAYER M4 ;
        RECT 356.3160 294.8640 356.4000 294.8880 ;
    END
  END wl_d[99]
  PIN wl_d[9]
    DIRECTION INPUT ;
    USE SIGNAL ;
    PORT
      LAYER M4 ;
        RECT 356.3160 263.1840 356.4000 263.2080 ;
    END
  END wl_d[9]
  PIN wl_i[0]
    DIRECTION INPUT ;
    USE SIGNAL ;
    PORT
      LAYER M4 ;
        RECT 355.1240 257.1840 355.2080 257.2080 ;
    END
  END wl_i[0]
  PIN wl_i[1]
    DIRECTION INPUT ;
    USE SIGNAL ;
    PORT
      LAYER M4 ;
        RECT 355.1240 258.2400 355.2080 258.2640 ;
    END
  END wl_i[1]
  PIN wl_i[2]
    DIRECTION INPUT ;
    USE SIGNAL ;
    PORT
      LAYER M4 ;
        RECT 356.3160 259.2960 356.4000 259.3200 ;
    END
  END wl_i[2]
  PIN wl_v
    DIRECTION INPUT ;
    USE SIGNAL ;
    PORT
      LAYER M4 ;
        RECT 356.3160 255.4080 356.4000 255.4320 ;
    END
  END wl_v
  PIN y[0]
    DIRECTION OUTPUT ;
    USE SIGNAL ;
    PORT
      LAYER M4 ;
        RECT 0.0000 13.0560 0.0840 13.0800 ;
    END
  END y[0]
  PIN y[100]
    DIRECTION OUTPUT ;
    USE SIGNAL ;
    PORT
      LAYER M4 ;
        RECT 0.0000 36.6720 0.0840 36.6960 ;
    END
  END y[100]
  PIN y[101]
    DIRECTION OUTPUT ;
    USE SIGNAL ;
    PORT
      LAYER M4 ;
        RECT 0.0000 36.9120 0.0840 36.9360 ;
    END
  END y[101]
  PIN y[102]
    DIRECTION OUTPUT ;
    USE SIGNAL ;
    PORT
      LAYER M4 ;
        RECT 0.0000 37.1520 0.0840 37.1760 ;
    END
  END y[102]
  PIN y[103]
    DIRECTION OUTPUT ;
    USE SIGNAL ;
    PORT
      LAYER M4 ;
        RECT 0.0000 37.3920 0.0840 37.4160 ;
    END
  END y[103]
  PIN y[104]
    DIRECTION OUTPUT ;
    USE SIGNAL ;
    PORT
      LAYER M4 ;
        RECT 0.0000 37.6320 0.0840 37.6560 ;
    END
  END y[104]
  PIN y[105]
    DIRECTION OUTPUT ;
    USE SIGNAL ;
    PORT
      LAYER M4 ;
        RECT 0.0000 37.8720 0.0840 37.8960 ;
    END
  END y[105]
  PIN y[106]
    DIRECTION OUTPUT ;
    USE SIGNAL ;
    PORT
      LAYER M4 ;
        RECT 0.0000 38.1120 0.0840 38.1360 ;
    END
  END y[106]
  PIN y[107]
    DIRECTION OUTPUT ;
    USE SIGNAL ;
    PORT
      LAYER M4 ;
        RECT 0.0000 38.3520 0.0840 38.3760 ;
    END
  END y[107]
  PIN y[108]
    DIRECTION OUTPUT ;
    USE SIGNAL ;
    PORT
      LAYER M4 ;
        RECT 0.0000 38.5920 0.0840 38.6160 ;
    END
  END y[108]
  PIN y[109]
    DIRECTION OUTPUT ;
    USE SIGNAL ;
    PORT
      LAYER M4 ;
        RECT 0.0000 38.8320 0.0840 38.8560 ;
    END
  END y[109]
  PIN y[10]
    DIRECTION OUTPUT ;
    USE SIGNAL ;
    PORT
      LAYER M4 ;
        RECT 0.0000 15.4080 0.0840 15.4320 ;
    END
  END y[10]
  PIN y[110]
    DIRECTION OUTPUT ;
    USE SIGNAL ;
    PORT
      LAYER M4 ;
        RECT 0.0000 39.0720 0.0840 39.0960 ;
    END
  END y[110]
  PIN y[111]
    DIRECTION OUTPUT ;
    USE SIGNAL ;
    PORT
      LAYER M4 ;
        RECT 0.0000 39.3120 0.0840 39.3360 ;
    END
  END y[111]
  PIN y[112]
    DIRECTION OUTPUT ;
    USE SIGNAL ;
    PORT
      LAYER M4 ;
        RECT 0.0000 39.5040 0.0840 39.5280 ;
    END
  END y[112]
  PIN y[113]
    DIRECTION OUTPUT ;
    USE SIGNAL ;
    PORT
      LAYER M4 ;
        RECT 0.0000 39.7440 0.0840 39.7680 ;
    END
  END y[113]
  PIN y[114]
    DIRECTION OUTPUT ;
    USE SIGNAL ;
    PORT
      LAYER M4 ;
        RECT 0.0000 39.9840 0.0840 40.0080 ;
    END
  END y[114]
  PIN y[115]
    DIRECTION OUTPUT ;
    USE SIGNAL ;
    PORT
      LAYER M4 ;
        RECT 0.0000 40.2240 0.0840 40.2480 ;
    END
  END y[115]
  PIN y[116]
    DIRECTION OUTPUT ;
    USE SIGNAL ;
    PORT
      LAYER M4 ;
        RECT 0.0000 40.4640 0.0840 40.4880 ;
    END
  END y[116]
  PIN y[117]
    DIRECTION OUTPUT ;
    USE SIGNAL ;
    PORT
      LAYER M4 ;
        RECT 0.0000 40.7040 0.0840 40.7280 ;
    END
  END y[117]
  PIN y[118]
    DIRECTION OUTPUT ;
    USE SIGNAL ;
    PORT
      LAYER M4 ;
        RECT 0.0000 40.9440 0.0840 40.9680 ;
    END
  END y[118]
  PIN y[119]
    DIRECTION OUTPUT ;
    USE SIGNAL ;
    PORT
      LAYER M4 ;
        RECT 0.0000 41.1840 0.0840 41.2080 ;
    END
  END y[119]
  PIN y[11]
    DIRECTION OUTPUT ;
    USE SIGNAL ;
    PORT
      LAYER M4 ;
        RECT 0.0000 15.6480 0.0840 15.6720 ;
    END
  END y[11]
  PIN y[120]
    DIRECTION OUTPUT ;
    USE SIGNAL ;
    PORT
      LAYER M4 ;
        RECT 0.0000 41.4240 0.0840 41.4480 ;
    END
  END y[120]
  PIN y[121]
    DIRECTION OUTPUT ;
    USE SIGNAL ;
    PORT
      LAYER M4 ;
        RECT 0.0000 41.6640 0.0840 41.6880 ;
    END
  END y[121]
  PIN y[122]
    DIRECTION OUTPUT ;
    USE SIGNAL ;
    PORT
      LAYER M4 ;
        RECT 0.0000 41.9040 0.0840 41.9280 ;
    END
  END y[122]
  PIN y[123]
    DIRECTION OUTPUT ;
    USE SIGNAL ;
    PORT
      LAYER M4 ;
        RECT 0.0000 42.1440 0.0840 42.1680 ;
    END
  END y[123]
  PIN y[124]
    DIRECTION OUTPUT ;
    USE SIGNAL ;
    PORT
      LAYER M4 ;
        RECT 0.0000 42.3840 0.0840 42.4080 ;
    END
  END y[124]
  PIN y[125]
    DIRECTION OUTPUT ;
    USE SIGNAL ;
    PORT
      LAYER M4 ;
        RECT 0.0000 42.5760 0.0840 42.6000 ;
    END
  END y[125]
  PIN y[126]
    DIRECTION OUTPUT ;
    USE SIGNAL ;
    PORT
      LAYER M4 ;
        RECT 0.0000 42.8160 0.0840 42.8400 ;
    END
  END y[126]
  PIN y[127]
    DIRECTION OUTPUT ;
    USE SIGNAL ;
    PORT
      LAYER M4 ;
        RECT 0.0000 43.0560 0.0840 43.0800 ;
    END
  END y[127]
  PIN y[128]
    DIRECTION OUTPUT ;
    USE SIGNAL ;
    PORT
      LAYER M4 ;
        RECT 0.0000 43.2960 0.0840 43.3200 ;
    END
  END y[128]
  PIN y[129]
    DIRECTION OUTPUT ;
    USE SIGNAL ;
    PORT
      LAYER M4 ;
        RECT 0.0000 43.5360 0.0840 43.5600 ;
    END
  END y[129]
  PIN y[12]
    DIRECTION OUTPUT ;
    USE SIGNAL ;
    PORT
      LAYER M4 ;
        RECT 0.0000 15.8880 0.0840 15.9120 ;
    END
  END y[12]
  PIN y[130]
    DIRECTION OUTPUT ;
    USE SIGNAL ;
    PORT
      LAYER M4 ;
        RECT 0.0000 43.7760 0.0840 43.8000 ;
    END
  END y[130]
  PIN y[131]
    DIRECTION OUTPUT ;
    USE SIGNAL ;
    PORT
      LAYER M4 ;
        RECT 0.0000 44.0160 0.0840 44.0400 ;
    END
  END y[131]
  PIN y[132]
    DIRECTION OUTPUT ;
    USE SIGNAL ;
    PORT
      LAYER M4 ;
        RECT 0.0000 44.2560 0.0840 44.2800 ;
    END
  END y[132]
  PIN y[133]
    DIRECTION OUTPUT ;
    USE SIGNAL ;
    PORT
      LAYER M4 ;
        RECT 0.0000 44.4960 0.0840 44.5200 ;
    END
  END y[133]
  PIN y[134]
    DIRECTION OUTPUT ;
    USE SIGNAL ;
    PORT
      LAYER M4 ;
        RECT 0.0000 44.7360 0.0840 44.7600 ;
    END
  END y[134]
  PIN y[135]
    DIRECTION OUTPUT ;
    USE SIGNAL ;
    PORT
      LAYER M4 ;
        RECT 0.0000 44.9760 0.0840 45.0000 ;
    END
  END y[135]
  PIN y[136]
    DIRECTION OUTPUT ;
    USE SIGNAL ;
    PORT
      LAYER M4 ;
        RECT 0.0000 45.2160 0.0840 45.2400 ;
    END
  END y[136]
  PIN y[137]
    DIRECTION OUTPUT ;
    USE SIGNAL ;
    PORT
      LAYER M4 ;
        RECT 0.0000 45.4560 0.0840 45.4800 ;
    END
  END y[137]
  PIN y[138]
    DIRECTION OUTPUT ;
    USE SIGNAL ;
    PORT
      LAYER M4 ;
        RECT 0.0000 45.6480 0.0840 45.6720 ;
    END
  END y[138]
  PIN y[139]
    DIRECTION OUTPUT ;
    USE SIGNAL ;
    PORT
      LAYER M4 ;
        RECT 0.0000 45.8880 0.0840 45.9120 ;
    END
  END y[139]
  PIN y[13]
    DIRECTION OUTPUT ;
    USE SIGNAL ;
    PORT
      LAYER M4 ;
        RECT 0.0000 16.1280 0.0840 16.1520 ;
    END
  END y[13]
  PIN y[140]
    DIRECTION OUTPUT ;
    USE SIGNAL ;
    PORT
      LAYER M4 ;
        RECT 0.0000 46.1280 0.0840 46.1520 ;
    END
  END y[140]
  PIN y[141]
    DIRECTION OUTPUT ;
    USE SIGNAL ;
    PORT
      LAYER M4 ;
        RECT 0.0000 46.3680 0.0840 46.3920 ;
    END
  END y[141]
  PIN y[142]
    DIRECTION OUTPUT ;
    USE SIGNAL ;
    PORT
      LAYER M4 ;
        RECT 0.0000 46.6080 0.0840 46.6320 ;
    END
  END y[142]
  PIN y[143]
    DIRECTION OUTPUT ;
    USE SIGNAL ;
    PORT
      LAYER M4 ;
        RECT 0.0000 46.8480 0.0840 46.8720 ;
    END
  END y[143]
  PIN y[144]
    DIRECTION OUTPUT ;
    USE SIGNAL ;
    PORT
      LAYER M4 ;
        RECT 0.0000 47.0880 0.0840 47.1120 ;
    END
  END y[144]
  PIN y[145]
    DIRECTION OUTPUT ;
    USE SIGNAL ;
    PORT
      LAYER M4 ;
        RECT 0.0000 47.3280 0.0840 47.3520 ;
    END
  END y[145]
  PIN y[146]
    DIRECTION OUTPUT ;
    USE SIGNAL ;
    PORT
      LAYER M4 ;
        RECT 0.0000 47.5680 0.0840 47.5920 ;
    END
  END y[146]
  PIN y[147]
    DIRECTION OUTPUT ;
    USE SIGNAL ;
    PORT
      LAYER M4 ;
        RECT 0.0000 47.8080 0.0840 47.8320 ;
    END
  END y[147]
  PIN y[148]
    DIRECTION OUTPUT ;
    USE SIGNAL ;
    PORT
      LAYER M4 ;
        RECT 0.0000 48.0480 0.0840 48.0720 ;
    END
  END y[148]
  PIN y[149]
    DIRECTION OUTPUT ;
    USE SIGNAL ;
    PORT
      LAYER M4 ;
        RECT 0.0000 48.2880 0.0840 48.3120 ;
    END
  END y[149]
  PIN y[14]
    DIRECTION OUTPUT ;
    USE SIGNAL ;
    PORT
      LAYER M4 ;
        RECT 0.0000 16.3680 0.0840 16.3920 ;
    END
  END y[14]
  PIN y[150]
    DIRECTION OUTPUT ;
    USE SIGNAL ;
    PORT
      LAYER M4 ;
        RECT 0.0000 48.5280 0.0840 48.5520 ;
    END
  END y[150]
  PIN y[151]
    DIRECTION OUTPUT ;
    USE SIGNAL ;
    PORT
      LAYER M4 ;
        RECT 0.0000 48.7200 0.0840 48.7440 ;
    END
  END y[151]
  PIN y[152]
    DIRECTION OUTPUT ;
    USE SIGNAL ;
    PORT
      LAYER M4 ;
        RECT 0.0000 48.9600 0.0840 48.9840 ;
    END
  END y[152]
  PIN y[153]
    DIRECTION OUTPUT ;
    USE SIGNAL ;
    PORT
      LAYER M4 ;
        RECT 0.0000 49.2000 0.0840 49.2240 ;
    END
  END y[153]
  PIN y[154]
    DIRECTION OUTPUT ;
    USE SIGNAL ;
    PORT
      LAYER M4 ;
        RECT 0.0000 49.4400 0.0840 49.4640 ;
    END
  END y[154]
  PIN y[155]
    DIRECTION OUTPUT ;
    USE SIGNAL ;
    PORT
      LAYER M4 ;
        RECT 0.0000 49.6800 0.0840 49.7040 ;
    END
  END y[155]
  PIN y[156]
    DIRECTION OUTPUT ;
    USE SIGNAL ;
    PORT
      LAYER M4 ;
        RECT 0.0000 49.9200 0.0840 49.9440 ;
    END
  END y[156]
  PIN y[157]
    DIRECTION OUTPUT ;
    USE SIGNAL ;
    PORT
      LAYER M4 ;
        RECT 0.0000 50.1600 0.0840 50.1840 ;
    END
  END y[157]
  PIN y[158]
    DIRECTION OUTPUT ;
    USE SIGNAL ;
    PORT
      LAYER M4 ;
        RECT 0.0000 50.4000 0.0840 50.4240 ;
    END
  END y[158]
  PIN y[159]
    DIRECTION OUTPUT ;
    USE SIGNAL ;
    PORT
      LAYER M4 ;
        RECT 0.0000 50.6400 0.0840 50.6640 ;
    END
  END y[159]
  PIN y[15]
    DIRECTION OUTPUT ;
    USE SIGNAL ;
    PORT
      LAYER M4 ;
        RECT 0.0000 16.6080 0.0840 16.6320 ;
    END
  END y[15]
  PIN y[160]
    DIRECTION OUTPUT ;
    USE SIGNAL ;
    PORT
      LAYER M4 ;
        RECT 0.0000 50.8800 0.0840 50.9040 ;
    END
  END y[160]
  PIN y[161]
    DIRECTION OUTPUT ;
    USE SIGNAL ;
    PORT
      LAYER M4 ;
        RECT 0.0000 51.1200 0.0840 51.1440 ;
    END
  END y[161]
  PIN y[162]
    DIRECTION OUTPUT ;
    USE SIGNAL ;
    PORT
      LAYER M4 ;
        RECT 0.0000 51.3600 0.0840 51.3840 ;
    END
  END y[162]
  PIN y[163]
    DIRECTION OUTPUT ;
    USE SIGNAL ;
    PORT
      LAYER M4 ;
        RECT 0.0000 51.5520 0.0840 51.5760 ;
    END
  END y[163]
  PIN y[164]
    DIRECTION OUTPUT ;
    USE SIGNAL ;
    PORT
      LAYER M4 ;
        RECT 0.0000 51.7920 0.0840 51.8160 ;
    END
  END y[164]
  PIN y[165]
    DIRECTION OUTPUT ;
    USE SIGNAL ;
    PORT
      LAYER M4 ;
        RECT 0.0000 52.0320 0.0840 52.0560 ;
    END
  END y[165]
  PIN y[166]
    DIRECTION OUTPUT ;
    USE SIGNAL ;
    PORT
      LAYER M4 ;
        RECT 0.0000 52.2720 0.0840 52.2960 ;
    END
  END y[166]
  PIN y[167]
    DIRECTION OUTPUT ;
    USE SIGNAL ;
    PORT
      LAYER M4 ;
        RECT 0.0000 52.5120 0.0840 52.5360 ;
    END
  END y[167]
  PIN y[168]
    DIRECTION OUTPUT ;
    USE SIGNAL ;
    PORT
      LAYER M4 ;
        RECT 0.0000 52.7520 0.0840 52.7760 ;
    END
  END y[168]
  PIN y[169]
    DIRECTION OUTPUT ;
    USE SIGNAL ;
    PORT
      LAYER M4 ;
        RECT 0.0000 52.9920 0.0840 53.0160 ;
    END
  END y[169]
  PIN y[16]
    DIRECTION OUTPUT ;
    USE SIGNAL ;
    PORT
      LAYER M4 ;
        RECT 0.0000 16.8480 0.0840 16.8720 ;
    END
  END y[16]
  PIN y[170]
    DIRECTION OUTPUT ;
    USE SIGNAL ;
    PORT
      LAYER M4 ;
        RECT 0.0000 53.2320 0.0840 53.2560 ;
    END
  END y[170]
  PIN y[171]
    DIRECTION OUTPUT ;
    USE SIGNAL ;
    PORT
      LAYER M4 ;
        RECT 0.0000 53.4720 0.0840 53.4960 ;
    END
  END y[171]
  PIN y[172]
    DIRECTION OUTPUT ;
    USE SIGNAL ;
    PORT
      LAYER M4 ;
        RECT 0.0000 53.7120 0.0840 53.7360 ;
    END
  END y[172]
  PIN y[173]
    DIRECTION OUTPUT ;
    USE SIGNAL ;
    PORT
      LAYER M4 ;
        RECT 0.0000 53.9520 0.0840 53.9760 ;
    END
  END y[173]
  PIN y[174]
    DIRECTION OUTPUT ;
    USE SIGNAL ;
    PORT
      LAYER M4 ;
        RECT 0.0000 54.1920 0.0840 54.2160 ;
    END
  END y[174]
  PIN y[175]
    DIRECTION OUTPUT ;
    USE SIGNAL ;
    PORT
      LAYER M4 ;
        RECT 0.0000 54.4320 0.0840 54.4560 ;
    END
  END y[175]
  PIN y[176]
    DIRECTION OUTPUT ;
    USE SIGNAL ;
    PORT
      LAYER M4 ;
        RECT 0.0000 54.6240 0.0840 54.6480 ;
    END
  END y[176]
  PIN y[177]
    DIRECTION OUTPUT ;
    USE SIGNAL ;
    PORT
      LAYER M4 ;
        RECT 0.0000 54.8640 0.0840 54.8880 ;
    END
  END y[177]
  PIN y[178]
    DIRECTION OUTPUT ;
    USE SIGNAL ;
    PORT
      LAYER M4 ;
        RECT 0.0000 55.1040 0.0840 55.1280 ;
    END
  END y[178]
  PIN y[179]
    DIRECTION OUTPUT ;
    USE SIGNAL ;
    PORT
      LAYER M4 ;
        RECT 0.0000 55.3440 0.0840 55.3680 ;
    END
  END y[179]
  PIN y[17]
    DIRECTION OUTPUT ;
    USE SIGNAL ;
    PORT
      LAYER M4 ;
        RECT 0.0000 17.0880 0.0840 17.1120 ;
    END
  END y[17]
  PIN y[180]
    DIRECTION OUTPUT ;
    USE SIGNAL ;
    PORT
      LAYER M4 ;
        RECT 0.0000 55.5840 0.0840 55.6080 ;
    END
  END y[180]
  PIN y[181]
    DIRECTION OUTPUT ;
    USE SIGNAL ;
    PORT
      LAYER M4 ;
        RECT 0.0000 55.8240 0.0840 55.8480 ;
    END
  END y[181]
  PIN y[182]
    DIRECTION OUTPUT ;
    USE SIGNAL ;
    PORT
      LAYER M4 ;
        RECT 0.0000 56.0640 0.0840 56.0880 ;
    END
  END y[182]
  PIN y[183]
    DIRECTION OUTPUT ;
    USE SIGNAL ;
    PORT
      LAYER M4 ;
        RECT 0.0000 56.3040 0.0840 56.3280 ;
    END
  END y[183]
  PIN y[184]
    DIRECTION OUTPUT ;
    USE SIGNAL ;
    PORT
      LAYER M4 ;
        RECT 0.0000 56.5440 0.0840 56.5680 ;
    END
  END y[184]
  PIN y[185]
    DIRECTION OUTPUT ;
    USE SIGNAL ;
    PORT
      LAYER M4 ;
        RECT 0.0000 56.7840 0.0840 56.8080 ;
    END
  END y[185]
  PIN y[186]
    DIRECTION OUTPUT ;
    USE SIGNAL ;
    PORT
      LAYER M4 ;
        RECT 0.0000 57.0240 0.0840 57.0480 ;
    END
  END y[186]
  PIN y[187]
    DIRECTION OUTPUT ;
    USE SIGNAL ;
    PORT
      LAYER M4 ;
        RECT 0.0000 57.2640 0.0840 57.2880 ;
    END
  END y[187]
  PIN y[188]
    DIRECTION OUTPUT ;
    USE SIGNAL ;
    PORT
      LAYER M4 ;
        RECT 0.0000 57.5040 0.0840 57.5280 ;
    END
  END y[188]
  PIN y[189]
    DIRECTION OUTPUT ;
    USE SIGNAL ;
    PORT
      LAYER M4 ;
        RECT 0.0000 57.6960 0.0840 57.7200 ;
    END
  END y[189]
  PIN y[18]
    DIRECTION OUTPUT ;
    USE SIGNAL ;
    PORT
      LAYER M4 ;
        RECT 0.0000 17.3280 0.0840 17.3520 ;
    END
  END y[18]
  PIN y[190]
    DIRECTION OUTPUT ;
    USE SIGNAL ;
    PORT
      LAYER M4 ;
        RECT 0.0000 57.9360 0.0840 57.9600 ;
    END
  END y[190]
  PIN y[191]
    DIRECTION OUTPUT ;
    USE SIGNAL ;
    PORT
      LAYER M4 ;
        RECT 0.0000 58.1760 0.0840 58.2000 ;
    END
  END y[191]
  PIN y[192]
    DIRECTION OUTPUT ;
    USE SIGNAL ;
    PORT
      LAYER M4 ;
        RECT 0.0000 58.4160 0.0840 58.4400 ;
    END
  END y[192]
  PIN y[193]
    DIRECTION OUTPUT ;
    USE SIGNAL ;
    PORT
      LAYER M4 ;
        RECT 0.0000 58.6560 0.0840 58.6800 ;
    END
  END y[193]
  PIN y[194]
    DIRECTION OUTPUT ;
    USE SIGNAL ;
    PORT
      LAYER M4 ;
        RECT 0.0000 58.8960 0.0840 58.9200 ;
    END
  END y[194]
  PIN y[195]
    DIRECTION OUTPUT ;
    USE SIGNAL ;
    PORT
      LAYER M4 ;
        RECT 0.0000 59.1360 0.0840 59.1600 ;
    END
  END y[195]
  PIN y[196]
    DIRECTION OUTPUT ;
    USE SIGNAL ;
    PORT
      LAYER M4 ;
        RECT 0.0000 59.3760 0.0840 59.4000 ;
    END
  END y[196]
  PIN y[197]
    DIRECTION OUTPUT ;
    USE SIGNAL ;
    PORT
      LAYER M4 ;
        RECT 0.0000 59.6160 0.0840 59.6400 ;
    END
  END y[197]
  PIN y[198]
    DIRECTION OUTPUT ;
    USE SIGNAL ;
    PORT
      LAYER M4 ;
        RECT 0.0000 59.8560 0.0840 59.8800 ;
    END
  END y[198]
  PIN y[199]
    DIRECTION OUTPUT ;
    USE SIGNAL ;
    PORT
      LAYER M4 ;
        RECT 0.0000 60.0960 0.0840 60.1200 ;
    END
  END y[199]
  PIN y[19]
    DIRECTION OUTPUT ;
    USE SIGNAL ;
    PORT
      LAYER M4 ;
        RECT 0.0000 17.5680 0.0840 17.5920 ;
    END
  END y[19]
  PIN y[1]
    DIRECTION OUTPUT ;
    USE SIGNAL ;
    PORT
      LAYER M4 ;
        RECT 0.0000 13.2960 0.0840 13.3200 ;
    END
  END y[1]
  PIN y[200]
    DIRECTION OUTPUT ;
    USE SIGNAL ;
    PORT
      LAYER M4 ;
        RECT 0.0000 60.3360 0.0840 60.3600 ;
    END
  END y[200]
  PIN y[201]
    DIRECTION OUTPUT ;
    USE SIGNAL ;
    PORT
      LAYER M4 ;
        RECT 0.0000 60.5760 0.0840 60.6000 ;
    END
  END y[201]
  PIN y[202]
    DIRECTION OUTPUT ;
    USE SIGNAL ;
    PORT
      LAYER M4 ;
        RECT 0.0000 60.7680 0.0840 60.7920 ;
    END
  END y[202]
  PIN y[203]
    DIRECTION OUTPUT ;
    USE SIGNAL ;
    PORT
      LAYER M4 ;
        RECT 0.0000 61.0080 0.0840 61.0320 ;
    END
  END y[203]
  PIN y[204]
    DIRECTION OUTPUT ;
    USE SIGNAL ;
    PORT
      LAYER M4 ;
        RECT 0.0000 61.2480 0.0840 61.2720 ;
    END
  END y[204]
  PIN y[205]
    DIRECTION OUTPUT ;
    USE SIGNAL ;
    PORT
      LAYER M4 ;
        RECT 0.0000 61.4880 0.0840 61.5120 ;
    END
  END y[205]
  PIN y[206]
    DIRECTION OUTPUT ;
    USE SIGNAL ;
    PORT
      LAYER M4 ;
        RECT 0.0000 61.7280 0.0840 61.7520 ;
    END
  END y[206]
  PIN y[207]
    DIRECTION OUTPUT ;
    USE SIGNAL ;
    PORT
      LAYER M4 ;
        RECT 0.0000 61.9680 0.0840 61.9920 ;
    END
  END y[207]
  PIN y[208]
    DIRECTION OUTPUT ;
    USE SIGNAL ;
    PORT
      LAYER M4 ;
        RECT 0.0000 62.2080 0.0840 62.2320 ;
    END
  END y[208]
  PIN y[209]
    DIRECTION OUTPUT ;
    USE SIGNAL ;
    PORT
      LAYER M4 ;
        RECT 0.0000 62.4480 0.0840 62.4720 ;
    END
  END y[209]
  PIN y[20]
    DIRECTION OUTPUT ;
    USE SIGNAL ;
    PORT
      LAYER M4 ;
        RECT 0.0000 17.8080 0.0840 17.8320 ;
    END
  END y[20]
  PIN y[210]
    DIRECTION OUTPUT ;
    USE SIGNAL ;
    PORT
      LAYER M4 ;
        RECT 0.0000 62.6880 0.0840 62.7120 ;
    END
  END y[210]
  PIN y[211]
    DIRECTION OUTPUT ;
    USE SIGNAL ;
    PORT
      LAYER M4 ;
        RECT 0.0000 62.9280 0.0840 62.9520 ;
    END
  END y[211]
  PIN y[212]
    DIRECTION OUTPUT ;
    USE SIGNAL ;
    PORT
      LAYER M4 ;
        RECT 0.0000 63.1680 0.0840 63.1920 ;
    END
  END y[212]
  PIN y[213]
    DIRECTION OUTPUT ;
    USE SIGNAL ;
    PORT
      LAYER M4 ;
        RECT 0.0000 63.4080 0.0840 63.4320 ;
    END
  END y[213]
  PIN y[214]
    DIRECTION OUTPUT ;
    USE SIGNAL ;
    PORT
      LAYER M4 ;
        RECT 0.0000 63.6480 0.0840 63.6720 ;
    END
  END y[214]
  PIN y[215]
    DIRECTION OUTPUT ;
    USE SIGNAL ;
    PORT
      LAYER M4 ;
        RECT 0.0000 63.8400 0.0840 63.8640 ;
    END
  END y[215]
  PIN y[216]
    DIRECTION OUTPUT ;
    USE SIGNAL ;
    PORT
      LAYER M4 ;
        RECT 0.0000 64.0800 0.0840 64.1040 ;
    END
  END y[216]
  PIN y[217]
    DIRECTION OUTPUT ;
    USE SIGNAL ;
    PORT
      LAYER M4 ;
        RECT 0.0000 64.3200 0.0840 64.3440 ;
    END
  END y[217]
  PIN y[218]
    DIRECTION OUTPUT ;
    USE SIGNAL ;
    PORT
      LAYER M4 ;
        RECT 0.0000 64.5600 0.0840 64.5840 ;
    END
  END y[218]
  PIN y[219]
    DIRECTION OUTPUT ;
    USE SIGNAL ;
    PORT
      LAYER M4 ;
        RECT 0.0000 64.8000 0.0840 64.8240 ;
    END
  END y[219]
  PIN y[21]
    DIRECTION OUTPUT ;
    USE SIGNAL ;
    PORT
      LAYER M4 ;
        RECT 0.0000 18.0480 0.0840 18.0720 ;
    END
  END y[21]
  PIN y[220]
    DIRECTION OUTPUT ;
    USE SIGNAL ;
    PORT
      LAYER M4 ;
        RECT 0.0000 65.0400 0.0840 65.0640 ;
    END
  END y[220]
  PIN y[221]
    DIRECTION OUTPUT ;
    USE SIGNAL ;
    PORT
      LAYER M4 ;
        RECT 0.0000 65.2800 0.0840 65.3040 ;
    END
  END y[221]
  PIN y[222]
    DIRECTION OUTPUT ;
    USE SIGNAL ;
    PORT
      LAYER M4 ;
        RECT 0.0000 65.5200 0.0840 65.5440 ;
    END
  END y[222]
  PIN y[223]
    DIRECTION OUTPUT ;
    USE SIGNAL ;
    PORT
      LAYER M4 ;
        RECT 0.0000 65.7600 0.0840 65.7840 ;
    END
  END y[223]
  PIN y[224]
    DIRECTION OUTPUT ;
    USE SIGNAL ;
    PORT
      LAYER M4 ;
        RECT 0.0000 66.0000 0.0840 66.0240 ;
    END
  END y[224]
  PIN y[225]
    DIRECTION OUTPUT ;
    USE SIGNAL ;
    PORT
      LAYER M4 ;
        RECT 0.0000 66.2400 0.0840 66.2640 ;
    END
  END y[225]
  PIN y[226]
    DIRECTION OUTPUT ;
    USE SIGNAL ;
    PORT
      LAYER M4 ;
        RECT 0.0000 66.4800 0.0840 66.5040 ;
    END
  END y[226]
  PIN y[227]
    DIRECTION OUTPUT ;
    USE SIGNAL ;
    PORT
      LAYER M4 ;
        RECT 0.0000 66.6720 0.0840 66.6960 ;
    END
  END y[227]
  PIN y[228]
    DIRECTION OUTPUT ;
    USE SIGNAL ;
    PORT
      LAYER M4 ;
        RECT 0.0000 66.9120 0.0840 66.9360 ;
    END
  END y[228]
  PIN y[229]
    DIRECTION OUTPUT ;
    USE SIGNAL ;
    PORT
      LAYER M4 ;
        RECT 0.0000 67.1520 0.0840 67.1760 ;
    END
  END y[229]
  PIN y[22]
    DIRECTION OUTPUT ;
    USE SIGNAL ;
    PORT
      LAYER M4 ;
        RECT 0.0000 18.2880 0.0840 18.3120 ;
    END
  END y[22]
  PIN y[230]
    DIRECTION OUTPUT ;
    USE SIGNAL ;
    PORT
      LAYER M4 ;
        RECT 0.0000 67.3920 0.0840 67.4160 ;
    END
  END y[230]
  PIN y[231]
    DIRECTION OUTPUT ;
    USE SIGNAL ;
    PORT
      LAYER M4 ;
        RECT 0.0000 67.6320 0.0840 67.6560 ;
    END
  END y[231]
  PIN y[232]
    DIRECTION OUTPUT ;
    USE SIGNAL ;
    PORT
      LAYER M4 ;
        RECT 0.0000 67.8720 0.0840 67.8960 ;
    END
  END y[232]
  PIN y[233]
    DIRECTION OUTPUT ;
    USE SIGNAL ;
    PORT
      LAYER M4 ;
        RECT 0.0000 68.1120 0.0840 68.1360 ;
    END
  END y[233]
  PIN y[234]
    DIRECTION OUTPUT ;
    USE SIGNAL ;
    PORT
      LAYER M4 ;
        RECT 0.0000 68.3520 0.0840 68.3760 ;
    END
  END y[234]
  PIN y[235]
    DIRECTION OUTPUT ;
    USE SIGNAL ;
    PORT
      LAYER M4 ;
        RECT 0.0000 68.5920 0.0840 68.6160 ;
    END
  END y[235]
  PIN y[236]
    DIRECTION OUTPUT ;
    USE SIGNAL ;
    PORT
      LAYER M4 ;
        RECT 0.0000 68.8320 0.0840 68.8560 ;
    END
  END y[236]
  PIN y[237]
    DIRECTION OUTPUT ;
    USE SIGNAL ;
    PORT
      LAYER M4 ;
        RECT 0.0000 69.0720 0.0840 69.0960 ;
    END
  END y[237]
  PIN y[238]
    DIRECTION OUTPUT ;
    USE SIGNAL ;
    PORT
      LAYER M4 ;
        RECT 0.0000 69.3120 0.0840 69.3360 ;
    END
  END y[238]
  PIN y[239]
    DIRECTION OUTPUT ;
    USE SIGNAL ;
    PORT
      LAYER M4 ;
        RECT 0.0000 69.5520 0.0840 69.5760 ;
    END
  END y[239]
  PIN y[23]
    DIRECTION OUTPUT ;
    USE SIGNAL ;
    PORT
      LAYER M4 ;
        RECT 0.0000 18.4800 0.0840 18.5040 ;
    END
  END y[23]
  PIN y[240]
    DIRECTION OUTPUT ;
    USE SIGNAL ;
    PORT
      LAYER M4 ;
        RECT 0.0000 69.7440 0.0840 69.7680 ;
    END
  END y[240]
  PIN y[241]
    DIRECTION OUTPUT ;
    USE SIGNAL ;
    PORT
      LAYER M4 ;
        RECT 0.0000 69.9840 0.0840 70.0080 ;
    END
  END y[241]
  PIN y[242]
    DIRECTION OUTPUT ;
    USE SIGNAL ;
    PORT
      LAYER M4 ;
        RECT 0.0000 70.2240 0.0840 70.2480 ;
    END
  END y[242]
  PIN y[243]
    DIRECTION OUTPUT ;
    USE SIGNAL ;
    PORT
      LAYER M4 ;
        RECT 0.0000 70.4640 0.0840 70.4880 ;
    END
  END y[243]
  PIN y[244]
    DIRECTION OUTPUT ;
    USE SIGNAL ;
    PORT
      LAYER M4 ;
        RECT 0.0000 70.7040 0.0840 70.7280 ;
    END
  END y[244]
  PIN y[245]
    DIRECTION OUTPUT ;
    USE SIGNAL ;
    PORT
      LAYER M4 ;
        RECT 0.0000 70.9440 0.0840 70.9680 ;
    END
  END y[245]
  PIN y[246]
    DIRECTION OUTPUT ;
    USE SIGNAL ;
    PORT
      LAYER M4 ;
        RECT 0.0000 71.1840 0.0840 71.2080 ;
    END
  END y[246]
  PIN y[247]
    DIRECTION OUTPUT ;
    USE SIGNAL ;
    PORT
      LAYER M4 ;
        RECT 0.0000 71.4240 0.0840 71.4480 ;
    END
  END y[247]
  PIN y[248]
    DIRECTION OUTPUT ;
    USE SIGNAL ;
    PORT
      LAYER M4 ;
        RECT 0.0000 71.6640 0.0840 71.6880 ;
    END
  END y[248]
  PIN y[249]
    DIRECTION OUTPUT ;
    USE SIGNAL ;
    PORT
      LAYER M4 ;
        RECT 0.0000 71.9040 0.0840 71.9280 ;
    END
  END y[249]
  PIN y[24]
    DIRECTION OUTPUT ;
    USE SIGNAL ;
    PORT
      LAYER M4 ;
        RECT 0.0000 18.7200 0.0840 18.7440 ;
    END
  END y[24]
  PIN y[250]
    DIRECTION OUTPUT ;
    USE SIGNAL ;
    PORT
      LAYER M4 ;
        RECT 0.0000 72.1440 0.0840 72.1680 ;
    END
  END y[250]
  PIN y[251]
    DIRECTION OUTPUT ;
    USE SIGNAL ;
    PORT
      LAYER M4 ;
        RECT 0.0000 72.3840 0.0840 72.4080 ;
    END
  END y[251]
  PIN y[252]
    DIRECTION OUTPUT ;
    USE SIGNAL ;
    PORT
      LAYER M4 ;
        RECT 0.0000 72.6240 0.0840 72.6480 ;
    END
  END y[252]
  PIN y[253]
    DIRECTION OUTPUT ;
    USE SIGNAL ;
    PORT
      LAYER M4 ;
        RECT 0.0000 72.8160 0.0840 72.8400 ;
    END
  END y[253]
  PIN y[254]
    DIRECTION OUTPUT ;
    USE SIGNAL ;
    PORT
      LAYER M4 ;
        RECT 0.0000 73.0560 0.0840 73.0800 ;
    END
  END y[254]
  PIN y[255]
    DIRECTION OUTPUT ;
    USE SIGNAL ;
    PORT
      LAYER M4 ;
        RECT 0.0000 73.2960 0.0840 73.3200 ;
    END
  END y[255]
  PIN y[25]
    DIRECTION OUTPUT ;
    USE SIGNAL ;
    PORT
      LAYER M4 ;
        RECT 0.0000 18.9600 0.0840 18.9840 ;
    END
  END y[25]
  PIN y[26]
    DIRECTION OUTPUT ;
    USE SIGNAL ;
    PORT
      LAYER M4 ;
        RECT 0.0000 19.2000 0.0840 19.2240 ;
    END
  END y[26]
  PIN y[27]
    DIRECTION OUTPUT ;
    USE SIGNAL ;
    PORT
      LAYER M4 ;
        RECT 0.0000 19.4400 0.0840 19.4640 ;
    END
  END y[27]
  PIN y[28]
    DIRECTION OUTPUT ;
    USE SIGNAL ;
    PORT
      LAYER M4 ;
        RECT 0.0000 19.6800 0.0840 19.7040 ;
    END
  END y[28]
  PIN y[29]
    DIRECTION OUTPUT ;
    USE SIGNAL ;
    PORT
      LAYER M4 ;
        RECT 0.0000 19.9200 0.0840 19.9440 ;
    END
  END y[29]
  PIN y[2]
    DIRECTION OUTPUT ;
    USE SIGNAL ;
    PORT
      LAYER M4 ;
        RECT 0.0000 13.5360 0.0840 13.5600 ;
    END
  END y[2]
  PIN y[30]
    DIRECTION OUTPUT ;
    USE SIGNAL ;
    PORT
      LAYER M4 ;
        RECT 0.0000 20.1600 0.0840 20.1840 ;
    END
  END y[30]
  PIN y[31]
    DIRECTION OUTPUT ;
    USE SIGNAL ;
    PORT
      LAYER M4 ;
        RECT 0.0000 20.4000 0.0840 20.4240 ;
    END
  END y[31]
  PIN y[32]
    DIRECTION OUTPUT ;
    USE SIGNAL ;
    PORT
      LAYER M4 ;
        RECT 0.0000 20.6400 0.0840 20.6640 ;
    END
  END y[32]
  PIN y[33]
    DIRECTION OUTPUT ;
    USE SIGNAL ;
    PORT
      LAYER M4 ;
        RECT 0.0000 20.8800 0.0840 20.9040 ;
    END
  END y[33]
  PIN y[34]
    DIRECTION OUTPUT ;
    USE SIGNAL ;
    PORT
      LAYER M4 ;
        RECT 0.0000 21.1200 0.0840 21.1440 ;
    END
  END y[34]
  PIN y[35]
    DIRECTION OUTPUT ;
    USE SIGNAL ;
    PORT
      LAYER M4 ;
        RECT 0.0000 21.3120 0.0840 21.3360 ;
    END
  END y[35]
  PIN y[36]
    DIRECTION OUTPUT ;
    USE SIGNAL ;
    PORT
      LAYER M4 ;
        RECT 0.0000 21.5520 0.0840 21.5760 ;
    END
  END y[36]
  PIN y[37]
    DIRECTION OUTPUT ;
    USE SIGNAL ;
    PORT
      LAYER M4 ;
        RECT 0.0000 21.7920 0.0840 21.8160 ;
    END
  END y[37]
  PIN y[38]
    DIRECTION OUTPUT ;
    USE SIGNAL ;
    PORT
      LAYER M4 ;
        RECT 0.0000 22.0320 0.0840 22.0560 ;
    END
  END y[38]
  PIN y[39]
    DIRECTION OUTPUT ;
    USE SIGNAL ;
    PORT
      LAYER M4 ;
        RECT 0.0000 22.2720 0.0840 22.2960 ;
    END
  END y[39]
  PIN y[3]
    DIRECTION OUTPUT ;
    USE SIGNAL ;
    PORT
      LAYER M4 ;
        RECT 0.0000 13.7760 0.0840 13.8000 ;
    END
  END y[3]
  PIN y[40]
    DIRECTION OUTPUT ;
    USE SIGNAL ;
    PORT
      LAYER M4 ;
        RECT 0.0000 22.5120 0.0840 22.5360 ;
    END
  END y[40]
  PIN y[41]
    DIRECTION OUTPUT ;
    USE SIGNAL ;
    PORT
      LAYER M4 ;
        RECT 0.0000 22.7520 0.0840 22.7760 ;
    END
  END y[41]
  PIN y[42]
    DIRECTION OUTPUT ;
    USE SIGNAL ;
    PORT
      LAYER M4 ;
        RECT 0.0000 22.9920 0.0840 23.0160 ;
    END
  END y[42]
  PIN y[43]
    DIRECTION OUTPUT ;
    USE SIGNAL ;
    PORT
      LAYER M4 ;
        RECT 0.0000 23.2320 0.0840 23.2560 ;
    END
  END y[43]
  PIN y[44]
    DIRECTION OUTPUT ;
    USE SIGNAL ;
    PORT
      LAYER M4 ;
        RECT 0.0000 23.4720 0.0840 23.4960 ;
    END
  END y[44]
  PIN y[45]
    DIRECTION OUTPUT ;
    USE SIGNAL ;
    PORT
      LAYER M4 ;
        RECT 0.0000 23.7120 0.0840 23.7360 ;
    END
  END y[45]
  PIN y[46]
    DIRECTION OUTPUT ;
    USE SIGNAL ;
    PORT
      LAYER M4 ;
        RECT 0.0000 23.9520 0.0840 23.9760 ;
    END
  END y[46]
  PIN y[47]
    DIRECTION OUTPUT ;
    USE SIGNAL ;
    PORT
      LAYER M4 ;
        RECT 0.0000 24.1920 0.0840 24.2160 ;
    END
  END y[47]
  PIN y[48]
    DIRECTION OUTPUT ;
    USE SIGNAL ;
    PORT
      LAYER M4 ;
        RECT 0.0000 24.3840 0.0840 24.4080 ;
    END
  END y[48]
  PIN y[49]
    DIRECTION OUTPUT ;
    USE SIGNAL ;
    PORT
      LAYER M4 ;
        RECT 0.0000 24.6240 0.0840 24.6480 ;
    END
  END y[49]
  PIN y[4]
    DIRECTION OUTPUT ;
    USE SIGNAL ;
    PORT
      LAYER M4 ;
        RECT 0.0000 14.0160 0.0840 14.0400 ;
    END
  END y[4]
  PIN y[50]
    DIRECTION OUTPUT ;
    USE SIGNAL ;
    PORT
      LAYER M4 ;
        RECT 0.0000 24.8640 0.0840 24.8880 ;
    END
  END y[50]
  PIN y[51]
    DIRECTION OUTPUT ;
    USE SIGNAL ;
    PORT
      LAYER M4 ;
        RECT 0.0000 25.1040 0.0840 25.1280 ;
    END
  END y[51]
  PIN y[52]
    DIRECTION OUTPUT ;
    USE SIGNAL ;
    PORT
      LAYER M4 ;
        RECT 0.0000 25.3440 0.0840 25.3680 ;
    END
  END y[52]
  PIN y[53]
    DIRECTION OUTPUT ;
    USE SIGNAL ;
    PORT
      LAYER M4 ;
        RECT 0.0000 25.5840 0.0840 25.6080 ;
    END
  END y[53]
  PIN y[54]
    DIRECTION OUTPUT ;
    USE SIGNAL ;
    PORT
      LAYER M4 ;
        RECT 0.0000 25.8240 0.0840 25.8480 ;
    END
  END y[54]
  PIN y[55]
    DIRECTION OUTPUT ;
    USE SIGNAL ;
    PORT
      LAYER M4 ;
        RECT 0.0000 26.0640 0.0840 26.0880 ;
    END
  END y[55]
  PIN y[56]
    DIRECTION OUTPUT ;
    USE SIGNAL ;
    PORT
      LAYER M4 ;
        RECT 0.0000 26.3040 0.0840 26.3280 ;
    END
  END y[56]
  PIN y[57]
    DIRECTION OUTPUT ;
    USE SIGNAL ;
    PORT
      LAYER M4 ;
        RECT 0.0000 26.5440 0.0840 26.5680 ;
    END
  END y[57]
  PIN y[58]
    DIRECTION OUTPUT ;
    USE SIGNAL ;
    PORT
      LAYER M4 ;
        RECT 0.0000 26.7840 0.0840 26.8080 ;
    END
  END y[58]
  PIN y[59]
    DIRECTION OUTPUT ;
    USE SIGNAL ;
    PORT
      LAYER M4 ;
        RECT 0.0000 27.0240 0.0840 27.0480 ;
    END
  END y[59]
  PIN y[5]
    DIRECTION OUTPUT ;
    USE SIGNAL ;
    PORT
      LAYER M4 ;
        RECT 0.0000 14.2560 0.0840 14.2800 ;
    END
  END y[5]
  PIN y[60]
    DIRECTION OUTPUT ;
    USE SIGNAL ;
    PORT
      LAYER M4 ;
        RECT 0.0000 27.2640 0.0840 27.2880 ;
    END
  END y[60]
  PIN y[61]
    DIRECTION OUTPUT ;
    USE SIGNAL ;
    PORT
      LAYER M4 ;
        RECT 0.0000 27.4560 0.0840 27.4800 ;
    END
  END y[61]
  PIN y[62]
    DIRECTION OUTPUT ;
    USE SIGNAL ;
    PORT
      LAYER M4 ;
        RECT 0.0000 27.6960 0.0840 27.7200 ;
    END
  END y[62]
  PIN y[63]
    DIRECTION OUTPUT ;
    USE SIGNAL ;
    PORT
      LAYER M4 ;
        RECT 0.0000 27.9360 0.0840 27.9600 ;
    END
  END y[63]
  PIN y[64]
    DIRECTION OUTPUT ;
    USE SIGNAL ;
    PORT
      LAYER M4 ;
        RECT 0.0000 28.1760 0.0840 28.2000 ;
    END
  END y[64]
  PIN y[65]
    DIRECTION OUTPUT ;
    USE SIGNAL ;
    PORT
      LAYER M4 ;
        RECT 0.0000 28.4160 0.0840 28.4400 ;
    END
  END y[65]
  PIN y[66]
    DIRECTION OUTPUT ;
    USE SIGNAL ;
    PORT
      LAYER M4 ;
        RECT 0.0000 28.6560 0.0840 28.6800 ;
    END
  END y[66]
  PIN y[67]
    DIRECTION OUTPUT ;
    USE SIGNAL ;
    PORT
      LAYER M4 ;
        RECT 0.0000 28.8960 0.0840 28.9200 ;
    END
  END y[67]
  PIN y[68]
    DIRECTION OUTPUT ;
    USE SIGNAL ;
    PORT
      LAYER M4 ;
        RECT 0.0000 29.1360 0.0840 29.1600 ;
    END
  END y[68]
  PIN y[69]
    DIRECTION OUTPUT ;
    USE SIGNAL ;
    PORT
      LAYER M4 ;
        RECT 0.0000 29.3760 0.0840 29.4000 ;
    END
  END y[69]
  PIN y[6]
    DIRECTION OUTPUT ;
    USE SIGNAL ;
    PORT
      LAYER M4 ;
        RECT 0.0000 14.4960 0.0840 14.5200 ;
    END
  END y[6]
  PIN y[70]
    DIRECTION OUTPUT ;
    USE SIGNAL ;
    PORT
      LAYER M4 ;
        RECT 0.0000 29.6160 0.0840 29.6400 ;
    END
  END y[70]
  PIN y[71]
    DIRECTION OUTPUT ;
    USE SIGNAL ;
    PORT
      LAYER M4 ;
        RECT 0.0000 29.8560 0.0840 29.8800 ;
    END
  END y[71]
  PIN y[72]
    DIRECTION OUTPUT ;
    USE SIGNAL ;
    PORT
      LAYER M4 ;
        RECT 0.0000 30.0960 0.0840 30.1200 ;
    END
  END y[72]
  PIN y[73]
    DIRECTION OUTPUT ;
    USE SIGNAL ;
    PORT
      LAYER M4 ;
        RECT 0.0000 30.3360 0.0840 30.3600 ;
    END
  END y[73]
  PIN y[74]
    DIRECTION OUTPUT ;
    USE SIGNAL ;
    PORT
      LAYER M4 ;
        RECT 0.0000 30.5280 0.0840 30.5520 ;
    END
  END y[74]
  PIN y[75]
    DIRECTION OUTPUT ;
    USE SIGNAL ;
    PORT
      LAYER M4 ;
        RECT 0.0000 30.7680 0.0840 30.7920 ;
    END
  END y[75]
  PIN y[76]
    DIRECTION OUTPUT ;
    USE SIGNAL ;
    PORT
      LAYER M4 ;
        RECT 0.0000 31.0080 0.0840 31.0320 ;
    END
  END y[76]
  PIN y[77]
    DIRECTION OUTPUT ;
    USE SIGNAL ;
    PORT
      LAYER M4 ;
        RECT 0.0000 31.2480 0.0840 31.2720 ;
    END
  END y[77]
  PIN y[78]
    DIRECTION OUTPUT ;
    USE SIGNAL ;
    PORT
      LAYER M4 ;
        RECT 0.0000 31.4880 0.0840 31.5120 ;
    END
  END y[78]
  PIN y[79]
    DIRECTION OUTPUT ;
    USE SIGNAL ;
    PORT
      LAYER M4 ;
        RECT 0.0000 31.7280 0.0840 31.7520 ;
    END
  END y[79]
  PIN y[7]
    DIRECTION OUTPUT ;
    USE SIGNAL ;
    PORT
      LAYER M4 ;
        RECT 0.0000 14.7360 0.0840 14.7600 ;
    END
  END y[7]
  PIN y[80]
    DIRECTION OUTPUT ;
    USE SIGNAL ;
    PORT
      LAYER M4 ;
        RECT 0.0000 31.9680 0.0840 31.9920 ;
    END
  END y[80]
  PIN y[81]
    DIRECTION OUTPUT ;
    USE SIGNAL ;
    PORT
      LAYER M4 ;
        RECT 0.0000 32.2080 0.0840 32.2320 ;
    END
  END y[81]
  PIN y[82]
    DIRECTION OUTPUT ;
    USE SIGNAL ;
    PORT
      LAYER M4 ;
        RECT 0.0000 32.4480 0.0840 32.4720 ;
    END
  END y[82]
  PIN y[83]
    DIRECTION OUTPUT ;
    USE SIGNAL ;
    PORT
      LAYER M4 ;
        RECT 0.0000 32.6880 0.0840 32.7120 ;
    END
  END y[83]
  PIN y[84]
    DIRECTION OUTPUT ;
    USE SIGNAL ;
    PORT
      LAYER M4 ;
        RECT 0.0000 32.9280 0.0840 32.9520 ;
    END
  END y[84]
  PIN y[85]
    DIRECTION OUTPUT ;
    USE SIGNAL ;
    PORT
      LAYER M4 ;
        RECT 0.0000 33.1680 0.0840 33.1920 ;
    END
  END y[85]
  PIN y[86]
    DIRECTION OUTPUT ;
    USE SIGNAL ;
    PORT
      LAYER M4 ;
        RECT 0.0000 33.4080 0.0840 33.4320 ;
    END
  END y[86]
  PIN y[87]
    DIRECTION OUTPUT ;
    USE SIGNAL ;
    PORT
      LAYER M4 ;
        RECT 0.0000 33.6000 0.0840 33.6240 ;
    END
  END y[87]
  PIN y[88]
    DIRECTION OUTPUT ;
    USE SIGNAL ;
    PORT
      LAYER M4 ;
        RECT 0.0000 33.8400 0.0840 33.8640 ;
    END
  END y[88]
  PIN y[89]
    DIRECTION OUTPUT ;
    USE SIGNAL ;
    PORT
      LAYER M4 ;
        RECT 0.0000 34.0800 0.0840 34.1040 ;
    END
  END y[89]
  PIN y[8]
    DIRECTION OUTPUT ;
    USE SIGNAL ;
    PORT
      LAYER M4 ;
        RECT 0.0000 14.9760 0.0840 15.0000 ;
    END
  END y[8]
  PIN y[90]
    DIRECTION OUTPUT ;
    USE SIGNAL ;
    PORT
      LAYER M4 ;
        RECT 0.0000 34.3200 0.0840 34.3440 ;
    END
  END y[90]
  PIN y[91]
    DIRECTION OUTPUT ;
    USE SIGNAL ;
    PORT
      LAYER M4 ;
        RECT 0.0000 34.5600 0.0840 34.5840 ;
    END
  END y[91]
  PIN y[92]
    DIRECTION OUTPUT ;
    USE SIGNAL ;
    PORT
      LAYER M4 ;
        RECT 0.0000 34.8000 0.0840 34.8240 ;
    END
  END y[92]
  PIN y[93]
    DIRECTION OUTPUT ;
    USE SIGNAL ;
    PORT
      LAYER M4 ;
        RECT 0.0000 35.0400 0.0840 35.0640 ;
    END
  END y[93]
  PIN y[94]
    DIRECTION OUTPUT ;
    USE SIGNAL ;
    PORT
      LAYER M4 ;
        RECT 0.0000 35.2800 0.0840 35.3040 ;
    END
  END y[94]
  PIN y[95]
    DIRECTION OUTPUT ;
    USE SIGNAL ;
    PORT
      LAYER M4 ;
        RECT 0.0000 35.5200 0.0840 35.5440 ;
    END
  END y[95]
  PIN y[96]
    DIRECTION OUTPUT ;
    USE SIGNAL ;
    PORT
      LAYER M4 ;
        RECT 0.0000 35.7600 0.0840 35.7840 ;
    END
  END y[96]
  PIN y[97]
    DIRECTION OUTPUT ;
    USE SIGNAL ;
    PORT
      LAYER M4 ;
        RECT 0.0000 36.0000 0.0840 36.0240 ;
    END
  END y[97]
  PIN y[98]
    DIRECTION OUTPUT ;
    USE SIGNAL ;
    PORT
      LAYER M4 ;
        RECT 0.0000 36.2400 0.0840 36.2640 ;
    END
  END y[98]
  PIN y[99]
    DIRECTION OUTPUT ;
    USE SIGNAL ;
    PORT
      LAYER M4 ;
        RECT 0.0000 36.4320 0.0840 36.4560 ;
    END
  END y[99]
  PIN y[9]
    DIRECTION OUTPUT ;
    USE SIGNAL ;
    PORT
      LAYER M4 ;
        RECT 0.0000 15.2160 0.0840 15.2400 ;
    END
  END y[9]
  PIN y_i[0]
    DIRECTION OUTPUT ;
    USE SIGNAL ;
    PORT
      LAYER M4 ;
        RECT 0.3415 9.3600 0.4255 9.3840 ;
    END
  END y_i[0]
  PIN y_i[1]
    DIRECTION OUTPUT ;
    USE SIGNAL ;
    PORT
      LAYER M4 ;
        RECT 0.0000 10.8000 0.0840 10.8240 ;
    END
  END y_i[1]
  PIN y_i[2]
    DIRECTION OUTPUT ;
    USE SIGNAL ;
    PORT
      LAYER M4 ;
        RECT 0.0000 12.2400 0.0840 12.2640 ;
    END
  END y_i[2]
  PIN y_v
    DIRECTION OUTPUT ;
    USE SIGNAL ;
    PORT
      LAYER M4 ;
        RECT 0.6475 7.5360 0.7315 7.5600 ;
    END
  END y_v
  OBS
    LAYER M1 ;
      RECT 0.5 0.5 355.900 355.900 ;
    LAYER M2 ;
      RECT 0.5 0.5 355.900 355.900 ;
    LAYER M3 ;
      RECT 0.5 0.5 355.900 355.900 ;
    LAYER M4 ;
      RECT 0.5 0.5 355.900 355.900 ;
    LAYER M5 ;
      RECT 0.5 0.5 355.900 355.900 ;
    LAYER M6 ;
      RECT 0.5 0.5 355.900 355.900 ;
    LAYER M7 ;
      RECT 0.5 0.5 355.900 355.900 ;
  END
END ot_s81sl_vn
END LIBRARY
